VERSION 5.7 ;
BUSBITCHARS "[]" ;
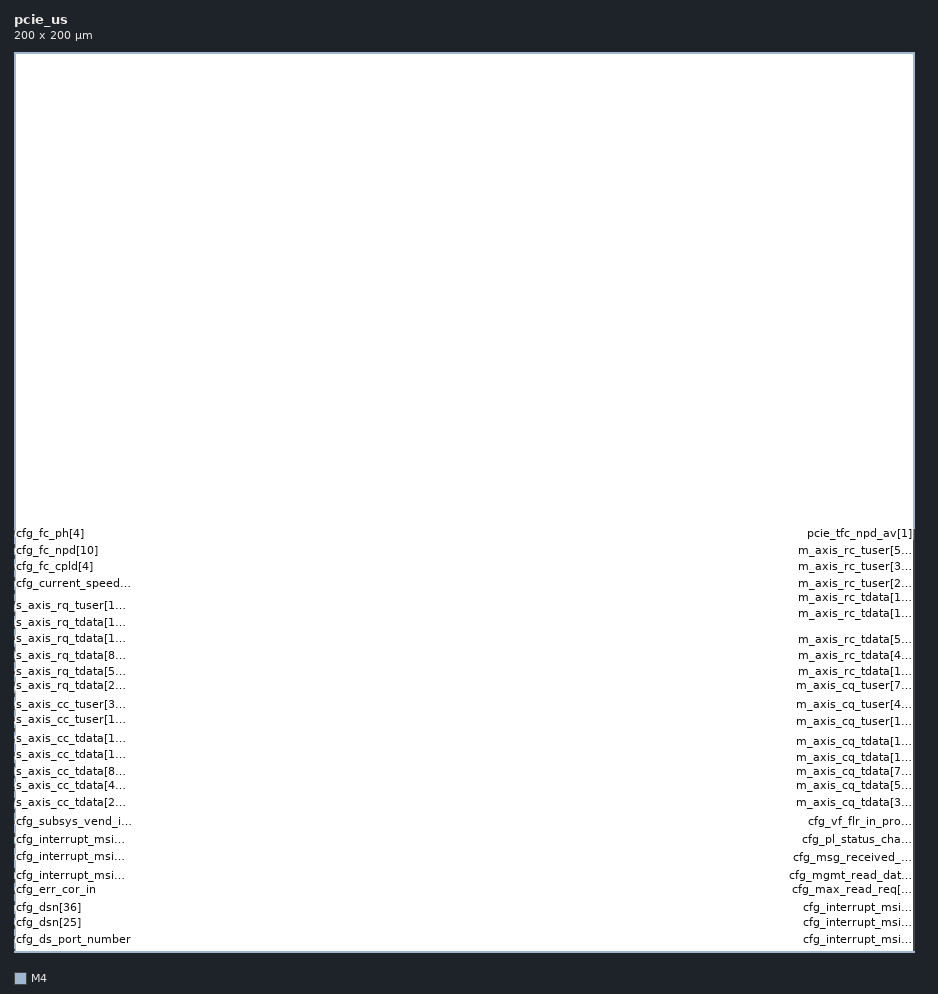
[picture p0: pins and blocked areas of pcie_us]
MACRO pcie_us
  CLASS BLOCK ;
  FOREIGN pcie_us 0 0 ;
  SYMMETRY X Y R90 ;
  SIZE 200.000 BY 200.000 ;
  PIN cfg_config_space_enable
    DIRECTION INPUT ;
    USE SIGNAL ;
    PORT
      LAYER M4 ;
      RECT 0.000 0.288 0.072 0.312 ;
    END
  END cfg_config_space_enable
  PIN cfg_ds_bus_number[0]
    DIRECTION INPUT ;
    USE SIGNAL ;
    PORT
      LAYER M4 ;
      RECT 0.000 0.432 0.072 0.456 ;
    END
  END cfg_ds_bus_number[0]
  PIN cfg_ds_bus_number[1]
    DIRECTION INPUT ;
    USE SIGNAL ;
    PORT
      LAYER M4 ;
      RECT 0.000 0.576 0.072 0.600 ;
    END
  END cfg_ds_bus_number[1]
  PIN cfg_ds_bus_number[2]
    DIRECTION INPUT ;
    USE SIGNAL ;
    PORT
      LAYER M4 ;
      RECT 0.000 0.720 0.072 0.744 ;
    END
  END cfg_ds_bus_number[2]
  PIN cfg_ds_bus_number[3]
    DIRECTION INPUT ;
    USE SIGNAL ;
    PORT
      LAYER M4 ;
      RECT 0.000 0.864 0.072 0.888 ;
    END
  END cfg_ds_bus_number[3]
  PIN cfg_ds_bus_number[4]
    DIRECTION INPUT ;
    USE SIGNAL ;
    PORT
      LAYER M4 ;
      RECT 0.000 1.008 0.072 1.032 ;
    END
  END cfg_ds_bus_number[4]
  PIN cfg_ds_bus_number[5]
    DIRECTION INPUT ;
    USE SIGNAL ;
    PORT
      LAYER M4 ;
      RECT 0.000 1.152 0.072 1.176 ;
    END
  END cfg_ds_bus_number[5]
  PIN cfg_ds_bus_number[6]
    DIRECTION INPUT ;
    USE SIGNAL ;
    PORT
      LAYER M4 ;
      RECT 0.000 1.296 0.072 1.320 ;
    END
  END cfg_ds_bus_number[6]
  PIN cfg_ds_bus_number[7]
    DIRECTION INPUT ;
    USE SIGNAL ;
    PORT
      LAYER M4 ;
      RECT 0.000 1.440 0.072 1.464 ;
    END
  END cfg_ds_bus_number[7]
  PIN cfg_ds_device_number[0]
    DIRECTION INPUT ;
    USE SIGNAL ;
    PORT
      LAYER M4 ;
      RECT 0.000 1.584 0.072 1.608 ;
    END
  END cfg_ds_device_number[0]
  PIN cfg_ds_device_number[1]
    DIRECTION INPUT ;
    USE SIGNAL ;
    PORT
      LAYER M4 ;
      RECT 0.000 1.728 0.072 1.752 ;
    END
  END cfg_ds_device_number[1]
  PIN cfg_ds_device_number[2]
    DIRECTION INPUT ;
    USE SIGNAL ;
    PORT
      LAYER M4 ;
      RECT 0.000 1.872 0.072 1.896 ;
    END
  END cfg_ds_device_number[2]
  PIN cfg_ds_device_number[3]
    DIRECTION INPUT ;
    USE SIGNAL ;
    PORT
      LAYER M4 ;
      RECT 0.000 2.016 0.072 2.040 ;
    END
  END cfg_ds_device_number[3]
  PIN cfg_ds_device_number[4]
    DIRECTION INPUT ;
    USE SIGNAL ;
    PORT
      LAYER M4 ;
      RECT 0.000 2.160 0.072 2.184 ;
    END
  END cfg_ds_device_number[4]
  PIN cfg_ds_function_number[0]
    DIRECTION INPUT ;
    USE SIGNAL ;
    PORT
      LAYER M4 ;
      RECT 0.000 2.304 0.072 2.328 ;
    END
  END cfg_ds_function_number[0]
  PIN cfg_ds_function_number[1]
    DIRECTION INPUT ;
    USE SIGNAL ;
    PORT
      LAYER M4 ;
      RECT 0.000 2.448 0.072 2.472 ;
    END
  END cfg_ds_function_number[1]
  PIN cfg_ds_function_number[2]
    DIRECTION INPUT ;
    USE SIGNAL ;
    PORT
      LAYER M4 ;
      RECT 0.000 2.592 0.072 2.616 ;
    END
  END cfg_ds_function_number[2]
  PIN cfg_ds_port_number
    DIRECTION INPUT ;
    USE SIGNAL ;
    PORT
      LAYER M4 ;
      RECT 0.000 2.736 0.072 2.760 ;
    END
  END cfg_ds_port_number
  PIN cfg_dsn[0]
    DIRECTION INPUT ;
    USE SIGNAL ;
    PORT
      LAYER M4 ;
      RECT 0.000 2.880 0.072 2.904 ;
    END
  END cfg_dsn[0]
  PIN cfg_dsn[1]
    DIRECTION INPUT ;
    USE SIGNAL ;
    PORT
      LAYER M4 ;
      RECT 0.000 3.024 0.072 3.048 ;
    END
  END cfg_dsn[1]
  PIN cfg_dsn[2]
    DIRECTION INPUT ;
    USE SIGNAL ;
    PORT
      LAYER M4 ;
      RECT 0.000 3.168 0.072 3.192 ;
    END
  END cfg_dsn[2]
  PIN cfg_dsn[3]
    DIRECTION INPUT ;
    USE SIGNAL ;
    PORT
      LAYER M4 ;
      RECT 0.000 3.312 0.072 3.336 ;
    END
  END cfg_dsn[3]
  PIN cfg_dsn[4]
    DIRECTION INPUT ;
    USE SIGNAL ;
    PORT
      LAYER M4 ;
      RECT 0.000 3.456 0.072 3.480 ;
    END
  END cfg_dsn[4]
  PIN cfg_dsn[5]
    DIRECTION INPUT ;
    USE SIGNAL ;
    PORT
      LAYER M4 ;
      RECT 0.000 3.600 0.072 3.624 ;
    END
  END cfg_dsn[5]
  PIN cfg_dsn[6]
    DIRECTION INPUT ;
    USE SIGNAL ;
    PORT
      LAYER M4 ;
      RECT 0.000 3.744 0.072 3.768 ;
    END
  END cfg_dsn[6]
  PIN cfg_dsn[7]
    DIRECTION INPUT ;
    USE SIGNAL ;
    PORT
      LAYER M4 ;
      RECT 0.000 3.888 0.072 3.912 ;
    END
  END cfg_dsn[7]
  PIN cfg_dsn[8]
    DIRECTION INPUT ;
    USE SIGNAL ;
    PORT
      LAYER M4 ;
      RECT 0.000 4.032 0.072 4.056 ;
    END
  END cfg_dsn[8]
  PIN cfg_dsn[9]
    DIRECTION INPUT ;
    USE SIGNAL ;
    PORT
      LAYER M4 ;
      RECT 0.000 4.176 0.072 4.200 ;
    END
  END cfg_dsn[9]
  PIN cfg_dsn[10]
    DIRECTION INPUT ;
    USE SIGNAL ;
    PORT
      LAYER M4 ;
      RECT 0.000 4.320 0.072 4.344 ;
    END
  END cfg_dsn[10]
  PIN cfg_dsn[11]
    DIRECTION INPUT ;
    USE SIGNAL ;
    PORT
      LAYER M4 ;
      RECT 0.000 4.464 0.072 4.488 ;
    END
  END cfg_dsn[11]
  PIN cfg_dsn[12]
    DIRECTION INPUT ;
    USE SIGNAL ;
    PORT
      LAYER M4 ;
      RECT 0.000 4.608 0.072 4.632 ;
    END
  END cfg_dsn[12]
  PIN cfg_dsn[13]
    DIRECTION INPUT ;
    USE SIGNAL ;
    PORT
      LAYER M4 ;
      RECT 0.000 4.752 0.072 4.776 ;
    END
  END cfg_dsn[13]
  PIN cfg_dsn[14]
    DIRECTION INPUT ;
    USE SIGNAL ;
    PORT
      LAYER M4 ;
      RECT 0.000 4.896 0.072 4.920 ;
    END
  END cfg_dsn[14]
  PIN cfg_dsn[15]
    DIRECTION INPUT ;
    USE SIGNAL ;
    PORT
      LAYER M4 ;
      RECT 0.000 5.040 0.072 5.064 ;
    END
  END cfg_dsn[15]
  PIN cfg_dsn[16]
    DIRECTION INPUT ;
    USE SIGNAL ;
    PORT
      LAYER M4 ;
      RECT 0.000 5.184 0.072 5.208 ;
    END
  END cfg_dsn[16]
  PIN cfg_dsn[17]
    DIRECTION INPUT ;
    USE SIGNAL ;
    PORT
      LAYER M4 ;
      RECT 0.000 5.328 0.072 5.352 ;
    END
  END cfg_dsn[17]
  PIN cfg_dsn[18]
    DIRECTION INPUT ;
    USE SIGNAL ;
    PORT
      LAYER M4 ;
      RECT 0.000 5.472 0.072 5.496 ;
    END
  END cfg_dsn[18]
  PIN cfg_dsn[19]
    DIRECTION INPUT ;
    USE SIGNAL ;
    PORT
      LAYER M4 ;
      RECT 0.000 5.616 0.072 5.640 ;
    END
  END cfg_dsn[19]
  PIN cfg_dsn[20]
    DIRECTION INPUT ;
    USE SIGNAL ;
    PORT
      LAYER M4 ;
      RECT 0.000 5.760 0.072 5.784 ;
    END
  END cfg_dsn[20]
  PIN cfg_dsn[21]
    DIRECTION INPUT ;
    USE SIGNAL ;
    PORT
      LAYER M4 ;
      RECT 0.000 5.904 0.072 5.928 ;
    END
  END cfg_dsn[21]
  PIN cfg_dsn[22]
    DIRECTION INPUT ;
    USE SIGNAL ;
    PORT
      LAYER M4 ;
      RECT 0.000 6.048 0.072 6.072 ;
    END
  END cfg_dsn[22]
  PIN cfg_dsn[23]
    DIRECTION INPUT ;
    USE SIGNAL ;
    PORT
      LAYER M4 ;
      RECT 0.000 6.192 0.072 6.216 ;
    END
  END cfg_dsn[23]
  PIN cfg_dsn[24]
    DIRECTION INPUT ;
    USE SIGNAL ;
    PORT
      LAYER M4 ;
      RECT 0.000 6.336 0.072 6.360 ;
    END
  END cfg_dsn[24]
  PIN cfg_dsn[25]
    DIRECTION INPUT ;
    USE SIGNAL ;
    PORT
      LAYER M4 ;
      RECT 0.000 6.480 0.072 6.504 ;
    END
  END cfg_dsn[25]
  PIN cfg_dsn[26]
    DIRECTION INPUT ;
    USE SIGNAL ;
    PORT
      LAYER M4 ;
      RECT 0.000 6.624 0.072 6.648 ;
    END
  END cfg_dsn[26]
  PIN cfg_dsn[27]
    DIRECTION INPUT ;
    USE SIGNAL ;
    PORT
      LAYER M4 ;
      RECT 0.000 6.768 0.072 6.792 ;
    END
  END cfg_dsn[27]
  PIN cfg_dsn[28]
    DIRECTION INPUT ;
    USE SIGNAL ;
    PORT
      LAYER M4 ;
      RECT 0.000 6.912 0.072 6.936 ;
    END
  END cfg_dsn[28]
  PIN cfg_dsn[29]
    DIRECTION INPUT ;
    USE SIGNAL ;
    PORT
      LAYER M4 ;
      RECT 0.000 7.056 0.072 7.080 ;
    END
  END cfg_dsn[29]
  PIN cfg_dsn[30]
    DIRECTION INPUT ;
    USE SIGNAL ;
    PORT
      LAYER M4 ;
      RECT 0.000 7.200 0.072 7.224 ;
    END
  END cfg_dsn[30]
  PIN cfg_dsn[31]
    DIRECTION INPUT ;
    USE SIGNAL ;
    PORT
      LAYER M4 ;
      RECT 0.000 7.344 0.072 7.368 ;
    END
  END cfg_dsn[31]
  PIN cfg_dsn[32]
    DIRECTION INPUT ;
    USE SIGNAL ;
    PORT
      LAYER M4 ;
      RECT 0.000 7.488 0.072 7.512 ;
    END
  END cfg_dsn[32]
  PIN cfg_dsn[33]
    DIRECTION INPUT ;
    USE SIGNAL ;
    PORT
      LAYER M4 ;
      RECT 0.000 7.632 0.072 7.656 ;
    END
  END cfg_dsn[33]
  PIN cfg_dsn[34]
    DIRECTION INPUT ;
    USE SIGNAL ;
    PORT
      LAYER M4 ;
      RECT 0.000 7.776 0.072 7.800 ;
    END
  END cfg_dsn[34]
  PIN cfg_dsn[35]
    DIRECTION INPUT ;
    USE SIGNAL ;
    PORT
      LAYER M4 ;
      RECT 0.000 7.920 0.072 7.944 ;
    END
  END cfg_dsn[35]
  PIN cfg_dsn[36]
    DIRECTION INPUT ;
    USE SIGNAL ;
    PORT
      LAYER M4 ;
      RECT 0.000 8.064 0.072 8.088 ;
    END
  END cfg_dsn[36]
  PIN cfg_dsn[37]
    DIRECTION INPUT ;
    USE SIGNAL ;
    PORT
      LAYER M4 ;
      RECT 0.000 8.208 0.072 8.232 ;
    END
  END cfg_dsn[37]
  PIN cfg_dsn[38]
    DIRECTION INPUT ;
    USE SIGNAL ;
    PORT
      LAYER M4 ;
      RECT 0.000 8.352 0.072 8.376 ;
    END
  END cfg_dsn[38]
  PIN cfg_dsn[39]
    DIRECTION INPUT ;
    USE SIGNAL ;
    PORT
      LAYER M4 ;
      RECT 0.000 8.496 0.072 8.520 ;
    END
  END cfg_dsn[39]
  PIN cfg_dsn[40]
    DIRECTION INPUT ;
    USE SIGNAL ;
    PORT
      LAYER M4 ;
      RECT 0.000 8.640 0.072 8.664 ;
    END
  END cfg_dsn[40]
  PIN cfg_dsn[41]
    DIRECTION INPUT ;
    USE SIGNAL ;
    PORT
      LAYER M4 ;
      RECT 0.000 8.784 0.072 8.808 ;
    END
  END cfg_dsn[41]
  PIN cfg_dsn[42]
    DIRECTION INPUT ;
    USE SIGNAL ;
    PORT
      LAYER M4 ;
      RECT 0.000 8.928 0.072 8.952 ;
    END
  END cfg_dsn[42]
  PIN cfg_dsn[43]
    DIRECTION INPUT ;
    USE SIGNAL ;
    PORT
      LAYER M4 ;
      RECT 0.000 9.072 0.072 9.096 ;
    END
  END cfg_dsn[43]
  PIN cfg_dsn[44]
    DIRECTION INPUT ;
    USE SIGNAL ;
    PORT
      LAYER M4 ;
      RECT 0.000 9.216 0.072 9.240 ;
    END
  END cfg_dsn[44]
  PIN cfg_dsn[45]
    DIRECTION INPUT ;
    USE SIGNAL ;
    PORT
      LAYER M4 ;
      RECT 0.000 9.360 0.072 9.384 ;
    END
  END cfg_dsn[45]
  PIN cfg_dsn[46]
    DIRECTION INPUT ;
    USE SIGNAL ;
    PORT
      LAYER M4 ;
      RECT 0.000 9.504 0.072 9.528 ;
    END
  END cfg_dsn[46]
  PIN cfg_dsn[47]
    DIRECTION INPUT ;
    USE SIGNAL ;
    PORT
      LAYER M4 ;
      RECT 0.000 9.648 0.072 9.672 ;
    END
  END cfg_dsn[47]
  PIN cfg_dsn[48]
    DIRECTION INPUT ;
    USE SIGNAL ;
    PORT
      LAYER M4 ;
      RECT 0.000 9.792 0.072 9.816 ;
    END
  END cfg_dsn[48]
  PIN cfg_dsn[49]
    DIRECTION INPUT ;
    USE SIGNAL ;
    PORT
      LAYER M4 ;
      RECT 0.000 9.936 0.072 9.960 ;
    END
  END cfg_dsn[49]
  PIN cfg_dsn[50]
    DIRECTION INPUT ;
    USE SIGNAL ;
    PORT
      LAYER M4 ;
      RECT 0.000 10.080 0.072 10.104 ;
    END
  END cfg_dsn[50]
  PIN cfg_dsn[51]
    DIRECTION INPUT ;
    USE SIGNAL ;
    PORT
      LAYER M4 ;
      RECT 0.000 10.224 0.072 10.248 ;
    END
  END cfg_dsn[51]
  PIN cfg_dsn[52]
    DIRECTION INPUT ;
    USE SIGNAL ;
    PORT
      LAYER M4 ;
      RECT 0.000 10.368 0.072 10.392 ;
    END
  END cfg_dsn[52]
  PIN cfg_dsn[53]
    DIRECTION INPUT ;
    USE SIGNAL ;
    PORT
      LAYER M4 ;
      RECT 0.000 10.512 0.072 10.536 ;
    END
  END cfg_dsn[53]
  PIN cfg_dsn[54]
    DIRECTION INPUT ;
    USE SIGNAL ;
    PORT
      LAYER M4 ;
      RECT 0.000 10.656 0.072 10.680 ;
    END
  END cfg_dsn[54]
  PIN cfg_dsn[55]
    DIRECTION INPUT ;
    USE SIGNAL ;
    PORT
      LAYER M4 ;
      RECT 0.000 10.800 0.072 10.824 ;
    END
  END cfg_dsn[55]
  PIN cfg_dsn[56]
    DIRECTION INPUT ;
    USE SIGNAL ;
    PORT
      LAYER M4 ;
      RECT 0.000 10.944 0.072 10.968 ;
    END
  END cfg_dsn[56]
  PIN cfg_dsn[57]
    DIRECTION INPUT ;
    USE SIGNAL ;
    PORT
      LAYER M4 ;
      RECT 0.000 11.088 0.072 11.112 ;
    END
  END cfg_dsn[57]
  PIN cfg_dsn[58]
    DIRECTION INPUT ;
    USE SIGNAL ;
    PORT
      LAYER M4 ;
      RECT 0.000 11.232 0.072 11.256 ;
    END
  END cfg_dsn[58]
  PIN cfg_dsn[59]
    DIRECTION INPUT ;
    USE SIGNAL ;
    PORT
      LAYER M4 ;
      RECT 0.000 11.376 0.072 11.400 ;
    END
  END cfg_dsn[59]
  PIN cfg_dsn[60]
    DIRECTION INPUT ;
    USE SIGNAL ;
    PORT
      LAYER M4 ;
      RECT 0.000 11.520 0.072 11.544 ;
    END
  END cfg_dsn[60]
  PIN cfg_dsn[61]
    DIRECTION INPUT ;
    USE SIGNAL ;
    PORT
      LAYER M4 ;
      RECT 0.000 11.664 0.072 11.688 ;
    END
  END cfg_dsn[61]
  PIN cfg_dsn[62]
    DIRECTION INPUT ;
    USE SIGNAL ;
    PORT
      LAYER M4 ;
      RECT 0.000 11.808 0.072 11.832 ;
    END
  END cfg_dsn[62]
  PIN cfg_dsn[63]
    DIRECTION INPUT ;
    USE SIGNAL ;
    PORT
      LAYER M4 ;
      RECT 0.000 11.952 0.072 11.976 ;
    END
  END cfg_dsn[63]
  PIN cfg_err_cor_in
    DIRECTION INPUT ;
    USE SIGNAL ;
    PORT
      LAYER M4 ;
      RECT 0.000 12.096 0.072 12.120 ;
    END
  END cfg_err_cor_in
  PIN cfg_err_uncor_in
    DIRECTION INPUT ;
    USE SIGNAL ;
    PORT
      LAYER M4 ;
      RECT 0.000 12.240 0.072 12.264 ;
    END
  END cfg_err_uncor_in
  PIN cfg_fc_sel
    DIRECTION INPUT ;
    USE SIGNAL ;
    PORT
      LAYER M4 ;
      RECT 0.000 12.384 0.072 12.408 ;
    END
  END cfg_fc_sel
  PIN cfg_flr_done
    DIRECTION INPUT ;
    USE SIGNAL ;
    PORT
      LAYER M4 ;
      RECT 0.000 12.528 0.072 12.552 ;
    END
  END cfg_flr_done
  PIN cfg_hot_reset_in
    DIRECTION INPUT ;
    USE SIGNAL ;
    PORT
      LAYER M4 ;
      RECT 0.000 12.672 0.072 12.696 ;
    END
  END cfg_hot_reset_in
  PIN cfg_interrupt_int
    DIRECTION INPUT ;
    USE SIGNAL ;
    PORT
      LAYER M4 ;
      RECT 0.000 12.816 0.072 12.840 ;
    END
  END cfg_interrupt_int
  PIN cfg_interrupt_msi_attr
    DIRECTION INPUT ;
    USE SIGNAL ;
    PORT
      LAYER M4 ;
      RECT 0.000 12.960 0.072 12.984 ;
    END
  END cfg_interrupt_msi_attr
  PIN cfg_interrupt_msi_function_number
    DIRECTION INPUT ;
    USE SIGNAL ;
    PORT
      LAYER M4 ;
      RECT 0.000 13.104 0.072 13.128 ;
    END
  END cfg_interrupt_msi_function_number
  PIN cfg_interrupt_msi_int[0]
    DIRECTION INPUT ;
    USE SIGNAL ;
    PORT
      LAYER M4 ;
      RECT 0.000 13.248 0.072 13.272 ;
    END
  END cfg_interrupt_msi_int[0]
  PIN cfg_interrupt_msi_int[1]
    DIRECTION INPUT ;
    USE SIGNAL ;
    PORT
      LAYER M4 ;
      RECT 0.000 13.392 0.072 13.416 ;
    END
  END cfg_interrupt_msi_int[1]
  PIN cfg_interrupt_msi_int[2]
    DIRECTION INPUT ;
    USE SIGNAL ;
    PORT
      LAYER M4 ;
      RECT 0.000 13.536 0.072 13.560 ;
    END
  END cfg_interrupt_msi_int[2]
  PIN cfg_interrupt_msi_int[3]
    DIRECTION INPUT ;
    USE SIGNAL ;
    PORT
      LAYER M4 ;
      RECT 0.000 13.680 0.072 13.704 ;
    END
  END cfg_interrupt_msi_int[3]
  PIN cfg_interrupt_msi_int[4]
    DIRECTION INPUT ;
    USE SIGNAL ;
    PORT
      LAYER M4 ;
      RECT 0.000 13.824 0.072 13.848 ;
    END
  END cfg_interrupt_msi_int[4]
  PIN cfg_interrupt_msi_int[5]
    DIRECTION INPUT ;
    USE SIGNAL ;
    PORT
      LAYER M4 ;
      RECT 0.000 13.968 0.072 13.992 ;
    END
  END cfg_interrupt_msi_int[5]
  PIN cfg_interrupt_msi_int[6]
    DIRECTION INPUT ;
    USE SIGNAL ;
    PORT
      LAYER M4 ;
      RECT 0.000 14.112 0.072 14.136 ;
    END
  END cfg_interrupt_msi_int[6]
  PIN cfg_interrupt_msi_int[7]
    DIRECTION INPUT ;
    USE SIGNAL ;
    PORT
      LAYER M4 ;
      RECT 0.000 14.256 0.072 14.280 ;
    END
  END cfg_interrupt_msi_int[7]
  PIN cfg_interrupt_msi_int[8]
    DIRECTION INPUT ;
    USE SIGNAL ;
    PORT
      LAYER M4 ;
      RECT 0.000 14.400 0.072 14.424 ;
    END
  END cfg_interrupt_msi_int[8]
  PIN cfg_interrupt_msi_int[9]
    DIRECTION INPUT ;
    USE SIGNAL ;
    PORT
      LAYER M4 ;
      RECT 0.000 14.544 0.072 14.568 ;
    END
  END cfg_interrupt_msi_int[9]
  PIN cfg_interrupt_msi_int[10]
    DIRECTION INPUT ;
    USE SIGNAL ;
    PORT
      LAYER M4 ;
      RECT 0.000 14.688 0.072 14.712 ;
    END
  END cfg_interrupt_msi_int[10]
  PIN cfg_interrupt_msi_int[11]
    DIRECTION INPUT ;
    USE SIGNAL ;
    PORT
      LAYER M4 ;
      RECT 0.000 14.832 0.072 14.856 ;
    END
  END cfg_interrupt_msi_int[11]
  PIN cfg_interrupt_msi_int[12]
    DIRECTION INPUT ;
    USE SIGNAL ;
    PORT
      LAYER M4 ;
      RECT 0.000 14.976 0.072 15.000 ;
    END
  END cfg_interrupt_msi_int[12]
  PIN cfg_interrupt_msi_int[13]
    DIRECTION INPUT ;
    USE SIGNAL ;
    PORT
      LAYER M4 ;
      RECT 0.000 15.120 0.072 15.144 ;
    END
  END cfg_interrupt_msi_int[13]
  PIN cfg_interrupt_msi_int[14]
    DIRECTION INPUT ;
    USE SIGNAL ;
    PORT
      LAYER M4 ;
      RECT 0.000 15.264 0.072 15.288 ;
    END
  END cfg_interrupt_msi_int[14]
  PIN cfg_interrupt_msi_int[15]
    DIRECTION INPUT ;
    USE SIGNAL ;
    PORT
      LAYER M4 ;
      RECT 0.000 15.408 0.072 15.432 ;
    END
  END cfg_interrupt_msi_int[15]
  PIN cfg_interrupt_msi_int[16]
    DIRECTION INPUT ;
    USE SIGNAL ;
    PORT
      LAYER M4 ;
      RECT 0.000 15.552 0.072 15.576 ;
    END
  END cfg_interrupt_msi_int[16]
  PIN cfg_interrupt_msi_int[17]
    DIRECTION INPUT ;
    USE SIGNAL ;
    PORT
      LAYER M4 ;
      RECT 0.000 15.696 0.072 15.720 ;
    END
  END cfg_interrupt_msi_int[17]
  PIN cfg_interrupt_msi_int[18]
    DIRECTION INPUT ;
    USE SIGNAL ;
    PORT
      LAYER M4 ;
      RECT 0.000 15.840 0.072 15.864 ;
    END
  END cfg_interrupt_msi_int[18]
  PIN cfg_interrupt_msi_int[19]
    DIRECTION INPUT ;
    USE SIGNAL ;
    PORT
      LAYER M4 ;
      RECT 0.000 15.984 0.072 16.008 ;
    END
  END cfg_interrupt_msi_int[19]
  PIN cfg_interrupt_msi_int[20]
    DIRECTION INPUT ;
    USE SIGNAL ;
    PORT
      LAYER M4 ;
      RECT 0.000 16.128 0.072 16.152 ;
    END
  END cfg_interrupt_msi_int[20]
  PIN cfg_interrupt_msi_int[21]
    DIRECTION INPUT ;
    USE SIGNAL ;
    PORT
      LAYER M4 ;
      RECT 0.000 16.272 0.072 16.296 ;
    END
  END cfg_interrupt_msi_int[21]
  PIN cfg_interrupt_msi_int[22]
    DIRECTION INPUT ;
    USE SIGNAL ;
    PORT
      LAYER M4 ;
      RECT 0.000 16.416 0.072 16.440 ;
    END
  END cfg_interrupt_msi_int[22]
  PIN cfg_interrupt_msi_int[23]
    DIRECTION INPUT ;
    USE SIGNAL ;
    PORT
      LAYER M4 ;
      RECT 0.000 16.560 0.072 16.584 ;
    END
  END cfg_interrupt_msi_int[23]
  PIN cfg_interrupt_msi_int[24]
    DIRECTION INPUT ;
    USE SIGNAL ;
    PORT
      LAYER M4 ;
      RECT 0.000 16.704 0.072 16.728 ;
    END
  END cfg_interrupt_msi_int[24]
  PIN cfg_interrupt_msi_int[25]
    DIRECTION INPUT ;
    USE SIGNAL ;
    PORT
      LAYER M4 ;
      RECT 0.000 16.848 0.072 16.872 ;
    END
  END cfg_interrupt_msi_int[25]
  PIN cfg_interrupt_msi_int[26]
    DIRECTION INPUT ;
    USE SIGNAL ;
    PORT
      LAYER M4 ;
      RECT 0.000 16.992 0.072 17.016 ;
    END
  END cfg_interrupt_msi_int[26]
  PIN cfg_interrupt_msi_int[27]
    DIRECTION INPUT ;
    USE SIGNAL ;
    PORT
      LAYER M4 ;
      RECT 0.000 17.136 0.072 17.160 ;
    END
  END cfg_interrupt_msi_int[27]
  PIN cfg_interrupt_msi_int[28]
    DIRECTION INPUT ;
    USE SIGNAL ;
    PORT
      LAYER M4 ;
      RECT 0.000 17.280 0.072 17.304 ;
    END
  END cfg_interrupt_msi_int[28]
  PIN cfg_interrupt_msi_int[29]
    DIRECTION INPUT ;
    USE SIGNAL ;
    PORT
      LAYER M4 ;
      RECT 0.000 17.424 0.072 17.448 ;
    END
  END cfg_interrupt_msi_int[29]
  PIN cfg_interrupt_msi_int[30]
    DIRECTION INPUT ;
    USE SIGNAL ;
    PORT
      LAYER M4 ;
      RECT 0.000 17.568 0.072 17.592 ;
    END
  END cfg_interrupt_msi_int[30]
  PIN cfg_interrupt_msi_int[31]
    DIRECTION INPUT ;
    USE SIGNAL ;
    PORT
      LAYER M4 ;
      RECT 0.000 17.712 0.072 17.736 ;
    END
  END cfg_interrupt_msi_int[31]
  PIN cfg_interrupt_msi_pending_status[0]
    DIRECTION INPUT ;
    USE SIGNAL ;
    PORT
      LAYER M4 ;
      RECT 0.000 17.856 0.072 17.880 ;
    END
  END cfg_interrupt_msi_pending_status[0]
  PIN cfg_interrupt_msi_pending_status[1]
    DIRECTION INPUT ;
    USE SIGNAL ;
    PORT
      LAYER M4 ;
      RECT 0.000 18.000 0.072 18.024 ;
    END
  END cfg_interrupt_msi_pending_status[1]
  PIN cfg_interrupt_msi_pending_status[2]
    DIRECTION INPUT ;
    USE SIGNAL ;
    PORT
      LAYER M4 ;
      RECT 0.000 18.144 0.072 18.168 ;
    END
  END cfg_interrupt_msi_pending_status[2]
  PIN cfg_interrupt_msi_pending_status[3]
    DIRECTION INPUT ;
    USE SIGNAL ;
    PORT
      LAYER M4 ;
      RECT 0.000 18.288 0.072 18.312 ;
    END
  END cfg_interrupt_msi_pending_status[3]
  PIN cfg_interrupt_msi_pending_status[4]
    DIRECTION INPUT ;
    USE SIGNAL ;
    PORT
      LAYER M4 ;
      RECT 0.000 18.432 0.072 18.456 ;
    END
  END cfg_interrupt_msi_pending_status[4]
  PIN cfg_interrupt_msi_pending_status[5]
    DIRECTION INPUT ;
    USE SIGNAL ;
    PORT
      LAYER M4 ;
      RECT 0.000 18.576 0.072 18.600 ;
    END
  END cfg_interrupt_msi_pending_status[5]
  PIN cfg_interrupt_msi_pending_status[6]
    DIRECTION INPUT ;
    USE SIGNAL ;
    PORT
      LAYER M4 ;
      RECT 0.000 18.720 0.072 18.744 ;
    END
  END cfg_interrupt_msi_pending_status[6]
  PIN cfg_interrupt_msi_pending_status[7]
    DIRECTION INPUT ;
    USE SIGNAL ;
    PORT
      LAYER M4 ;
      RECT 0.000 18.864 0.072 18.888 ;
    END
  END cfg_interrupt_msi_pending_status[7]
  PIN cfg_interrupt_msi_pending_status[8]
    DIRECTION INPUT ;
    USE SIGNAL ;
    PORT
      LAYER M4 ;
      RECT 0.000 19.008 0.072 19.032 ;
    END
  END cfg_interrupt_msi_pending_status[8]
  PIN cfg_interrupt_msi_pending_status[9]
    DIRECTION INPUT ;
    USE SIGNAL ;
    PORT
      LAYER M4 ;
      RECT 0.000 19.152 0.072 19.176 ;
    END
  END cfg_interrupt_msi_pending_status[9]
  PIN cfg_interrupt_msi_pending_status[10]
    DIRECTION INPUT ;
    USE SIGNAL ;
    PORT
      LAYER M4 ;
      RECT 0.000 19.296 0.072 19.320 ;
    END
  END cfg_interrupt_msi_pending_status[10]
  PIN cfg_interrupt_msi_pending_status[11]
    DIRECTION INPUT ;
    USE SIGNAL ;
    PORT
      LAYER M4 ;
      RECT 0.000 19.440 0.072 19.464 ;
    END
  END cfg_interrupt_msi_pending_status[11]
  PIN cfg_interrupt_msi_pending_status[12]
    DIRECTION INPUT ;
    USE SIGNAL ;
    PORT
      LAYER M4 ;
      RECT 0.000 19.584 0.072 19.608 ;
    END
  END cfg_interrupt_msi_pending_status[12]
  PIN cfg_interrupt_msi_pending_status[13]
    DIRECTION INPUT ;
    USE SIGNAL ;
    PORT
      LAYER M4 ;
      RECT 0.000 19.728 0.072 19.752 ;
    END
  END cfg_interrupt_msi_pending_status[13]
  PIN cfg_interrupt_msi_pending_status[14]
    DIRECTION INPUT ;
    USE SIGNAL ;
    PORT
      LAYER M4 ;
      RECT 0.000 19.872 0.072 19.896 ;
    END
  END cfg_interrupt_msi_pending_status[14]
  PIN cfg_interrupt_msi_pending_status[15]
    DIRECTION INPUT ;
    USE SIGNAL ;
    PORT
      LAYER M4 ;
      RECT 0.000 20.016 0.072 20.040 ;
    END
  END cfg_interrupt_msi_pending_status[15]
  PIN cfg_interrupt_msi_pending_status[16]
    DIRECTION INPUT ;
    USE SIGNAL ;
    PORT
      LAYER M4 ;
      RECT 0.000 20.160 0.072 20.184 ;
    END
  END cfg_interrupt_msi_pending_status[16]
  PIN cfg_interrupt_msi_pending_status[17]
    DIRECTION INPUT ;
    USE SIGNAL ;
    PORT
      LAYER M4 ;
      RECT 0.000 20.304 0.072 20.328 ;
    END
  END cfg_interrupt_msi_pending_status[17]
  PIN cfg_interrupt_msi_pending_status[18]
    DIRECTION INPUT ;
    USE SIGNAL ;
    PORT
      LAYER M4 ;
      RECT 0.000 20.448 0.072 20.472 ;
    END
  END cfg_interrupt_msi_pending_status[18]
  PIN cfg_interrupt_msi_pending_status[19]
    DIRECTION INPUT ;
    USE SIGNAL ;
    PORT
      LAYER M4 ;
      RECT 0.000 20.592 0.072 20.616 ;
    END
  END cfg_interrupt_msi_pending_status[19]
  PIN cfg_interrupt_msi_pending_status[20]
    DIRECTION INPUT ;
    USE SIGNAL ;
    PORT
      LAYER M4 ;
      RECT 0.000 20.736 0.072 20.760 ;
    END
  END cfg_interrupt_msi_pending_status[20]
  PIN cfg_interrupt_msi_pending_status[21]
    DIRECTION INPUT ;
    USE SIGNAL ;
    PORT
      LAYER M4 ;
      RECT 0.000 20.880 0.072 20.904 ;
    END
  END cfg_interrupt_msi_pending_status[21]
  PIN cfg_interrupt_msi_pending_status[22]
    DIRECTION INPUT ;
    USE SIGNAL ;
    PORT
      LAYER M4 ;
      RECT 0.000 21.024 0.072 21.048 ;
    END
  END cfg_interrupt_msi_pending_status[22]
  PIN cfg_interrupt_msi_pending_status[23]
    DIRECTION INPUT ;
    USE SIGNAL ;
    PORT
      LAYER M4 ;
      RECT 0.000 21.168 0.072 21.192 ;
    END
  END cfg_interrupt_msi_pending_status[23]
  PIN cfg_interrupt_msi_pending_status[24]
    DIRECTION INPUT ;
    USE SIGNAL ;
    PORT
      LAYER M4 ;
      RECT 0.000 21.312 0.072 21.336 ;
    END
  END cfg_interrupt_msi_pending_status[24]
  PIN cfg_interrupt_msi_pending_status[25]
    DIRECTION INPUT ;
    USE SIGNAL ;
    PORT
      LAYER M4 ;
      RECT 0.000 21.456 0.072 21.480 ;
    END
  END cfg_interrupt_msi_pending_status[25]
  PIN cfg_interrupt_msi_pending_status[26]
    DIRECTION INPUT ;
    USE SIGNAL ;
    PORT
      LAYER M4 ;
      RECT 0.000 21.600 0.072 21.624 ;
    END
  END cfg_interrupt_msi_pending_status[26]
  PIN cfg_interrupt_msi_pending_status[27]
    DIRECTION INPUT ;
    USE SIGNAL ;
    PORT
      LAYER M4 ;
      RECT 0.000 21.744 0.072 21.768 ;
    END
  END cfg_interrupt_msi_pending_status[27]
  PIN cfg_interrupt_msi_pending_status[28]
    DIRECTION INPUT ;
    USE SIGNAL ;
    PORT
      LAYER M4 ;
      RECT 0.000 21.888 0.072 21.912 ;
    END
  END cfg_interrupt_msi_pending_status[28]
  PIN cfg_interrupt_msi_pending_status[29]
    DIRECTION INPUT ;
    USE SIGNAL ;
    PORT
      LAYER M4 ;
      RECT 0.000 22.032 0.072 22.056 ;
    END
  END cfg_interrupt_msi_pending_status[29]
  PIN cfg_interrupt_msi_pending_status[30]
    DIRECTION INPUT ;
    USE SIGNAL ;
    PORT
      LAYER M4 ;
      RECT 0.000 22.176 0.072 22.200 ;
    END
  END cfg_interrupt_msi_pending_status[30]
  PIN cfg_interrupt_msi_pending_status[31]
    DIRECTION INPUT ;
    USE SIGNAL ;
    PORT
      LAYER M4 ;
      RECT 0.000 22.320 0.072 22.344 ;
    END
  END cfg_interrupt_msi_pending_status[31]
  PIN cfg_interrupt_msi_pending_status_data_enable
    DIRECTION INPUT ;
    USE SIGNAL ;
    PORT
      LAYER M4 ;
      RECT 0.000 22.464 0.072 22.488 ;
    END
  END cfg_interrupt_msi_pending_status_data_enable
  PIN cfg_interrupt_msi_pending_status_function_num
    DIRECTION INPUT ;
    USE SIGNAL ;
    PORT
      LAYER M4 ;
      RECT 0.000 22.608 0.072 22.632 ;
    END
  END cfg_interrupt_msi_pending_status_function_num
  PIN cfg_interrupt_msi_select
    DIRECTION INPUT ;
    USE SIGNAL ;
    PORT
      LAYER M4 ;
      RECT 0.000 22.752 0.072 22.776 ;
    END
  END cfg_interrupt_msi_select
  PIN cfg_interrupt_msi_tph_present
    DIRECTION INPUT ;
    USE SIGNAL ;
    PORT
      LAYER M4 ;
      RECT 0.000 22.896 0.072 22.920 ;
    END
  END cfg_interrupt_msi_tph_present
  PIN cfg_interrupt_msi_tph_st_tag
    DIRECTION INPUT ;
    USE SIGNAL ;
    PORT
      LAYER M4 ;
      RECT 0.000 23.040 0.072 23.064 ;
    END
  END cfg_interrupt_msi_tph_st_tag
  PIN cfg_interrupt_msi_tph_type
    DIRECTION INPUT ;
    USE SIGNAL ;
    PORT
      LAYER M4 ;
      RECT 0.000 23.184 0.072 23.208 ;
    END
  END cfg_interrupt_msi_tph_type
  PIN cfg_interrupt_pending
    DIRECTION INPUT ;
    USE SIGNAL ;
    PORT
      LAYER M4 ;
      RECT 0.000 23.328 0.072 23.352 ;
    END
  END cfg_interrupt_pending
  PIN cfg_link_training_enable
    DIRECTION INPUT ;
    USE SIGNAL ;
    PORT
      LAYER M4 ;
      RECT 0.000 23.472 0.072 23.496 ;
    END
  END cfg_link_training_enable
  PIN cfg_mgmt_addr
    DIRECTION INPUT ;
    USE SIGNAL ;
    PORT
      LAYER M4 ;
      RECT 0.000 23.616 0.072 23.640 ;
    END
  END cfg_mgmt_addr
  PIN cfg_mgmt_byte_enable
    DIRECTION INPUT ;
    USE SIGNAL ;
    PORT
      LAYER M4 ;
      RECT 0.000 23.760 0.072 23.784 ;
    END
  END cfg_mgmt_byte_enable
  PIN cfg_mgmt_read
    DIRECTION INPUT ;
    USE SIGNAL ;
    PORT
      LAYER M4 ;
      RECT 0.000 23.904 0.072 23.928 ;
    END
  END cfg_mgmt_read
  PIN cfg_mgmt_type1_cfg_reg_access
    DIRECTION INPUT ;
    USE SIGNAL ;
    PORT
      LAYER M4 ;
      RECT 0.000 24.048 0.072 24.072 ;
    END
  END cfg_mgmt_type1_cfg_reg_access
  PIN cfg_mgmt_write
    DIRECTION INPUT ;
    USE SIGNAL ;
    PORT
      LAYER M4 ;
      RECT 0.000 24.192 0.072 24.216 ;
    END
  END cfg_mgmt_write
  PIN cfg_mgmt_write_data
    DIRECTION INPUT ;
    USE SIGNAL ;
    PORT
      LAYER M4 ;
      RECT 0.000 24.336 0.072 24.360 ;
    END
  END cfg_mgmt_write_data
  PIN cfg_msg_transmit
    DIRECTION INPUT ;
    USE SIGNAL ;
    PORT
      LAYER M4 ;
      RECT 0.000 24.480 0.072 24.504 ;
    END
  END cfg_msg_transmit
  PIN cfg_msg_transmit_data
    DIRECTION INPUT ;
    USE SIGNAL ;
    PORT
      LAYER M4 ;
      RECT 0.000 24.624 0.072 24.648 ;
    END
  END cfg_msg_transmit_data
  PIN cfg_msg_transmit_type
    DIRECTION INPUT ;
    USE SIGNAL ;
    PORT
      LAYER M4 ;
      RECT 0.000 24.768 0.072 24.792 ;
    END
  END cfg_msg_transmit_type
  PIN cfg_per_func_status_control
    DIRECTION INPUT ;
    USE SIGNAL ;
    PORT
      LAYER M4 ;
      RECT 0.000 24.912 0.072 24.936 ;
    END
  END cfg_per_func_status_control
  PIN cfg_per_function_number
    DIRECTION INPUT ;
    USE SIGNAL ;
    PORT
      LAYER M4 ;
      RECT 0.000 25.056 0.072 25.080 ;
    END
  END cfg_per_function_number
  PIN cfg_per_function_output_request
    DIRECTION INPUT ;
    USE SIGNAL ;
    PORT
      LAYER M4 ;
      RECT 0.000 25.200 0.072 25.224 ;
    END
  END cfg_per_function_output_request
  PIN cfg_power_state_change_ack
    DIRECTION INPUT ;
    USE SIGNAL ;
    PORT
      LAYER M4 ;
      RECT 0.000 25.344 0.072 25.368 ;
    END
  END cfg_power_state_change_ack
  PIN cfg_req_pm_transition_l23_ready
    DIRECTION INPUT ;
    USE SIGNAL ;
    PORT
      LAYER M4 ;
      RECT 0.000 25.488 0.072 25.512 ;
    END
  END cfg_req_pm_transition_l23_ready
  PIN cfg_subsys_vend_id[0]
    DIRECTION INPUT ;
    USE SIGNAL ;
    PORT
      LAYER M4 ;
      RECT 0.000 25.632 0.072 25.656 ;
    END
  END cfg_subsys_vend_id[0]
  PIN cfg_subsys_vend_id[1]
    DIRECTION INPUT ;
    USE SIGNAL ;
    PORT
      LAYER M4 ;
      RECT 0.000 25.776 0.072 25.800 ;
    END
  END cfg_subsys_vend_id[1]
  PIN cfg_subsys_vend_id[2]
    DIRECTION INPUT ;
    USE SIGNAL ;
    PORT
      LAYER M4 ;
      RECT 0.000 25.920 0.072 25.944 ;
    END
  END cfg_subsys_vend_id[2]
  PIN cfg_subsys_vend_id[3]
    DIRECTION INPUT ;
    USE SIGNAL ;
    PORT
      LAYER M4 ;
      RECT 0.000 26.064 0.072 26.088 ;
    END
  END cfg_subsys_vend_id[3]
  PIN cfg_subsys_vend_id[4]
    DIRECTION INPUT ;
    USE SIGNAL ;
    PORT
      LAYER M4 ;
      RECT 0.000 26.208 0.072 26.232 ;
    END
  END cfg_subsys_vend_id[4]
  PIN cfg_subsys_vend_id[5]
    DIRECTION INPUT ;
    USE SIGNAL ;
    PORT
      LAYER M4 ;
      RECT 0.000 26.352 0.072 26.376 ;
    END
  END cfg_subsys_vend_id[5]
  PIN cfg_subsys_vend_id[6]
    DIRECTION INPUT ;
    USE SIGNAL ;
    PORT
      LAYER M4 ;
      RECT 0.000 26.496 0.072 26.520 ;
    END
  END cfg_subsys_vend_id[6]
  PIN cfg_subsys_vend_id[7]
    DIRECTION INPUT ;
    USE SIGNAL ;
    PORT
      LAYER M4 ;
      RECT 0.000 26.640 0.072 26.664 ;
    END
  END cfg_subsys_vend_id[7]
  PIN cfg_subsys_vend_id[8]
    DIRECTION INPUT ;
    USE SIGNAL ;
    PORT
      LAYER M4 ;
      RECT 0.000 26.784 0.072 26.808 ;
    END
  END cfg_subsys_vend_id[8]
  PIN cfg_subsys_vend_id[9]
    DIRECTION INPUT ;
    USE SIGNAL ;
    PORT
      LAYER M4 ;
      RECT 0.000 26.928 0.072 26.952 ;
    END
  END cfg_subsys_vend_id[9]
  PIN cfg_subsys_vend_id[10]
    DIRECTION INPUT ;
    USE SIGNAL ;
    PORT
      LAYER M4 ;
      RECT 0.000 27.072 0.072 27.096 ;
    END
  END cfg_subsys_vend_id[10]
  PIN cfg_subsys_vend_id[11]
    DIRECTION INPUT ;
    USE SIGNAL ;
    PORT
      LAYER M4 ;
      RECT 0.000 27.216 0.072 27.240 ;
    END
  END cfg_subsys_vend_id[11]
  PIN cfg_subsys_vend_id[12]
    DIRECTION INPUT ;
    USE SIGNAL ;
    PORT
      LAYER M4 ;
      RECT 0.000 27.360 0.072 27.384 ;
    END
  END cfg_subsys_vend_id[12]
  PIN cfg_vf_flr_done
    DIRECTION INPUT ;
    USE SIGNAL ;
    PORT
      LAYER M4 ;
      RECT 0.000 27.504 0.072 27.528 ;
    END
  END cfg_vf_flr_done
  PIN m_axis_cq_tready[0]
    DIRECTION INPUT ;
    USE SIGNAL ;
    PORT
      LAYER M4 ;
      RECT 0.000 27.648 0.072 27.672 ;
    END
  END m_axis_cq_tready[0]
  PIN m_axis_cq_tready[1]
    DIRECTION INPUT ;
    USE SIGNAL ;
    PORT
      LAYER M4 ;
      RECT 0.000 27.792 0.072 27.816 ;
    END
  END m_axis_cq_tready[1]
  PIN m_axis_cq_tready[2]
    DIRECTION INPUT ;
    USE SIGNAL ;
    PORT
      LAYER M4 ;
      RECT 0.000 27.936 0.072 27.960 ;
    END
  END m_axis_cq_tready[2]
  PIN m_axis_cq_tready[3]
    DIRECTION INPUT ;
    USE SIGNAL ;
    PORT
      LAYER M4 ;
      RECT 0.000 28.080 0.072 28.104 ;
    END
  END m_axis_cq_tready[3]
  PIN m_axis_rc_tready[0]
    DIRECTION INPUT ;
    USE SIGNAL ;
    PORT
      LAYER M4 ;
      RECT 0.000 28.224 0.072 28.248 ;
    END
  END m_axis_rc_tready[0]
  PIN m_axis_rc_tready[1]
    DIRECTION INPUT ;
    USE SIGNAL ;
    PORT
      LAYER M4 ;
      RECT 0.000 28.368 0.072 28.392 ;
    END
  END m_axis_rc_tready[1]
  PIN m_axis_rc_tready[2]
    DIRECTION INPUT ;
    USE SIGNAL ;
    PORT
      LAYER M4 ;
      RECT 0.000 28.512 0.072 28.536 ;
    END
  END m_axis_rc_tready[2]
  PIN m_axis_rc_tready[3]
    DIRECTION INPUT ;
    USE SIGNAL ;
    PORT
      LAYER M4 ;
      RECT 0.000 28.656 0.072 28.680 ;
    END
  END m_axis_rc_tready[3]
  PIN pci_exp_rxn
    DIRECTION INPUT ;
    USE SIGNAL ;
    PORT
      LAYER M4 ;
      RECT 0.000 28.800 0.072 28.824 ;
    END
  END pci_exp_rxn
  PIN pci_exp_rxp
    DIRECTION INPUT ;
    USE SIGNAL ;
    PORT
      LAYER M4 ;
      RECT 0.000 28.944 0.072 28.968 ;
    END
  END pci_exp_rxp
  PIN pcie_cq_np_req
    DIRECTION INPUT ;
    USE SIGNAL ;
    PORT
      LAYER M4 ;
      RECT 0.000 29.088 0.072 29.112 ;
    END
  END pcie_cq_np_req
  PIN pcie_perstn1_in
    DIRECTION INPUT ;
    USE SIGNAL ;
    PORT
      LAYER M4 ;
      RECT 0.000 29.232 0.072 29.256 ;
    END
  END pcie_perstn1_in
  PIN s_axis_cc_tdata[0]
    DIRECTION INPUT ;
    USE SIGNAL ;
    PORT
      LAYER M4 ;
      RECT 0.000 29.376 0.072 29.400 ;
    END
  END s_axis_cc_tdata[0]
  PIN s_axis_cc_tdata[1]
    DIRECTION INPUT ;
    USE SIGNAL ;
    PORT
      LAYER M4 ;
      RECT 0.000 29.520 0.072 29.544 ;
    END
  END s_axis_cc_tdata[1]
  PIN s_axis_cc_tdata[2]
    DIRECTION INPUT ;
    USE SIGNAL ;
    PORT
      LAYER M4 ;
      RECT 0.000 29.664 0.072 29.688 ;
    END
  END s_axis_cc_tdata[2]
  PIN s_axis_cc_tdata[3]
    DIRECTION INPUT ;
    USE SIGNAL ;
    PORT
      LAYER M4 ;
      RECT 0.000 29.808 0.072 29.832 ;
    END
  END s_axis_cc_tdata[3]
  PIN s_axis_cc_tdata[4]
    DIRECTION INPUT ;
    USE SIGNAL ;
    PORT
      LAYER M4 ;
      RECT 0.000 29.952 0.072 29.976 ;
    END
  END s_axis_cc_tdata[4]
  PIN s_axis_cc_tdata[5]
    DIRECTION INPUT ;
    USE SIGNAL ;
    PORT
      LAYER M4 ;
      RECT 0.000 30.096 0.072 30.120 ;
    END
  END s_axis_cc_tdata[5]
  PIN s_axis_cc_tdata[6]
    DIRECTION INPUT ;
    USE SIGNAL ;
    PORT
      LAYER M4 ;
      RECT 0.000 30.240 0.072 30.264 ;
    END
  END s_axis_cc_tdata[6]
  PIN s_axis_cc_tdata[7]
    DIRECTION INPUT ;
    USE SIGNAL ;
    PORT
      LAYER M4 ;
      RECT 0.000 30.384 0.072 30.408 ;
    END
  END s_axis_cc_tdata[7]
  PIN s_axis_cc_tdata[8]
    DIRECTION INPUT ;
    USE SIGNAL ;
    PORT
      LAYER M4 ;
      RECT 0.000 30.528 0.072 30.552 ;
    END
  END s_axis_cc_tdata[8]
  PIN s_axis_cc_tdata[9]
    DIRECTION INPUT ;
    USE SIGNAL ;
    PORT
      LAYER M4 ;
      RECT 0.000 30.672 0.072 30.696 ;
    END
  END s_axis_cc_tdata[9]
  PIN s_axis_cc_tdata[10]
    DIRECTION INPUT ;
    USE SIGNAL ;
    PORT
      LAYER M4 ;
      RECT 0.000 30.816 0.072 30.840 ;
    END
  END s_axis_cc_tdata[10]
  PIN s_axis_cc_tdata[11]
    DIRECTION INPUT ;
    USE SIGNAL ;
    PORT
      LAYER M4 ;
      RECT 0.000 30.960 0.072 30.984 ;
    END
  END s_axis_cc_tdata[11]
  PIN s_axis_cc_tdata[12]
    DIRECTION INPUT ;
    USE SIGNAL ;
    PORT
      LAYER M4 ;
      RECT 0.000 31.104 0.072 31.128 ;
    END
  END s_axis_cc_tdata[12]
  PIN s_axis_cc_tdata[13]
    DIRECTION INPUT ;
    USE SIGNAL ;
    PORT
      LAYER M4 ;
      RECT 0.000 31.248 0.072 31.272 ;
    END
  END s_axis_cc_tdata[13]
  PIN s_axis_cc_tdata[14]
    DIRECTION INPUT ;
    USE SIGNAL ;
    PORT
      LAYER M4 ;
      RECT 0.000 31.392 0.072 31.416 ;
    END
  END s_axis_cc_tdata[14]
  PIN s_axis_cc_tdata[15]
    DIRECTION INPUT ;
    USE SIGNAL ;
    PORT
      LAYER M4 ;
      RECT 0.000 31.536 0.072 31.560 ;
    END
  END s_axis_cc_tdata[15]
  PIN s_axis_cc_tdata[16]
    DIRECTION INPUT ;
    USE SIGNAL ;
    PORT
      LAYER M4 ;
      RECT 0.000 31.680 0.072 31.704 ;
    END
  END s_axis_cc_tdata[16]
  PIN s_axis_cc_tdata[17]
    DIRECTION INPUT ;
    USE SIGNAL ;
    PORT
      LAYER M4 ;
      RECT 0.000 31.824 0.072 31.848 ;
    END
  END s_axis_cc_tdata[17]
  PIN s_axis_cc_tdata[18]
    DIRECTION INPUT ;
    USE SIGNAL ;
    PORT
      LAYER M4 ;
      RECT 0.000 31.968 0.072 31.992 ;
    END
  END s_axis_cc_tdata[18]
  PIN s_axis_cc_tdata[19]
    DIRECTION INPUT ;
    USE SIGNAL ;
    PORT
      LAYER M4 ;
      RECT 0.000 32.112 0.072 32.136 ;
    END
  END s_axis_cc_tdata[19]
  PIN s_axis_cc_tdata[20]
    DIRECTION INPUT ;
    USE SIGNAL ;
    PORT
      LAYER M4 ;
      RECT 0.000 32.256 0.072 32.280 ;
    END
  END s_axis_cc_tdata[20]
  PIN s_axis_cc_tdata[21]
    DIRECTION INPUT ;
    USE SIGNAL ;
    PORT
      LAYER M4 ;
      RECT 0.000 32.400 0.072 32.424 ;
    END
  END s_axis_cc_tdata[21]
  PIN s_axis_cc_tdata[22]
    DIRECTION INPUT ;
    USE SIGNAL ;
    PORT
      LAYER M4 ;
      RECT 0.000 32.544 0.072 32.568 ;
    END
  END s_axis_cc_tdata[22]
  PIN s_axis_cc_tdata[23]
    DIRECTION INPUT ;
    USE SIGNAL ;
    PORT
      LAYER M4 ;
      RECT 0.000 32.688 0.072 32.712 ;
    END
  END s_axis_cc_tdata[23]
  PIN s_axis_cc_tdata[24]
    DIRECTION INPUT ;
    USE SIGNAL ;
    PORT
      LAYER M4 ;
      RECT 0.000 32.832 0.072 32.856 ;
    END
  END s_axis_cc_tdata[24]
  PIN s_axis_cc_tdata[25]
    DIRECTION INPUT ;
    USE SIGNAL ;
    PORT
      LAYER M4 ;
      RECT 0.000 32.976 0.072 33.000 ;
    END
  END s_axis_cc_tdata[25]
  PIN s_axis_cc_tdata[26]
    DIRECTION INPUT ;
    USE SIGNAL ;
    PORT
      LAYER M4 ;
      RECT 0.000 33.120 0.072 33.144 ;
    END
  END s_axis_cc_tdata[26]
  PIN s_axis_cc_tdata[27]
    DIRECTION INPUT ;
    USE SIGNAL ;
    PORT
      LAYER M4 ;
      RECT 0.000 33.264 0.072 33.288 ;
    END
  END s_axis_cc_tdata[27]
  PIN s_axis_cc_tdata[28]
    DIRECTION INPUT ;
    USE SIGNAL ;
    PORT
      LAYER M4 ;
      RECT 0.000 33.408 0.072 33.432 ;
    END
  END s_axis_cc_tdata[28]
  PIN s_axis_cc_tdata[29]
    DIRECTION INPUT ;
    USE SIGNAL ;
    PORT
      LAYER M4 ;
      RECT 0.000 33.552 0.072 33.576 ;
    END
  END s_axis_cc_tdata[29]
  PIN s_axis_cc_tdata[30]
    DIRECTION INPUT ;
    USE SIGNAL ;
    PORT
      LAYER M4 ;
      RECT 0.000 33.696 0.072 33.720 ;
    END
  END s_axis_cc_tdata[30]
  PIN s_axis_cc_tdata[31]
    DIRECTION INPUT ;
    USE SIGNAL ;
    PORT
      LAYER M4 ;
      RECT 0.000 33.840 0.072 33.864 ;
    END
  END s_axis_cc_tdata[31]
  PIN s_axis_cc_tdata[32]
    DIRECTION INPUT ;
    USE SIGNAL ;
    PORT
      LAYER M4 ;
      RECT 0.000 33.984 0.072 34.008 ;
    END
  END s_axis_cc_tdata[32]
  PIN s_axis_cc_tdata[33]
    DIRECTION INPUT ;
    USE SIGNAL ;
    PORT
      LAYER M4 ;
      RECT 0.000 34.128 0.072 34.152 ;
    END
  END s_axis_cc_tdata[33]
  PIN s_axis_cc_tdata[34]
    DIRECTION INPUT ;
    USE SIGNAL ;
    PORT
      LAYER M4 ;
      RECT 0.000 34.272 0.072 34.296 ;
    END
  END s_axis_cc_tdata[34]
  PIN s_axis_cc_tdata[35]
    DIRECTION INPUT ;
    USE SIGNAL ;
    PORT
      LAYER M4 ;
      RECT 0.000 34.416 0.072 34.440 ;
    END
  END s_axis_cc_tdata[35]
  PIN s_axis_cc_tdata[36]
    DIRECTION INPUT ;
    USE SIGNAL ;
    PORT
      LAYER M4 ;
      RECT 0.000 34.560 0.072 34.584 ;
    END
  END s_axis_cc_tdata[36]
  PIN s_axis_cc_tdata[37]
    DIRECTION INPUT ;
    USE SIGNAL ;
    PORT
      LAYER M4 ;
      RECT 0.000 34.704 0.072 34.728 ;
    END
  END s_axis_cc_tdata[37]
  PIN s_axis_cc_tdata[38]
    DIRECTION INPUT ;
    USE SIGNAL ;
    PORT
      LAYER M4 ;
      RECT 0.000 34.848 0.072 34.872 ;
    END
  END s_axis_cc_tdata[38]
  PIN s_axis_cc_tdata[39]
    DIRECTION INPUT ;
    USE SIGNAL ;
    PORT
      LAYER M4 ;
      RECT 0.000 34.992 0.072 35.016 ;
    END
  END s_axis_cc_tdata[39]
  PIN s_axis_cc_tdata[40]
    DIRECTION INPUT ;
    USE SIGNAL ;
    PORT
      LAYER M4 ;
      RECT 0.000 35.136 0.072 35.160 ;
    END
  END s_axis_cc_tdata[40]
  PIN s_axis_cc_tdata[41]
    DIRECTION INPUT ;
    USE SIGNAL ;
    PORT
      LAYER M4 ;
      RECT 0.000 35.280 0.072 35.304 ;
    END
  END s_axis_cc_tdata[41]
  PIN s_axis_cc_tdata[42]
    DIRECTION INPUT ;
    USE SIGNAL ;
    PORT
      LAYER M4 ;
      RECT 0.000 35.424 0.072 35.448 ;
    END
  END s_axis_cc_tdata[42]
  PIN s_axis_cc_tdata[43]
    DIRECTION INPUT ;
    USE SIGNAL ;
    PORT
      LAYER M4 ;
      RECT 0.000 35.568 0.072 35.592 ;
    END
  END s_axis_cc_tdata[43]
  PIN s_axis_cc_tdata[44]
    DIRECTION INPUT ;
    USE SIGNAL ;
    PORT
      LAYER M4 ;
      RECT 0.000 35.712 0.072 35.736 ;
    END
  END s_axis_cc_tdata[44]
  PIN s_axis_cc_tdata[45]
    DIRECTION INPUT ;
    USE SIGNAL ;
    PORT
      LAYER M4 ;
      RECT 0.000 35.856 0.072 35.880 ;
    END
  END s_axis_cc_tdata[45]
  PIN s_axis_cc_tdata[46]
    DIRECTION INPUT ;
    USE SIGNAL ;
    PORT
      LAYER M4 ;
      RECT 0.000 36.000 0.072 36.024 ;
    END
  END s_axis_cc_tdata[46]
  PIN s_axis_cc_tdata[47]
    DIRECTION INPUT ;
    USE SIGNAL ;
    PORT
      LAYER M4 ;
      RECT 0.000 36.144 0.072 36.168 ;
    END
  END s_axis_cc_tdata[47]
  PIN s_axis_cc_tdata[48]
    DIRECTION INPUT ;
    USE SIGNAL ;
    PORT
      LAYER M4 ;
      RECT 0.000 36.288 0.072 36.312 ;
    END
  END s_axis_cc_tdata[48]
  PIN s_axis_cc_tdata[49]
    DIRECTION INPUT ;
    USE SIGNAL ;
    PORT
      LAYER M4 ;
      RECT 0.000 36.432 0.072 36.456 ;
    END
  END s_axis_cc_tdata[49]
  PIN s_axis_cc_tdata[50]
    DIRECTION INPUT ;
    USE SIGNAL ;
    PORT
      LAYER M4 ;
      RECT 0.000 36.576 0.072 36.600 ;
    END
  END s_axis_cc_tdata[50]
  PIN s_axis_cc_tdata[51]
    DIRECTION INPUT ;
    USE SIGNAL ;
    PORT
      LAYER M4 ;
      RECT 0.000 36.720 0.072 36.744 ;
    END
  END s_axis_cc_tdata[51]
  PIN s_axis_cc_tdata[52]
    DIRECTION INPUT ;
    USE SIGNAL ;
    PORT
      LAYER M4 ;
      RECT 0.000 36.864 0.072 36.888 ;
    END
  END s_axis_cc_tdata[52]
  PIN s_axis_cc_tdata[53]
    DIRECTION INPUT ;
    USE SIGNAL ;
    PORT
      LAYER M4 ;
      RECT 0.000 37.008 0.072 37.032 ;
    END
  END s_axis_cc_tdata[53]
  PIN s_axis_cc_tdata[54]
    DIRECTION INPUT ;
    USE SIGNAL ;
    PORT
      LAYER M4 ;
      RECT 0.000 37.152 0.072 37.176 ;
    END
  END s_axis_cc_tdata[54]
  PIN s_axis_cc_tdata[55]
    DIRECTION INPUT ;
    USE SIGNAL ;
    PORT
      LAYER M4 ;
      RECT 0.000 37.296 0.072 37.320 ;
    END
  END s_axis_cc_tdata[55]
  PIN s_axis_cc_tdata[56]
    DIRECTION INPUT ;
    USE SIGNAL ;
    PORT
      LAYER M4 ;
      RECT 0.000 37.440 0.072 37.464 ;
    END
  END s_axis_cc_tdata[56]
  PIN s_axis_cc_tdata[57]
    DIRECTION INPUT ;
    USE SIGNAL ;
    PORT
      LAYER M4 ;
      RECT 0.000 37.584 0.072 37.608 ;
    END
  END s_axis_cc_tdata[57]
  PIN s_axis_cc_tdata[58]
    DIRECTION INPUT ;
    USE SIGNAL ;
    PORT
      LAYER M4 ;
      RECT 0.000 37.728 0.072 37.752 ;
    END
  END s_axis_cc_tdata[58]
  PIN s_axis_cc_tdata[59]
    DIRECTION INPUT ;
    USE SIGNAL ;
    PORT
      LAYER M4 ;
      RECT 0.000 37.872 0.072 37.896 ;
    END
  END s_axis_cc_tdata[59]
  PIN s_axis_cc_tdata[60]
    DIRECTION INPUT ;
    USE SIGNAL ;
    PORT
      LAYER M4 ;
      RECT 0.000 38.016 0.072 38.040 ;
    END
  END s_axis_cc_tdata[60]
  PIN s_axis_cc_tdata[61]
    DIRECTION INPUT ;
    USE SIGNAL ;
    PORT
      LAYER M4 ;
      RECT 0.000 38.160 0.072 38.184 ;
    END
  END s_axis_cc_tdata[61]
  PIN s_axis_cc_tdata[62]
    DIRECTION INPUT ;
    USE SIGNAL ;
    PORT
      LAYER M4 ;
      RECT 0.000 38.304 0.072 38.328 ;
    END
  END s_axis_cc_tdata[62]
  PIN s_axis_cc_tdata[63]
    DIRECTION INPUT ;
    USE SIGNAL ;
    PORT
      LAYER M4 ;
      RECT 0.000 38.448 0.072 38.472 ;
    END
  END s_axis_cc_tdata[63]
  PIN s_axis_cc_tdata[64]
    DIRECTION INPUT ;
    USE SIGNAL ;
    PORT
      LAYER M4 ;
      RECT 0.000 38.592 0.072 38.616 ;
    END
  END s_axis_cc_tdata[64]
  PIN s_axis_cc_tdata[65]
    DIRECTION INPUT ;
    USE SIGNAL ;
    PORT
      LAYER M4 ;
      RECT 0.000 38.736 0.072 38.760 ;
    END
  END s_axis_cc_tdata[65]
  PIN s_axis_cc_tdata[66]
    DIRECTION INPUT ;
    USE SIGNAL ;
    PORT
      LAYER M4 ;
      RECT 0.000 38.880 0.072 38.904 ;
    END
  END s_axis_cc_tdata[66]
  PIN s_axis_cc_tdata[67]
    DIRECTION INPUT ;
    USE SIGNAL ;
    PORT
      LAYER M4 ;
      RECT 0.000 39.024 0.072 39.048 ;
    END
  END s_axis_cc_tdata[67]
  PIN s_axis_cc_tdata[68]
    DIRECTION INPUT ;
    USE SIGNAL ;
    PORT
      LAYER M4 ;
      RECT 0.000 39.168 0.072 39.192 ;
    END
  END s_axis_cc_tdata[68]
  PIN s_axis_cc_tdata[69]
    DIRECTION INPUT ;
    USE SIGNAL ;
    PORT
      LAYER M4 ;
      RECT 0.000 39.312 0.072 39.336 ;
    END
  END s_axis_cc_tdata[69]
  PIN s_axis_cc_tdata[70]
    DIRECTION INPUT ;
    USE SIGNAL ;
    PORT
      LAYER M4 ;
      RECT 0.000 39.456 0.072 39.480 ;
    END
  END s_axis_cc_tdata[70]
  PIN s_axis_cc_tdata[71]
    DIRECTION INPUT ;
    USE SIGNAL ;
    PORT
      LAYER M4 ;
      RECT 0.000 39.600 0.072 39.624 ;
    END
  END s_axis_cc_tdata[71]
  PIN s_axis_cc_tdata[72]
    DIRECTION INPUT ;
    USE SIGNAL ;
    PORT
      LAYER M4 ;
      RECT 0.000 39.744 0.072 39.768 ;
    END
  END s_axis_cc_tdata[72]
  PIN s_axis_cc_tdata[73]
    DIRECTION INPUT ;
    USE SIGNAL ;
    PORT
      LAYER M4 ;
      RECT 0.000 39.888 0.072 39.912 ;
    END
  END s_axis_cc_tdata[73]
  PIN s_axis_cc_tdata[74]
    DIRECTION INPUT ;
    USE SIGNAL ;
    PORT
      LAYER M4 ;
      RECT 0.000 40.032 0.072 40.056 ;
    END
  END s_axis_cc_tdata[74]
  PIN s_axis_cc_tdata[75]
    DIRECTION INPUT ;
    USE SIGNAL ;
    PORT
      LAYER M4 ;
      RECT 0.000 40.176 0.072 40.200 ;
    END
  END s_axis_cc_tdata[75]
  PIN s_axis_cc_tdata[76]
    DIRECTION INPUT ;
    USE SIGNAL ;
    PORT
      LAYER M4 ;
      RECT 0.000 40.320 0.072 40.344 ;
    END
  END s_axis_cc_tdata[76]
  PIN s_axis_cc_tdata[77]
    DIRECTION INPUT ;
    USE SIGNAL ;
    PORT
      LAYER M4 ;
      RECT 0.000 40.464 0.072 40.488 ;
    END
  END s_axis_cc_tdata[77]
  PIN s_axis_cc_tdata[78]
    DIRECTION INPUT ;
    USE SIGNAL ;
    PORT
      LAYER M4 ;
      RECT 0.000 40.608 0.072 40.632 ;
    END
  END s_axis_cc_tdata[78]
  PIN s_axis_cc_tdata[79]
    DIRECTION INPUT ;
    USE SIGNAL ;
    PORT
      LAYER M4 ;
      RECT 0.000 40.752 0.072 40.776 ;
    END
  END s_axis_cc_tdata[79]
  PIN s_axis_cc_tdata[80]
    DIRECTION INPUT ;
    USE SIGNAL ;
    PORT
      LAYER M4 ;
      RECT 0.000 40.896 0.072 40.920 ;
    END
  END s_axis_cc_tdata[80]
  PIN s_axis_cc_tdata[81]
    DIRECTION INPUT ;
    USE SIGNAL ;
    PORT
      LAYER M4 ;
      RECT 0.000 41.040 0.072 41.064 ;
    END
  END s_axis_cc_tdata[81]
  PIN s_axis_cc_tdata[82]
    DIRECTION INPUT ;
    USE SIGNAL ;
    PORT
      LAYER M4 ;
      RECT 0.000 41.184 0.072 41.208 ;
    END
  END s_axis_cc_tdata[82]
  PIN s_axis_cc_tdata[83]
    DIRECTION INPUT ;
    USE SIGNAL ;
    PORT
      LAYER M4 ;
      RECT 0.000 41.328 0.072 41.352 ;
    END
  END s_axis_cc_tdata[83]
  PIN s_axis_cc_tdata[84]
    DIRECTION INPUT ;
    USE SIGNAL ;
    PORT
      LAYER M4 ;
      RECT 0.000 41.472 0.072 41.496 ;
    END
  END s_axis_cc_tdata[84]
  PIN s_axis_cc_tdata[85]
    DIRECTION INPUT ;
    USE SIGNAL ;
    PORT
      LAYER M4 ;
      RECT 0.000 41.616 0.072 41.640 ;
    END
  END s_axis_cc_tdata[85]
  PIN s_axis_cc_tdata[86]
    DIRECTION INPUT ;
    USE SIGNAL ;
    PORT
      LAYER M4 ;
      RECT 0.000 41.760 0.072 41.784 ;
    END
  END s_axis_cc_tdata[86]
  PIN s_axis_cc_tdata[87]
    DIRECTION INPUT ;
    USE SIGNAL ;
    PORT
      LAYER M4 ;
      RECT 0.000 41.904 0.072 41.928 ;
    END
  END s_axis_cc_tdata[87]
  PIN s_axis_cc_tdata[88]
    DIRECTION INPUT ;
    USE SIGNAL ;
    PORT
      LAYER M4 ;
      RECT 0.000 42.048 0.072 42.072 ;
    END
  END s_axis_cc_tdata[88]
  PIN s_axis_cc_tdata[89]
    DIRECTION INPUT ;
    USE SIGNAL ;
    PORT
      LAYER M4 ;
      RECT 0.000 42.192 0.072 42.216 ;
    END
  END s_axis_cc_tdata[89]
  PIN s_axis_cc_tdata[90]
    DIRECTION INPUT ;
    USE SIGNAL ;
    PORT
      LAYER M4 ;
      RECT 0.000 42.336 0.072 42.360 ;
    END
  END s_axis_cc_tdata[90]
  PIN s_axis_cc_tdata[91]
    DIRECTION INPUT ;
    USE SIGNAL ;
    PORT
      LAYER M4 ;
      RECT 0.000 42.480 0.072 42.504 ;
    END
  END s_axis_cc_tdata[91]
  PIN s_axis_cc_tdata[92]
    DIRECTION INPUT ;
    USE SIGNAL ;
    PORT
      LAYER M4 ;
      RECT 0.000 42.624 0.072 42.648 ;
    END
  END s_axis_cc_tdata[92]
  PIN s_axis_cc_tdata[93]
    DIRECTION INPUT ;
    USE SIGNAL ;
    PORT
      LAYER M4 ;
      RECT 0.000 42.768 0.072 42.792 ;
    END
  END s_axis_cc_tdata[93]
  PIN s_axis_cc_tdata[94]
    DIRECTION INPUT ;
    USE SIGNAL ;
    PORT
      LAYER M4 ;
      RECT 0.000 42.912 0.072 42.936 ;
    END
  END s_axis_cc_tdata[94]
  PIN s_axis_cc_tdata[95]
    DIRECTION INPUT ;
    USE SIGNAL ;
    PORT
      LAYER M4 ;
      RECT 0.000 43.056 0.072 43.080 ;
    END
  END s_axis_cc_tdata[95]
  PIN s_axis_cc_tdata[96]
    DIRECTION INPUT ;
    USE SIGNAL ;
    PORT
      LAYER M4 ;
      RECT 0.000 43.200 0.072 43.224 ;
    END
  END s_axis_cc_tdata[96]
  PIN s_axis_cc_tdata[97]
    DIRECTION INPUT ;
    USE SIGNAL ;
    PORT
      LAYER M4 ;
      RECT 0.000 43.344 0.072 43.368 ;
    END
  END s_axis_cc_tdata[97]
  PIN s_axis_cc_tdata[98]
    DIRECTION INPUT ;
    USE SIGNAL ;
    PORT
      LAYER M4 ;
      RECT 0.000 43.488 0.072 43.512 ;
    END
  END s_axis_cc_tdata[98]
  PIN s_axis_cc_tdata[99]
    DIRECTION INPUT ;
    USE SIGNAL ;
    PORT
      LAYER M4 ;
      RECT 0.000 43.632 0.072 43.656 ;
    END
  END s_axis_cc_tdata[99]
  PIN s_axis_cc_tdata[100]
    DIRECTION INPUT ;
    USE SIGNAL ;
    PORT
      LAYER M4 ;
      RECT 0.000 43.776 0.072 43.800 ;
    END
  END s_axis_cc_tdata[100]
  PIN s_axis_cc_tdata[101]
    DIRECTION INPUT ;
    USE SIGNAL ;
    PORT
      LAYER M4 ;
      RECT 0.000 43.920 0.072 43.944 ;
    END
  END s_axis_cc_tdata[101]
  PIN s_axis_cc_tdata[102]
    DIRECTION INPUT ;
    USE SIGNAL ;
    PORT
      LAYER M4 ;
      RECT 0.000 44.064 0.072 44.088 ;
    END
  END s_axis_cc_tdata[102]
  PIN s_axis_cc_tdata[103]
    DIRECTION INPUT ;
    USE SIGNAL ;
    PORT
      LAYER M4 ;
      RECT 0.000 44.208 0.072 44.232 ;
    END
  END s_axis_cc_tdata[103]
  PIN s_axis_cc_tdata[104]
    DIRECTION INPUT ;
    USE SIGNAL ;
    PORT
      LAYER M4 ;
      RECT 0.000 44.352 0.072 44.376 ;
    END
  END s_axis_cc_tdata[104]
  PIN s_axis_cc_tdata[105]
    DIRECTION INPUT ;
    USE SIGNAL ;
    PORT
      LAYER M4 ;
      RECT 0.000 44.496 0.072 44.520 ;
    END
  END s_axis_cc_tdata[105]
  PIN s_axis_cc_tdata[106]
    DIRECTION INPUT ;
    USE SIGNAL ;
    PORT
      LAYER M4 ;
      RECT 0.000 44.640 0.072 44.664 ;
    END
  END s_axis_cc_tdata[106]
  PIN s_axis_cc_tdata[107]
    DIRECTION INPUT ;
    USE SIGNAL ;
    PORT
      LAYER M4 ;
      RECT 0.000 44.784 0.072 44.808 ;
    END
  END s_axis_cc_tdata[107]
  PIN s_axis_cc_tdata[108]
    DIRECTION INPUT ;
    USE SIGNAL ;
    PORT
      LAYER M4 ;
      RECT 0.000 44.928 0.072 44.952 ;
    END
  END s_axis_cc_tdata[108]
  PIN s_axis_cc_tdata[109]
    DIRECTION INPUT ;
    USE SIGNAL ;
    PORT
      LAYER M4 ;
      RECT 0.000 45.072 0.072 45.096 ;
    END
  END s_axis_cc_tdata[109]
  PIN s_axis_cc_tdata[110]
    DIRECTION INPUT ;
    USE SIGNAL ;
    PORT
      LAYER M4 ;
      RECT 0.000 45.216 0.072 45.240 ;
    END
  END s_axis_cc_tdata[110]
  PIN s_axis_cc_tdata[111]
    DIRECTION INPUT ;
    USE SIGNAL ;
    PORT
      LAYER M4 ;
      RECT 0.000 45.360 0.072 45.384 ;
    END
  END s_axis_cc_tdata[111]
  PIN s_axis_cc_tdata[112]
    DIRECTION INPUT ;
    USE SIGNAL ;
    PORT
      LAYER M4 ;
      RECT 0.000 45.504 0.072 45.528 ;
    END
  END s_axis_cc_tdata[112]
  PIN s_axis_cc_tdata[113]
    DIRECTION INPUT ;
    USE SIGNAL ;
    PORT
      LAYER M4 ;
      RECT 0.000 45.648 0.072 45.672 ;
    END
  END s_axis_cc_tdata[113]
  PIN s_axis_cc_tdata[114]
    DIRECTION INPUT ;
    USE SIGNAL ;
    PORT
      LAYER M4 ;
      RECT 0.000 45.792 0.072 45.816 ;
    END
  END s_axis_cc_tdata[114]
  PIN s_axis_cc_tdata[115]
    DIRECTION INPUT ;
    USE SIGNAL ;
    PORT
      LAYER M4 ;
      RECT 0.000 45.936 0.072 45.960 ;
    END
  END s_axis_cc_tdata[115]
  PIN s_axis_cc_tdata[116]
    DIRECTION INPUT ;
    USE SIGNAL ;
    PORT
      LAYER M4 ;
      RECT 0.000 46.080 0.072 46.104 ;
    END
  END s_axis_cc_tdata[116]
  PIN s_axis_cc_tdata[117]
    DIRECTION INPUT ;
    USE SIGNAL ;
    PORT
      LAYER M4 ;
      RECT 0.000 46.224 0.072 46.248 ;
    END
  END s_axis_cc_tdata[117]
  PIN s_axis_cc_tdata[118]
    DIRECTION INPUT ;
    USE SIGNAL ;
    PORT
      LAYER M4 ;
      RECT 0.000 46.368 0.072 46.392 ;
    END
  END s_axis_cc_tdata[118]
  PIN s_axis_cc_tdata[119]
    DIRECTION INPUT ;
    USE SIGNAL ;
    PORT
      LAYER M4 ;
      RECT 0.000 46.512 0.072 46.536 ;
    END
  END s_axis_cc_tdata[119]
  PIN s_axis_cc_tdata[120]
    DIRECTION INPUT ;
    USE SIGNAL ;
    PORT
      LAYER M4 ;
      RECT 0.000 46.656 0.072 46.680 ;
    END
  END s_axis_cc_tdata[120]
  PIN s_axis_cc_tdata[121]
    DIRECTION INPUT ;
    USE SIGNAL ;
    PORT
      LAYER M4 ;
      RECT 0.000 46.800 0.072 46.824 ;
    END
  END s_axis_cc_tdata[121]
  PIN s_axis_cc_tdata[122]
    DIRECTION INPUT ;
    USE SIGNAL ;
    PORT
      LAYER M4 ;
      RECT 0.000 46.944 0.072 46.968 ;
    END
  END s_axis_cc_tdata[122]
  PIN s_axis_cc_tdata[123]
    DIRECTION INPUT ;
    USE SIGNAL ;
    PORT
      LAYER M4 ;
      RECT 0.000 47.088 0.072 47.112 ;
    END
  END s_axis_cc_tdata[123]
  PIN s_axis_cc_tdata[124]
    DIRECTION INPUT ;
    USE SIGNAL ;
    PORT
      LAYER M4 ;
      RECT 0.000 47.232 0.072 47.256 ;
    END
  END s_axis_cc_tdata[124]
  PIN s_axis_cc_tdata[125]
    DIRECTION INPUT ;
    USE SIGNAL ;
    PORT
      LAYER M4 ;
      RECT 0.000 47.376 0.072 47.400 ;
    END
  END s_axis_cc_tdata[125]
  PIN s_axis_cc_tdata[126]
    DIRECTION INPUT ;
    USE SIGNAL ;
    PORT
      LAYER M4 ;
      RECT 0.000 47.520 0.072 47.544 ;
    END
  END s_axis_cc_tdata[126]
  PIN s_axis_cc_tdata[127]
    DIRECTION INPUT ;
    USE SIGNAL ;
    PORT
      LAYER M4 ;
      RECT 0.000 47.664 0.072 47.688 ;
    END
  END s_axis_cc_tdata[127]
  PIN s_axis_cc_tkeep[0]
    DIRECTION INPUT ;
    USE SIGNAL ;
    PORT
      LAYER M4 ;
      RECT 0.000 47.808 0.072 47.832 ;
    END
  END s_axis_cc_tkeep[0]
  PIN s_axis_cc_tkeep[1]
    DIRECTION INPUT ;
    USE SIGNAL ;
    PORT
      LAYER M4 ;
      RECT 0.000 47.952 0.072 47.976 ;
    END
  END s_axis_cc_tkeep[1]
  PIN s_axis_cc_tkeep[2]
    DIRECTION INPUT ;
    USE SIGNAL ;
    PORT
      LAYER M4 ;
      RECT 0.000 48.096 0.072 48.120 ;
    END
  END s_axis_cc_tkeep[2]
  PIN s_axis_cc_tkeep[3]
    DIRECTION INPUT ;
    USE SIGNAL ;
    PORT
      LAYER M4 ;
      RECT 0.000 48.240 0.072 48.264 ;
    END
  END s_axis_cc_tkeep[3]
  PIN s_axis_cc_tlast
    DIRECTION INPUT ;
    USE SIGNAL ;
    PORT
      LAYER M4 ;
      RECT 0.000 48.384 0.072 48.408 ;
    END
  END s_axis_cc_tlast
  PIN s_axis_cc_tuser[0]
    DIRECTION INPUT ;
    USE SIGNAL ;
    PORT
      LAYER M4 ;
      RECT 0.000 48.528 0.072 48.552 ;
    END
  END s_axis_cc_tuser[0]
  PIN s_axis_cc_tuser[1]
    DIRECTION INPUT ;
    USE SIGNAL ;
    PORT
      LAYER M4 ;
      RECT 0.000 48.672 0.072 48.696 ;
    END
  END s_axis_cc_tuser[1]
  PIN s_axis_cc_tuser[2]
    DIRECTION INPUT ;
    USE SIGNAL ;
    PORT
      LAYER M4 ;
      RECT 0.000 48.816 0.072 48.840 ;
    END
  END s_axis_cc_tuser[2]
  PIN s_axis_cc_tuser[3]
    DIRECTION INPUT ;
    USE SIGNAL ;
    PORT
      LAYER M4 ;
      RECT 0.000 48.960 0.072 48.984 ;
    END
  END s_axis_cc_tuser[3]
  PIN s_axis_cc_tuser[4]
    DIRECTION INPUT ;
    USE SIGNAL ;
    PORT
      LAYER M4 ;
      RECT 0.000 49.104 0.072 49.128 ;
    END
  END s_axis_cc_tuser[4]
  PIN s_axis_cc_tuser[5]
    DIRECTION INPUT ;
    USE SIGNAL ;
    PORT
      LAYER M4 ;
      RECT 0.000 49.248 0.072 49.272 ;
    END
  END s_axis_cc_tuser[5]
  PIN s_axis_cc_tuser[6]
    DIRECTION INPUT ;
    USE SIGNAL ;
    PORT
      LAYER M4 ;
      RECT 0.000 49.392 0.072 49.416 ;
    END
  END s_axis_cc_tuser[6]
  PIN s_axis_cc_tuser[7]
    DIRECTION INPUT ;
    USE SIGNAL ;
    PORT
      LAYER M4 ;
      RECT 0.000 49.536 0.072 49.560 ;
    END
  END s_axis_cc_tuser[7]
  PIN s_axis_cc_tuser[8]
    DIRECTION INPUT ;
    USE SIGNAL ;
    PORT
      LAYER M4 ;
      RECT 0.000 49.680 0.072 49.704 ;
    END
  END s_axis_cc_tuser[8]
  PIN s_axis_cc_tuser[9]
    DIRECTION INPUT ;
    USE SIGNAL ;
    PORT
      LAYER M4 ;
      RECT 0.000 49.824 0.072 49.848 ;
    END
  END s_axis_cc_tuser[9]
  PIN s_axis_cc_tuser[10]
    DIRECTION INPUT ;
    USE SIGNAL ;
    PORT
      LAYER M4 ;
      RECT 0.000 49.968 0.072 49.992 ;
    END
  END s_axis_cc_tuser[10]
  PIN s_axis_cc_tuser[11]
    DIRECTION INPUT ;
    USE SIGNAL ;
    PORT
      LAYER M4 ;
      RECT 0.000 50.112 0.072 50.136 ;
    END
  END s_axis_cc_tuser[11]
  PIN s_axis_cc_tuser[12]
    DIRECTION INPUT ;
    USE SIGNAL ;
    PORT
      LAYER M4 ;
      RECT 0.000 50.256 0.072 50.280 ;
    END
  END s_axis_cc_tuser[12]
  PIN s_axis_cc_tuser[13]
    DIRECTION INPUT ;
    USE SIGNAL ;
    PORT
      LAYER M4 ;
      RECT 0.000 50.400 0.072 50.424 ;
    END
  END s_axis_cc_tuser[13]
  PIN s_axis_cc_tuser[14]
    DIRECTION INPUT ;
    USE SIGNAL ;
    PORT
      LAYER M4 ;
      RECT 0.000 50.544 0.072 50.568 ;
    END
  END s_axis_cc_tuser[14]
  PIN s_axis_cc_tuser[15]
    DIRECTION INPUT ;
    USE SIGNAL ;
    PORT
      LAYER M4 ;
      RECT 0.000 50.688 0.072 50.712 ;
    END
  END s_axis_cc_tuser[15]
  PIN s_axis_cc_tuser[16]
    DIRECTION INPUT ;
    USE SIGNAL ;
    PORT
      LAYER M4 ;
      RECT 0.000 50.832 0.072 50.856 ;
    END
  END s_axis_cc_tuser[16]
  PIN s_axis_cc_tuser[17]
    DIRECTION INPUT ;
    USE SIGNAL ;
    PORT
      LAYER M4 ;
      RECT 0.000 50.976 0.072 51.000 ;
    END
  END s_axis_cc_tuser[17]
  PIN s_axis_cc_tuser[18]
    DIRECTION INPUT ;
    USE SIGNAL ;
    PORT
      LAYER M4 ;
      RECT 0.000 51.120 0.072 51.144 ;
    END
  END s_axis_cc_tuser[18]
  PIN s_axis_cc_tuser[19]
    DIRECTION INPUT ;
    USE SIGNAL ;
    PORT
      LAYER M4 ;
      RECT 0.000 51.264 0.072 51.288 ;
    END
  END s_axis_cc_tuser[19]
  PIN s_axis_cc_tuser[20]
    DIRECTION INPUT ;
    USE SIGNAL ;
    PORT
      LAYER M4 ;
      RECT 0.000 51.408 0.072 51.432 ;
    END
  END s_axis_cc_tuser[20]
  PIN s_axis_cc_tuser[21]
    DIRECTION INPUT ;
    USE SIGNAL ;
    PORT
      LAYER M4 ;
      RECT 0.000 51.552 0.072 51.576 ;
    END
  END s_axis_cc_tuser[21]
  PIN s_axis_cc_tuser[22]
    DIRECTION INPUT ;
    USE SIGNAL ;
    PORT
      LAYER M4 ;
      RECT 0.000 51.696 0.072 51.720 ;
    END
  END s_axis_cc_tuser[22]
  PIN s_axis_cc_tuser[23]
    DIRECTION INPUT ;
    USE SIGNAL ;
    PORT
      LAYER M4 ;
      RECT 0.000 51.840 0.072 51.864 ;
    END
  END s_axis_cc_tuser[23]
  PIN s_axis_cc_tuser[24]
    DIRECTION INPUT ;
    USE SIGNAL ;
    PORT
      LAYER M4 ;
      RECT 0.000 51.984 0.072 52.008 ;
    END
  END s_axis_cc_tuser[24]
  PIN s_axis_cc_tuser[25]
    DIRECTION INPUT ;
    USE SIGNAL ;
    PORT
      LAYER M4 ;
      RECT 0.000 52.128 0.072 52.152 ;
    END
  END s_axis_cc_tuser[25]
  PIN s_axis_cc_tuser[26]
    DIRECTION INPUT ;
    USE SIGNAL ;
    PORT
      LAYER M4 ;
      RECT 0.000 52.272 0.072 52.296 ;
    END
  END s_axis_cc_tuser[26]
  PIN s_axis_cc_tuser[27]
    DIRECTION INPUT ;
    USE SIGNAL ;
    PORT
      LAYER M4 ;
      RECT 0.000 52.416 0.072 52.440 ;
    END
  END s_axis_cc_tuser[27]
  PIN s_axis_cc_tuser[28]
    DIRECTION INPUT ;
    USE SIGNAL ;
    PORT
      LAYER M4 ;
      RECT 0.000 52.560 0.072 52.584 ;
    END
  END s_axis_cc_tuser[28]
  PIN s_axis_cc_tuser[29]
    DIRECTION INPUT ;
    USE SIGNAL ;
    PORT
      LAYER M4 ;
      RECT 0.000 52.704 0.072 52.728 ;
    END
  END s_axis_cc_tuser[29]
  PIN s_axis_cc_tuser[30]
    DIRECTION INPUT ;
    USE SIGNAL ;
    PORT
      LAYER M4 ;
      RECT 0.000 52.848 0.072 52.872 ;
    END
  END s_axis_cc_tuser[30]
  PIN s_axis_cc_tuser[31]
    DIRECTION INPUT ;
    USE SIGNAL ;
    PORT
      LAYER M4 ;
      RECT 0.000 52.992 0.072 53.016 ;
    END
  END s_axis_cc_tuser[31]
  PIN s_axis_cc_tuser[32]
    DIRECTION INPUT ;
    USE SIGNAL ;
    PORT
      LAYER M4 ;
      RECT 0.000 53.136 0.072 53.160 ;
    END
  END s_axis_cc_tuser[32]
  PIN s_axis_cc_tvalid
    DIRECTION INPUT ;
    USE SIGNAL ;
    PORT
      LAYER M4 ;
      RECT 0.000 53.280 0.072 53.304 ;
    END
  END s_axis_cc_tvalid
  PIN s_axis_rq_tdata[0]
    DIRECTION INPUT ;
    USE SIGNAL ;
    PORT
      LAYER M4 ;
      RECT 0.000 53.424 0.072 53.448 ;
    END
  END s_axis_rq_tdata[0]
  PIN s_axis_rq_tdata[1]
    DIRECTION INPUT ;
    USE SIGNAL ;
    PORT
      LAYER M4 ;
      RECT 0.000 53.568 0.072 53.592 ;
    END
  END s_axis_rq_tdata[1]
  PIN s_axis_rq_tdata[2]
    DIRECTION INPUT ;
    USE SIGNAL ;
    PORT
      LAYER M4 ;
      RECT 0.000 53.712 0.072 53.736 ;
    END
  END s_axis_rq_tdata[2]
  PIN s_axis_rq_tdata[3]
    DIRECTION INPUT ;
    USE SIGNAL ;
    PORT
      LAYER M4 ;
      RECT 0.000 53.856 0.072 53.880 ;
    END
  END s_axis_rq_tdata[3]
  PIN s_axis_rq_tdata[4]
    DIRECTION INPUT ;
    USE SIGNAL ;
    PORT
      LAYER M4 ;
      RECT 0.000 54.000 0.072 54.024 ;
    END
  END s_axis_rq_tdata[4]
  PIN s_axis_rq_tdata[5]
    DIRECTION INPUT ;
    USE SIGNAL ;
    PORT
      LAYER M4 ;
      RECT 0.000 54.144 0.072 54.168 ;
    END
  END s_axis_rq_tdata[5]
  PIN s_axis_rq_tdata[6]
    DIRECTION INPUT ;
    USE SIGNAL ;
    PORT
      LAYER M4 ;
      RECT 0.000 54.288 0.072 54.312 ;
    END
  END s_axis_rq_tdata[6]
  PIN s_axis_rq_tdata[7]
    DIRECTION INPUT ;
    USE SIGNAL ;
    PORT
      LAYER M4 ;
      RECT 0.000 54.432 0.072 54.456 ;
    END
  END s_axis_rq_tdata[7]
  PIN s_axis_rq_tdata[8]
    DIRECTION INPUT ;
    USE SIGNAL ;
    PORT
      LAYER M4 ;
      RECT 0.000 54.576 0.072 54.600 ;
    END
  END s_axis_rq_tdata[8]
  PIN s_axis_rq_tdata[9]
    DIRECTION INPUT ;
    USE SIGNAL ;
    PORT
      LAYER M4 ;
      RECT 0.000 54.720 0.072 54.744 ;
    END
  END s_axis_rq_tdata[9]
  PIN s_axis_rq_tdata[10]
    DIRECTION INPUT ;
    USE SIGNAL ;
    PORT
      LAYER M4 ;
      RECT 0.000 54.864 0.072 54.888 ;
    END
  END s_axis_rq_tdata[10]
  PIN s_axis_rq_tdata[11]
    DIRECTION INPUT ;
    USE SIGNAL ;
    PORT
      LAYER M4 ;
      RECT 0.000 55.008 0.072 55.032 ;
    END
  END s_axis_rq_tdata[11]
  PIN s_axis_rq_tdata[12]
    DIRECTION INPUT ;
    USE SIGNAL ;
    PORT
      LAYER M4 ;
      RECT 0.000 55.152 0.072 55.176 ;
    END
  END s_axis_rq_tdata[12]
  PIN s_axis_rq_tdata[13]
    DIRECTION INPUT ;
    USE SIGNAL ;
    PORT
      LAYER M4 ;
      RECT 0.000 55.296 0.072 55.320 ;
    END
  END s_axis_rq_tdata[13]
  PIN s_axis_rq_tdata[14]
    DIRECTION INPUT ;
    USE SIGNAL ;
    PORT
      LAYER M4 ;
      RECT 0.000 55.440 0.072 55.464 ;
    END
  END s_axis_rq_tdata[14]
  PIN s_axis_rq_tdata[15]
    DIRECTION INPUT ;
    USE SIGNAL ;
    PORT
      LAYER M4 ;
      RECT 0.000 55.584 0.072 55.608 ;
    END
  END s_axis_rq_tdata[15]
  PIN s_axis_rq_tdata[16]
    DIRECTION INPUT ;
    USE SIGNAL ;
    PORT
      LAYER M4 ;
      RECT 0.000 55.728 0.072 55.752 ;
    END
  END s_axis_rq_tdata[16]
  PIN s_axis_rq_tdata[17]
    DIRECTION INPUT ;
    USE SIGNAL ;
    PORT
      LAYER M4 ;
      RECT 0.000 55.872 0.072 55.896 ;
    END
  END s_axis_rq_tdata[17]
  PIN s_axis_rq_tdata[18]
    DIRECTION INPUT ;
    USE SIGNAL ;
    PORT
      LAYER M4 ;
      RECT 0.000 56.016 0.072 56.040 ;
    END
  END s_axis_rq_tdata[18]
  PIN s_axis_rq_tdata[19]
    DIRECTION INPUT ;
    USE SIGNAL ;
    PORT
      LAYER M4 ;
      RECT 0.000 56.160 0.072 56.184 ;
    END
  END s_axis_rq_tdata[19]
  PIN s_axis_rq_tdata[20]
    DIRECTION INPUT ;
    USE SIGNAL ;
    PORT
      LAYER M4 ;
      RECT 0.000 56.304 0.072 56.328 ;
    END
  END s_axis_rq_tdata[20]
  PIN s_axis_rq_tdata[21]
    DIRECTION INPUT ;
    USE SIGNAL ;
    PORT
      LAYER M4 ;
      RECT 0.000 56.448 0.072 56.472 ;
    END
  END s_axis_rq_tdata[21]
  PIN s_axis_rq_tdata[22]
    DIRECTION INPUT ;
    USE SIGNAL ;
    PORT
      LAYER M4 ;
      RECT 0.000 56.592 0.072 56.616 ;
    END
  END s_axis_rq_tdata[22]
  PIN s_axis_rq_tdata[23]
    DIRECTION INPUT ;
    USE SIGNAL ;
    PORT
      LAYER M4 ;
      RECT 0.000 56.736 0.072 56.760 ;
    END
  END s_axis_rq_tdata[23]
  PIN s_axis_rq_tdata[24]
    DIRECTION INPUT ;
    USE SIGNAL ;
    PORT
      LAYER M4 ;
      RECT 0.000 56.880 0.072 56.904 ;
    END
  END s_axis_rq_tdata[24]
  PIN s_axis_rq_tdata[25]
    DIRECTION INPUT ;
    USE SIGNAL ;
    PORT
      LAYER M4 ;
      RECT 0.000 57.024 0.072 57.048 ;
    END
  END s_axis_rq_tdata[25]
  PIN s_axis_rq_tdata[26]
    DIRECTION INPUT ;
    USE SIGNAL ;
    PORT
      LAYER M4 ;
      RECT 0.000 57.168 0.072 57.192 ;
    END
  END s_axis_rq_tdata[26]
  PIN s_axis_rq_tdata[27]
    DIRECTION INPUT ;
    USE SIGNAL ;
    PORT
      LAYER M4 ;
      RECT 0.000 57.312 0.072 57.336 ;
    END
  END s_axis_rq_tdata[27]
  PIN s_axis_rq_tdata[28]
    DIRECTION INPUT ;
    USE SIGNAL ;
    PORT
      LAYER M4 ;
      RECT 0.000 57.456 0.072 57.480 ;
    END
  END s_axis_rq_tdata[28]
  PIN s_axis_rq_tdata[29]
    DIRECTION INPUT ;
    USE SIGNAL ;
    PORT
      LAYER M4 ;
      RECT 0.000 57.600 0.072 57.624 ;
    END
  END s_axis_rq_tdata[29]
  PIN s_axis_rq_tdata[30]
    DIRECTION INPUT ;
    USE SIGNAL ;
    PORT
      LAYER M4 ;
      RECT 0.000 57.744 0.072 57.768 ;
    END
  END s_axis_rq_tdata[30]
  PIN s_axis_rq_tdata[31]
    DIRECTION INPUT ;
    USE SIGNAL ;
    PORT
      LAYER M4 ;
      RECT 0.000 57.888 0.072 57.912 ;
    END
  END s_axis_rq_tdata[31]
  PIN s_axis_rq_tdata[32]
    DIRECTION INPUT ;
    USE SIGNAL ;
    PORT
      LAYER M4 ;
      RECT 0.000 58.032 0.072 58.056 ;
    END
  END s_axis_rq_tdata[32]
  PIN s_axis_rq_tdata[33]
    DIRECTION INPUT ;
    USE SIGNAL ;
    PORT
      LAYER M4 ;
      RECT 0.000 58.176 0.072 58.200 ;
    END
  END s_axis_rq_tdata[33]
  PIN s_axis_rq_tdata[34]
    DIRECTION INPUT ;
    USE SIGNAL ;
    PORT
      LAYER M4 ;
      RECT 0.000 58.320 0.072 58.344 ;
    END
  END s_axis_rq_tdata[34]
  PIN s_axis_rq_tdata[35]
    DIRECTION INPUT ;
    USE SIGNAL ;
    PORT
      LAYER M4 ;
      RECT 0.000 58.464 0.072 58.488 ;
    END
  END s_axis_rq_tdata[35]
  PIN s_axis_rq_tdata[36]
    DIRECTION INPUT ;
    USE SIGNAL ;
    PORT
      LAYER M4 ;
      RECT 0.000 58.608 0.072 58.632 ;
    END
  END s_axis_rq_tdata[36]
  PIN s_axis_rq_tdata[37]
    DIRECTION INPUT ;
    USE SIGNAL ;
    PORT
      LAYER M4 ;
      RECT 0.000 58.752 0.072 58.776 ;
    END
  END s_axis_rq_tdata[37]
  PIN s_axis_rq_tdata[38]
    DIRECTION INPUT ;
    USE SIGNAL ;
    PORT
      LAYER M4 ;
      RECT 0.000 58.896 0.072 58.920 ;
    END
  END s_axis_rq_tdata[38]
  PIN s_axis_rq_tdata[39]
    DIRECTION INPUT ;
    USE SIGNAL ;
    PORT
      LAYER M4 ;
      RECT 0.000 59.040 0.072 59.064 ;
    END
  END s_axis_rq_tdata[39]
  PIN s_axis_rq_tdata[40]
    DIRECTION INPUT ;
    USE SIGNAL ;
    PORT
      LAYER M4 ;
      RECT 0.000 59.184 0.072 59.208 ;
    END
  END s_axis_rq_tdata[40]
  PIN s_axis_rq_tdata[41]
    DIRECTION INPUT ;
    USE SIGNAL ;
    PORT
      LAYER M4 ;
      RECT 0.000 59.328 0.072 59.352 ;
    END
  END s_axis_rq_tdata[41]
  PIN s_axis_rq_tdata[42]
    DIRECTION INPUT ;
    USE SIGNAL ;
    PORT
      LAYER M4 ;
      RECT 0.000 59.472 0.072 59.496 ;
    END
  END s_axis_rq_tdata[42]
  PIN s_axis_rq_tdata[43]
    DIRECTION INPUT ;
    USE SIGNAL ;
    PORT
      LAYER M4 ;
      RECT 0.000 59.616 0.072 59.640 ;
    END
  END s_axis_rq_tdata[43]
  PIN s_axis_rq_tdata[44]
    DIRECTION INPUT ;
    USE SIGNAL ;
    PORT
      LAYER M4 ;
      RECT 0.000 59.760 0.072 59.784 ;
    END
  END s_axis_rq_tdata[44]
  PIN s_axis_rq_tdata[45]
    DIRECTION INPUT ;
    USE SIGNAL ;
    PORT
      LAYER M4 ;
      RECT 0.000 59.904 0.072 59.928 ;
    END
  END s_axis_rq_tdata[45]
  PIN s_axis_rq_tdata[46]
    DIRECTION INPUT ;
    USE SIGNAL ;
    PORT
      LAYER M4 ;
      RECT 0.000 60.048 0.072 60.072 ;
    END
  END s_axis_rq_tdata[46]
  PIN s_axis_rq_tdata[47]
    DIRECTION INPUT ;
    USE SIGNAL ;
    PORT
      LAYER M4 ;
      RECT 0.000 60.192 0.072 60.216 ;
    END
  END s_axis_rq_tdata[47]
  PIN s_axis_rq_tdata[48]
    DIRECTION INPUT ;
    USE SIGNAL ;
    PORT
      LAYER M4 ;
      RECT 0.000 60.336 0.072 60.360 ;
    END
  END s_axis_rq_tdata[48]
  PIN s_axis_rq_tdata[49]
    DIRECTION INPUT ;
    USE SIGNAL ;
    PORT
      LAYER M4 ;
      RECT 0.000 60.480 0.072 60.504 ;
    END
  END s_axis_rq_tdata[49]
  PIN s_axis_rq_tdata[50]
    DIRECTION INPUT ;
    USE SIGNAL ;
    PORT
      LAYER M4 ;
      RECT 0.000 60.624 0.072 60.648 ;
    END
  END s_axis_rq_tdata[50]
  PIN s_axis_rq_tdata[51]
    DIRECTION INPUT ;
    USE SIGNAL ;
    PORT
      LAYER M4 ;
      RECT 0.000 60.768 0.072 60.792 ;
    END
  END s_axis_rq_tdata[51]
  PIN s_axis_rq_tdata[52]
    DIRECTION INPUT ;
    USE SIGNAL ;
    PORT
      LAYER M4 ;
      RECT 0.000 60.912 0.072 60.936 ;
    END
  END s_axis_rq_tdata[52]
  PIN s_axis_rq_tdata[53]
    DIRECTION INPUT ;
    USE SIGNAL ;
    PORT
      LAYER M4 ;
      RECT 0.000 61.056 0.072 61.080 ;
    END
  END s_axis_rq_tdata[53]
  PIN s_axis_rq_tdata[54]
    DIRECTION INPUT ;
    USE SIGNAL ;
    PORT
      LAYER M4 ;
      RECT 0.000 61.200 0.072 61.224 ;
    END
  END s_axis_rq_tdata[54]
  PIN s_axis_rq_tdata[55]
    DIRECTION INPUT ;
    USE SIGNAL ;
    PORT
      LAYER M4 ;
      RECT 0.000 61.344 0.072 61.368 ;
    END
  END s_axis_rq_tdata[55]
  PIN s_axis_rq_tdata[56]
    DIRECTION INPUT ;
    USE SIGNAL ;
    PORT
      LAYER M4 ;
      RECT 0.000 61.488 0.072 61.512 ;
    END
  END s_axis_rq_tdata[56]
  PIN s_axis_rq_tdata[57]
    DIRECTION INPUT ;
    USE SIGNAL ;
    PORT
      LAYER M4 ;
      RECT 0.000 61.632 0.072 61.656 ;
    END
  END s_axis_rq_tdata[57]
  PIN s_axis_rq_tdata[58]
    DIRECTION INPUT ;
    USE SIGNAL ;
    PORT
      LAYER M4 ;
      RECT 0.000 61.776 0.072 61.800 ;
    END
  END s_axis_rq_tdata[58]
  PIN s_axis_rq_tdata[59]
    DIRECTION INPUT ;
    USE SIGNAL ;
    PORT
      LAYER M4 ;
      RECT 0.000 61.920 0.072 61.944 ;
    END
  END s_axis_rq_tdata[59]
  PIN s_axis_rq_tdata[60]
    DIRECTION INPUT ;
    USE SIGNAL ;
    PORT
      LAYER M4 ;
      RECT 0.000 62.064 0.072 62.088 ;
    END
  END s_axis_rq_tdata[60]
  PIN s_axis_rq_tdata[61]
    DIRECTION INPUT ;
    USE SIGNAL ;
    PORT
      LAYER M4 ;
      RECT 0.000 62.208 0.072 62.232 ;
    END
  END s_axis_rq_tdata[61]
  PIN s_axis_rq_tdata[62]
    DIRECTION INPUT ;
    USE SIGNAL ;
    PORT
      LAYER M4 ;
      RECT 0.000 62.352 0.072 62.376 ;
    END
  END s_axis_rq_tdata[62]
  PIN s_axis_rq_tdata[63]
    DIRECTION INPUT ;
    USE SIGNAL ;
    PORT
      LAYER M4 ;
      RECT 0.000 62.496 0.072 62.520 ;
    END
  END s_axis_rq_tdata[63]
  PIN s_axis_rq_tdata[64]
    DIRECTION INPUT ;
    USE SIGNAL ;
    PORT
      LAYER M4 ;
      RECT 0.000 62.640 0.072 62.664 ;
    END
  END s_axis_rq_tdata[64]
  PIN s_axis_rq_tdata[65]
    DIRECTION INPUT ;
    USE SIGNAL ;
    PORT
      LAYER M4 ;
      RECT 0.000 62.784 0.072 62.808 ;
    END
  END s_axis_rq_tdata[65]
  PIN s_axis_rq_tdata[66]
    DIRECTION INPUT ;
    USE SIGNAL ;
    PORT
      LAYER M4 ;
      RECT 0.000 62.928 0.072 62.952 ;
    END
  END s_axis_rq_tdata[66]
  PIN s_axis_rq_tdata[67]
    DIRECTION INPUT ;
    USE SIGNAL ;
    PORT
      LAYER M4 ;
      RECT 0.000 63.072 0.072 63.096 ;
    END
  END s_axis_rq_tdata[67]
  PIN s_axis_rq_tdata[68]
    DIRECTION INPUT ;
    USE SIGNAL ;
    PORT
      LAYER M4 ;
      RECT 0.000 63.216 0.072 63.240 ;
    END
  END s_axis_rq_tdata[68]
  PIN s_axis_rq_tdata[69]
    DIRECTION INPUT ;
    USE SIGNAL ;
    PORT
      LAYER M4 ;
      RECT 0.000 63.360 0.072 63.384 ;
    END
  END s_axis_rq_tdata[69]
  PIN s_axis_rq_tdata[70]
    DIRECTION INPUT ;
    USE SIGNAL ;
    PORT
      LAYER M4 ;
      RECT 0.000 63.504 0.072 63.528 ;
    END
  END s_axis_rq_tdata[70]
  PIN s_axis_rq_tdata[71]
    DIRECTION INPUT ;
    USE SIGNAL ;
    PORT
      LAYER M4 ;
      RECT 0.000 63.648 0.072 63.672 ;
    END
  END s_axis_rq_tdata[71]
  PIN s_axis_rq_tdata[72]
    DIRECTION INPUT ;
    USE SIGNAL ;
    PORT
      LAYER M4 ;
      RECT 0.000 63.792 0.072 63.816 ;
    END
  END s_axis_rq_tdata[72]
  PIN s_axis_rq_tdata[73]
    DIRECTION INPUT ;
    USE SIGNAL ;
    PORT
      LAYER M4 ;
      RECT 0.000 63.936 0.072 63.960 ;
    END
  END s_axis_rq_tdata[73]
  PIN s_axis_rq_tdata[74]
    DIRECTION INPUT ;
    USE SIGNAL ;
    PORT
      LAYER M4 ;
      RECT 0.000 64.080 0.072 64.104 ;
    END
  END s_axis_rq_tdata[74]
  PIN s_axis_rq_tdata[75]
    DIRECTION INPUT ;
    USE SIGNAL ;
    PORT
      LAYER M4 ;
      RECT 0.000 64.224 0.072 64.248 ;
    END
  END s_axis_rq_tdata[75]
  PIN s_axis_rq_tdata[76]
    DIRECTION INPUT ;
    USE SIGNAL ;
    PORT
      LAYER M4 ;
      RECT 0.000 64.368 0.072 64.392 ;
    END
  END s_axis_rq_tdata[76]
  PIN s_axis_rq_tdata[77]
    DIRECTION INPUT ;
    USE SIGNAL ;
    PORT
      LAYER M4 ;
      RECT 0.000 64.512 0.072 64.536 ;
    END
  END s_axis_rq_tdata[77]
  PIN s_axis_rq_tdata[78]
    DIRECTION INPUT ;
    USE SIGNAL ;
    PORT
      LAYER M4 ;
      RECT 0.000 64.656 0.072 64.680 ;
    END
  END s_axis_rq_tdata[78]
  PIN s_axis_rq_tdata[79]
    DIRECTION INPUT ;
    USE SIGNAL ;
    PORT
      LAYER M4 ;
      RECT 0.000 64.800 0.072 64.824 ;
    END
  END s_axis_rq_tdata[79]
  PIN s_axis_rq_tdata[80]
    DIRECTION INPUT ;
    USE SIGNAL ;
    PORT
      LAYER M4 ;
      RECT 0.000 64.944 0.072 64.968 ;
    END
  END s_axis_rq_tdata[80]
  PIN s_axis_rq_tdata[81]
    DIRECTION INPUT ;
    USE SIGNAL ;
    PORT
      LAYER M4 ;
      RECT 0.000 65.088 0.072 65.112 ;
    END
  END s_axis_rq_tdata[81]
  PIN s_axis_rq_tdata[82]
    DIRECTION INPUT ;
    USE SIGNAL ;
    PORT
      LAYER M4 ;
      RECT 0.000 65.232 0.072 65.256 ;
    END
  END s_axis_rq_tdata[82]
  PIN s_axis_rq_tdata[83]
    DIRECTION INPUT ;
    USE SIGNAL ;
    PORT
      LAYER M4 ;
      RECT 0.000 65.376 0.072 65.400 ;
    END
  END s_axis_rq_tdata[83]
  PIN s_axis_rq_tdata[84]
    DIRECTION INPUT ;
    USE SIGNAL ;
    PORT
      LAYER M4 ;
      RECT 0.000 65.520 0.072 65.544 ;
    END
  END s_axis_rq_tdata[84]
  PIN s_axis_rq_tdata[85]
    DIRECTION INPUT ;
    USE SIGNAL ;
    PORT
      LAYER M4 ;
      RECT 0.000 65.664 0.072 65.688 ;
    END
  END s_axis_rq_tdata[85]
  PIN s_axis_rq_tdata[86]
    DIRECTION INPUT ;
    USE SIGNAL ;
    PORT
      LAYER M4 ;
      RECT 0.000 65.808 0.072 65.832 ;
    END
  END s_axis_rq_tdata[86]
  PIN s_axis_rq_tdata[87]
    DIRECTION INPUT ;
    USE SIGNAL ;
    PORT
      LAYER M4 ;
      RECT 0.000 65.952 0.072 65.976 ;
    END
  END s_axis_rq_tdata[87]
  PIN s_axis_rq_tdata[88]
    DIRECTION INPUT ;
    USE SIGNAL ;
    PORT
      LAYER M4 ;
      RECT 0.000 66.096 0.072 66.120 ;
    END
  END s_axis_rq_tdata[88]
  PIN s_axis_rq_tdata[89]
    DIRECTION INPUT ;
    USE SIGNAL ;
    PORT
      LAYER M4 ;
      RECT 0.000 66.240 0.072 66.264 ;
    END
  END s_axis_rq_tdata[89]
  PIN s_axis_rq_tdata[90]
    DIRECTION INPUT ;
    USE SIGNAL ;
    PORT
      LAYER M4 ;
      RECT 0.000 66.384 0.072 66.408 ;
    END
  END s_axis_rq_tdata[90]
  PIN s_axis_rq_tdata[91]
    DIRECTION INPUT ;
    USE SIGNAL ;
    PORT
      LAYER M4 ;
      RECT 0.000 66.528 0.072 66.552 ;
    END
  END s_axis_rq_tdata[91]
  PIN s_axis_rq_tdata[92]
    DIRECTION INPUT ;
    USE SIGNAL ;
    PORT
      LAYER M4 ;
      RECT 0.000 66.672 0.072 66.696 ;
    END
  END s_axis_rq_tdata[92]
  PIN s_axis_rq_tdata[93]
    DIRECTION INPUT ;
    USE SIGNAL ;
    PORT
      LAYER M4 ;
      RECT 0.000 66.816 0.072 66.840 ;
    END
  END s_axis_rq_tdata[93]
  PIN s_axis_rq_tdata[94]
    DIRECTION INPUT ;
    USE SIGNAL ;
    PORT
      LAYER M4 ;
      RECT 0.000 66.960 0.072 66.984 ;
    END
  END s_axis_rq_tdata[94]
  PIN s_axis_rq_tdata[95]
    DIRECTION INPUT ;
    USE SIGNAL ;
    PORT
      LAYER M4 ;
      RECT 0.000 67.104 0.072 67.128 ;
    END
  END s_axis_rq_tdata[95]
  PIN s_axis_rq_tdata[96]
    DIRECTION INPUT ;
    USE SIGNAL ;
    PORT
      LAYER M4 ;
      RECT 0.000 67.248 0.072 67.272 ;
    END
  END s_axis_rq_tdata[96]
  PIN s_axis_rq_tdata[97]
    DIRECTION INPUT ;
    USE SIGNAL ;
    PORT
      LAYER M4 ;
      RECT 0.000 67.392 0.072 67.416 ;
    END
  END s_axis_rq_tdata[97]
  PIN s_axis_rq_tdata[98]
    DIRECTION INPUT ;
    USE SIGNAL ;
    PORT
      LAYER M4 ;
      RECT 0.000 67.536 0.072 67.560 ;
    END
  END s_axis_rq_tdata[98]
  PIN s_axis_rq_tdata[99]
    DIRECTION INPUT ;
    USE SIGNAL ;
    PORT
      LAYER M4 ;
      RECT 0.000 67.680 0.072 67.704 ;
    END
  END s_axis_rq_tdata[99]
  PIN s_axis_rq_tdata[100]
    DIRECTION INPUT ;
    USE SIGNAL ;
    PORT
      LAYER M4 ;
      RECT 0.000 67.824 0.072 67.848 ;
    END
  END s_axis_rq_tdata[100]
  PIN s_axis_rq_tdata[101]
    DIRECTION INPUT ;
    USE SIGNAL ;
    PORT
      LAYER M4 ;
      RECT 0.000 67.968 0.072 67.992 ;
    END
  END s_axis_rq_tdata[101]
  PIN s_axis_rq_tdata[102]
    DIRECTION INPUT ;
    USE SIGNAL ;
    PORT
      LAYER M4 ;
      RECT 0.000 68.112 0.072 68.136 ;
    END
  END s_axis_rq_tdata[102]
  PIN s_axis_rq_tdata[103]
    DIRECTION INPUT ;
    USE SIGNAL ;
    PORT
      LAYER M4 ;
      RECT 0.000 68.256 0.072 68.280 ;
    END
  END s_axis_rq_tdata[103]
  PIN s_axis_rq_tdata[104]
    DIRECTION INPUT ;
    USE SIGNAL ;
    PORT
      LAYER M4 ;
      RECT 0.000 68.400 0.072 68.424 ;
    END
  END s_axis_rq_tdata[104]
  PIN s_axis_rq_tdata[105]
    DIRECTION INPUT ;
    USE SIGNAL ;
    PORT
      LAYER M4 ;
      RECT 0.000 68.544 0.072 68.568 ;
    END
  END s_axis_rq_tdata[105]
  PIN s_axis_rq_tdata[106]
    DIRECTION INPUT ;
    USE SIGNAL ;
    PORT
      LAYER M4 ;
      RECT 0.000 68.688 0.072 68.712 ;
    END
  END s_axis_rq_tdata[106]
  PIN s_axis_rq_tdata[107]
    DIRECTION INPUT ;
    USE SIGNAL ;
    PORT
      LAYER M4 ;
      RECT 0.000 68.832 0.072 68.856 ;
    END
  END s_axis_rq_tdata[107]
  PIN s_axis_rq_tdata[108]
    DIRECTION INPUT ;
    USE SIGNAL ;
    PORT
      LAYER M4 ;
      RECT 0.000 68.976 0.072 69.000 ;
    END
  END s_axis_rq_tdata[108]
  PIN s_axis_rq_tdata[109]
    DIRECTION INPUT ;
    USE SIGNAL ;
    PORT
      LAYER M4 ;
      RECT 0.000 69.120 0.072 69.144 ;
    END
  END s_axis_rq_tdata[109]
  PIN s_axis_rq_tdata[110]
    DIRECTION INPUT ;
    USE SIGNAL ;
    PORT
      LAYER M4 ;
      RECT 0.000 69.264 0.072 69.288 ;
    END
  END s_axis_rq_tdata[110]
  PIN s_axis_rq_tdata[111]
    DIRECTION INPUT ;
    USE SIGNAL ;
    PORT
      LAYER M4 ;
      RECT 0.000 69.408 0.072 69.432 ;
    END
  END s_axis_rq_tdata[111]
  PIN s_axis_rq_tdata[112]
    DIRECTION INPUT ;
    USE SIGNAL ;
    PORT
      LAYER M4 ;
      RECT 0.000 69.552 0.072 69.576 ;
    END
  END s_axis_rq_tdata[112]
  PIN s_axis_rq_tdata[113]
    DIRECTION INPUT ;
    USE SIGNAL ;
    PORT
      LAYER M4 ;
      RECT 0.000 69.696 0.072 69.720 ;
    END
  END s_axis_rq_tdata[113]
  PIN s_axis_rq_tdata[114]
    DIRECTION INPUT ;
    USE SIGNAL ;
    PORT
      LAYER M4 ;
      RECT 0.000 69.840 0.072 69.864 ;
    END
  END s_axis_rq_tdata[114]
  PIN s_axis_rq_tdata[115]
    DIRECTION INPUT ;
    USE SIGNAL ;
    PORT
      LAYER M4 ;
      RECT 0.000 69.984 0.072 70.008 ;
    END
  END s_axis_rq_tdata[115]
  PIN s_axis_rq_tdata[116]
    DIRECTION INPUT ;
    USE SIGNAL ;
    PORT
      LAYER M4 ;
      RECT 0.000 70.128 0.072 70.152 ;
    END
  END s_axis_rq_tdata[116]
  PIN s_axis_rq_tdata[117]
    DIRECTION INPUT ;
    USE SIGNAL ;
    PORT
      LAYER M4 ;
      RECT 0.000 70.272 0.072 70.296 ;
    END
  END s_axis_rq_tdata[117]
  PIN s_axis_rq_tdata[118]
    DIRECTION INPUT ;
    USE SIGNAL ;
    PORT
      LAYER M4 ;
      RECT 0.000 70.416 0.072 70.440 ;
    END
  END s_axis_rq_tdata[118]
  PIN s_axis_rq_tdata[119]
    DIRECTION INPUT ;
    USE SIGNAL ;
    PORT
      LAYER M4 ;
      RECT 0.000 70.560 0.072 70.584 ;
    END
  END s_axis_rq_tdata[119]
  PIN s_axis_rq_tdata[120]
    DIRECTION INPUT ;
    USE SIGNAL ;
    PORT
      LAYER M4 ;
      RECT 0.000 70.704 0.072 70.728 ;
    END
  END s_axis_rq_tdata[120]
  PIN s_axis_rq_tdata[121]
    DIRECTION INPUT ;
    USE SIGNAL ;
    PORT
      LAYER M4 ;
      RECT 0.000 70.848 0.072 70.872 ;
    END
  END s_axis_rq_tdata[121]
  PIN s_axis_rq_tdata[122]
    DIRECTION INPUT ;
    USE SIGNAL ;
    PORT
      LAYER M4 ;
      RECT 0.000 70.992 0.072 71.016 ;
    END
  END s_axis_rq_tdata[122]
  PIN s_axis_rq_tdata[123]
    DIRECTION INPUT ;
    USE SIGNAL ;
    PORT
      LAYER M4 ;
      RECT 0.000 71.136 0.072 71.160 ;
    END
  END s_axis_rq_tdata[123]
  PIN s_axis_rq_tdata[124]
    DIRECTION INPUT ;
    USE SIGNAL ;
    PORT
      LAYER M4 ;
      RECT 0.000 71.280 0.072 71.304 ;
    END
  END s_axis_rq_tdata[124]
  PIN s_axis_rq_tdata[125]
    DIRECTION INPUT ;
    USE SIGNAL ;
    PORT
      LAYER M4 ;
      RECT 0.000 71.424 0.072 71.448 ;
    END
  END s_axis_rq_tdata[125]
  PIN s_axis_rq_tdata[126]
    DIRECTION INPUT ;
    USE SIGNAL ;
    PORT
      LAYER M4 ;
      RECT 0.000 71.568 0.072 71.592 ;
    END
  END s_axis_rq_tdata[126]
  PIN s_axis_rq_tdata[127]
    DIRECTION INPUT ;
    USE SIGNAL ;
    PORT
      LAYER M4 ;
      RECT 0.000 71.712 0.072 71.736 ;
    END
  END s_axis_rq_tdata[127]
  PIN s_axis_rq_tkeep[0]
    DIRECTION INPUT ;
    USE SIGNAL ;
    PORT
      LAYER M4 ;
      RECT 0.000 71.856 0.072 71.880 ;
    END
  END s_axis_rq_tkeep[0]
  PIN s_axis_rq_tkeep[1]
    DIRECTION INPUT ;
    USE SIGNAL ;
    PORT
      LAYER M4 ;
      RECT 0.000 72.000 0.072 72.024 ;
    END
  END s_axis_rq_tkeep[1]
  PIN s_axis_rq_tkeep[2]
    DIRECTION INPUT ;
    USE SIGNAL ;
    PORT
      LAYER M4 ;
      RECT 0.000 72.144 0.072 72.168 ;
    END
  END s_axis_rq_tkeep[2]
  PIN s_axis_rq_tkeep[3]
    DIRECTION INPUT ;
    USE SIGNAL ;
    PORT
      LAYER M4 ;
      RECT 0.000 72.288 0.072 72.312 ;
    END
  END s_axis_rq_tkeep[3]
  PIN s_axis_rq_tlast
    DIRECTION INPUT ;
    USE SIGNAL ;
    PORT
      LAYER M4 ;
      RECT 0.000 72.432 0.072 72.456 ;
    END
  END s_axis_rq_tlast
  PIN s_axis_rq_tuser[0]
    DIRECTION INPUT ;
    USE SIGNAL ;
    PORT
      LAYER M4 ;
      RECT 0.000 72.576 0.072 72.600 ;
    END
  END s_axis_rq_tuser[0]
  PIN s_axis_rq_tuser[1]
    DIRECTION INPUT ;
    USE SIGNAL ;
    PORT
      LAYER M4 ;
      RECT 0.000 72.720 0.072 72.744 ;
    END
  END s_axis_rq_tuser[1]
  PIN s_axis_rq_tuser[2]
    DIRECTION INPUT ;
    USE SIGNAL ;
    PORT
      LAYER M4 ;
      RECT 0.000 72.864 0.072 72.888 ;
    END
  END s_axis_rq_tuser[2]
  PIN s_axis_rq_tuser[3]
    DIRECTION INPUT ;
    USE SIGNAL ;
    PORT
      LAYER M4 ;
      RECT 0.000 73.008 0.072 73.032 ;
    END
  END s_axis_rq_tuser[3]
  PIN s_axis_rq_tuser[4]
    DIRECTION INPUT ;
    USE SIGNAL ;
    PORT
      LAYER M4 ;
      RECT 0.000 73.152 0.072 73.176 ;
    END
  END s_axis_rq_tuser[4]
  PIN s_axis_rq_tuser[5]
    DIRECTION INPUT ;
    USE SIGNAL ;
    PORT
      LAYER M4 ;
      RECT 0.000 73.296 0.072 73.320 ;
    END
  END s_axis_rq_tuser[5]
  PIN s_axis_rq_tuser[6]
    DIRECTION INPUT ;
    USE SIGNAL ;
    PORT
      LAYER M4 ;
      RECT 0.000 73.440 0.072 73.464 ;
    END
  END s_axis_rq_tuser[6]
  PIN s_axis_rq_tuser[7]
    DIRECTION INPUT ;
    USE SIGNAL ;
    PORT
      LAYER M4 ;
      RECT 0.000 73.584 0.072 73.608 ;
    END
  END s_axis_rq_tuser[7]
  PIN s_axis_rq_tuser[8]
    DIRECTION INPUT ;
    USE SIGNAL ;
    PORT
      LAYER M4 ;
      RECT 0.000 73.728 0.072 73.752 ;
    END
  END s_axis_rq_tuser[8]
  PIN s_axis_rq_tuser[9]
    DIRECTION INPUT ;
    USE SIGNAL ;
    PORT
      LAYER M4 ;
      RECT 0.000 73.872 0.072 73.896 ;
    END
  END s_axis_rq_tuser[9]
  PIN s_axis_rq_tuser[10]
    DIRECTION INPUT ;
    USE SIGNAL ;
    PORT
      LAYER M4 ;
      RECT 0.000 74.016 0.072 74.040 ;
    END
  END s_axis_rq_tuser[10]
  PIN s_axis_rq_tuser[11]
    DIRECTION INPUT ;
    USE SIGNAL ;
    PORT
      LAYER M4 ;
      RECT 0.000 74.160 0.072 74.184 ;
    END
  END s_axis_rq_tuser[11]
  PIN s_axis_rq_tuser[12]
    DIRECTION INPUT ;
    USE SIGNAL ;
    PORT
      LAYER M4 ;
      RECT 0.000 74.304 0.072 74.328 ;
    END
  END s_axis_rq_tuser[12]
  PIN s_axis_rq_tuser[13]
    DIRECTION INPUT ;
    USE SIGNAL ;
    PORT
      LAYER M4 ;
      RECT 0.000 74.448 0.072 74.472 ;
    END
  END s_axis_rq_tuser[13]
  PIN s_axis_rq_tuser[14]
    DIRECTION INPUT ;
    USE SIGNAL ;
    PORT
      LAYER M4 ;
      RECT 0.000 74.592 0.072 74.616 ;
    END
  END s_axis_rq_tuser[14]
  PIN s_axis_rq_tuser[15]
    DIRECTION INPUT ;
    USE SIGNAL ;
    PORT
      LAYER M4 ;
      RECT 0.000 74.736 0.072 74.760 ;
    END
  END s_axis_rq_tuser[15]
  PIN s_axis_rq_tuser[16]
    DIRECTION INPUT ;
    USE SIGNAL ;
    PORT
      LAYER M4 ;
      RECT 0.000 74.880 0.072 74.904 ;
    END
  END s_axis_rq_tuser[16]
  PIN s_axis_rq_tuser[17]
    DIRECTION INPUT ;
    USE SIGNAL ;
    PORT
      LAYER M4 ;
      RECT 0.000 75.024 0.072 75.048 ;
    END
  END s_axis_rq_tuser[17]
  PIN s_axis_rq_tuser[18]
    DIRECTION INPUT ;
    USE SIGNAL ;
    PORT
      LAYER M4 ;
      RECT 0.000 75.168 0.072 75.192 ;
    END
  END s_axis_rq_tuser[18]
  PIN s_axis_rq_tuser[19]
    DIRECTION INPUT ;
    USE SIGNAL ;
    PORT
      LAYER M4 ;
      RECT 0.000 75.312 0.072 75.336 ;
    END
  END s_axis_rq_tuser[19]
  PIN s_axis_rq_tuser[20]
    DIRECTION INPUT ;
    USE SIGNAL ;
    PORT
      LAYER M4 ;
      RECT 0.000 75.456 0.072 75.480 ;
    END
  END s_axis_rq_tuser[20]
  PIN s_axis_rq_tuser[21]
    DIRECTION INPUT ;
    USE SIGNAL ;
    PORT
      LAYER M4 ;
      RECT 0.000 75.600 0.072 75.624 ;
    END
  END s_axis_rq_tuser[21]
  PIN s_axis_rq_tuser[22]
    DIRECTION INPUT ;
    USE SIGNAL ;
    PORT
      LAYER M4 ;
      RECT 0.000 75.744 0.072 75.768 ;
    END
  END s_axis_rq_tuser[22]
  PIN s_axis_rq_tuser[23]
    DIRECTION INPUT ;
    USE SIGNAL ;
    PORT
      LAYER M4 ;
      RECT 0.000 75.888 0.072 75.912 ;
    END
  END s_axis_rq_tuser[23]
  PIN s_axis_rq_tuser[24]
    DIRECTION INPUT ;
    USE SIGNAL ;
    PORT
      LAYER M4 ;
      RECT 0.000 76.032 0.072 76.056 ;
    END
  END s_axis_rq_tuser[24]
  PIN s_axis_rq_tuser[25]
    DIRECTION INPUT ;
    USE SIGNAL ;
    PORT
      LAYER M4 ;
      RECT 0.000 76.176 0.072 76.200 ;
    END
  END s_axis_rq_tuser[25]
  PIN s_axis_rq_tuser[26]
    DIRECTION INPUT ;
    USE SIGNAL ;
    PORT
      LAYER M4 ;
      RECT 0.000 76.320 0.072 76.344 ;
    END
  END s_axis_rq_tuser[26]
  PIN s_axis_rq_tuser[27]
    DIRECTION INPUT ;
    USE SIGNAL ;
    PORT
      LAYER M4 ;
      RECT 0.000 76.464 0.072 76.488 ;
    END
  END s_axis_rq_tuser[27]
  PIN s_axis_rq_tuser[28]
    DIRECTION INPUT ;
    USE SIGNAL ;
    PORT
      LAYER M4 ;
      RECT 0.000 76.608 0.072 76.632 ;
    END
  END s_axis_rq_tuser[28]
  PIN s_axis_rq_tuser[29]
    DIRECTION INPUT ;
    USE SIGNAL ;
    PORT
      LAYER M4 ;
      RECT 0.000 76.752 0.072 76.776 ;
    END
  END s_axis_rq_tuser[29]
  PIN s_axis_rq_tuser[30]
    DIRECTION INPUT ;
    USE SIGNAL ;
    PORT
      LAYER M4 ;
      RECT 0.000 76.896 0.072 76.920 ;
    END
  END s_axis_rq_tuser[30]
  PIN s_axis_rq_tuser[31]
    DIRECTION INPUT ;
    USE SIGNAL ;
    PORT
      LAYER M4 ;
      RECT 0.000 77.040 0.072 77.064 ;
    END
  END s_axis_rq_tuser[31]
  PIN s_axis_rq_tuser[32]
    DIRECTION INPUT ;
    USE SIGNAL ;
    PORT
      LAYER M4 ;
      RECT 0.000 77.184 0.072 77.208 ;
    END
  END s_axis_rq_tuser[32]
  PIN s_axis_rq_tuser[33]
    DIRECTION INPUT ;
    USE SIGNAL ;
    PORT
      LAYER M4 ;
      RECT 0.000 77.328 0.072 77.352 ;
    END
  END s_axis_rq_tuser[33]
  PIN s_axis_rq_tuser[34]
    DIRECTION INPUT ;
    USE SIGNAL ;
    PORT
      LAYER M4 ;
      RECT 0.000 77.472 0.072 77.496 ;
    END
  END s_axis_rq_tuser[34]
  PIN s_axis_rq_tuser[35]
    DIRECTION INPUT ;
    USE SIGNAL ;
    PORT
      LAYER M4 ;
      RECT 0.000 77.616 0.072 77.640 ;
    END
  END s_axis_rq_tuser[35]
  PIN s_axis_rq_tuser[36]
    DIRECTION INPUT ;
    USE SIGNAL ;
    PORT
      LAYER M4 ;
      RECT 0.000 77.760 0.072 77.784 ;
    END
  END s_axis_rq_tuser[36]
  PIN s_axis_rq_tuser[37]
    DIRECTION INPUT ;
    USE SIGNAL ;
    PORT
      LAYER M4 ;
      RECT 0.000 77.904 0.072 77.928 ;
    END
  END s_axis_rq_tuser[37]
  PIN s_axis_rq_tuser[38]
    DIRECTION INPUT ;
    USE SIGNAL ;
    PORT
      LAYER M4 ;
      RECT 0.000 78.048 0.072 78.072 ;
    END
  END s_axis_rq_tuser[38]
  PIN s_axis_rq_tuser[39]
    DIRECTION INPUT ;
    USE SIGNAL ;
    PORT
      LAYER M4 ;
      RECT 0.000 78.192 0.072 78.216 ;
    END
  END s_axis_rq_tuser[39]
  PIN s_axis_rq_tuser[40]
    DIRECTION INPUT ;
    USE SIGNAL ;
    PORT
      LAYER M4 ;
      RECT 0.000 78.336 0.072 78.360 ;
    END
  END s_axis_rq_tuser[40]
  PIN s_axis_rq_tuser[41]
    DIRECTION INPUT ;
    USE SIGNAL ;
    PORT
      LAYER M4 ;
      RECT 0.000 78.480 0.072 78.504 ;
    END
  END s_axis_rq_tuser[41]
  PIN s_axis_rq_tuser[42]
    DIRECTION INPUT ;
    USE SIGNAL ;
    PORT
      LAYER M4 ;
      RECT 0.000 78.624 0.072 78.648 ;
    END
  END s_axis_rq_tuser[42]
  PIN s_axis_rq_tuser[43]
    DIRECTION INPUT ;
    USE SIGNAL ;
    PORT
      LAYER M4 ;
      RECT 0.000 78.768 0.072 78.792 ;
    END
  END s_axis_rq_tuser[43]
  PIN s_axis_rq_tuser[44]
    DIRECTION INPUT ;
    USE SIGNAL ;
    PORT
      LAYER M4 ;
      RECT 0.000 78.912 0.072 78.936 ;
    END
  END s_axis_rq_tuser[44]
  PIN s_axis_rq_tuser[45]
    DIRECTION INPUT ;
    USE SIGNAL ;
    PORT
      LAYER M4 ;
      RECT 0.000 79.056 0.072 79.080 ;
    END
  END s_axis_rq_tuser[45]
  PIN s_axis_rq_tuser[46]
    DIRECTION INPUT ;
    USE SIGNAL ;
    PORT
      LAYER M4 ;
      RECT 0.000 79.200 0.072 79.224 ;
    END
  END s_axis_rq_tuser[46]
  PIN s_axis_rq_tuser[47]
    DIRECTION INPUT ;
    USE SIGNAL ;
    PORT
      LAYER M4 ;
      RECT 0.000 79.344 0.072 79.368 ;
    END
  END s_axis_rq_tuser[47]
  PIN s_axis_rq_tuser[48]
    DIRECTION INPUT ;
    USE SIGNAL ;
    PORT
      LAYER M4 ;
      RECT 0.000 79.488 0.072 79.512 ;
    END
  END s_axis_rq_tuser[48]
  PIN s_axis_rq_tuser[49]
    DIRECTION INPUT ;
    USE SIGNAL ;
    PORT
      LAYER M4 ;
      RECT 0.000 79.632 0.072 79.656 ;
    END
  END s_axis_rq_tuser[49]
  PIN s_axis_rq_tuser[50]
    DIRECTION INPUT ;
    USE SIGNAL ;
    PORT
      LAYER M4 ;
      RECT 0.000 79.776 0.072 79.800 ;
    END
  END s_axis_rq_tuser[50]
  PIN s_axis_rq_tuser[51]
    DIRECTION INPUT ;
    USE SIGNAL ;
    PORT
      LAYER M4 ;
      RECT 0.000 79.920 0.072 79.944 ;
    END
  END s_axis_rq_tuser[51]
  PIN s_axis_rq_tuser[52]
    DIRECTION INPUT ;
    USE SIGNAL ;
    PORT
      LAYER M4 ;
      RECT 0.000 80.064 0.072 80.088 ;
    END
  END s_axis_rq_tuser[52]
  PIN s_axis_rq_tuser[53]
    DIRECTION INPUT ;
    USE SIGNAL ;
    PORT
      LAYER M4 ;
      RECT 0.000 80.208 0.072 80.232 ;
    END
  END s_axis_rq_tuser[53]
  PIN s_axis_rq_tuser[54]
    DIRECTION INPUT ;
    USE SIGNAL ;
    PORT
      LAYER M4 ;
      RECT 0.000 80.352 0.072 80.376 ;
    END
  END s_axis_rq_tuser[54]
  PIN s_axis_rq_tuser[55]
    DIRECTION INPUT ;
    USE SIGNAL ;
    PORT
      LAYER M4 ;
      RECT 0.000 80.496 0.072 80.520 ;
    END
  END s_axis_rq_tuser[55]
  PIN s_axis_rq_tuser[56]
    DIRECTION INPUT ;
    USE SIGNAL ;
    PORT
      LAYER M4 ;
      RECT 0.000 80.640 0.072 80.664 ;
    END
  END s_axis_rq_tuser[56]
  PIN s_axis_rq_tuser[57]
    DIRECTION INPUT ;
    USE SIGNAL ;
    PORT
      LAYER M4 ;
      RECT 0.000 80.784 0.072 80.808 ;
    END
  END s_axis_rq_tuser[57]
  PIN s_axis_rq_tuser[58]
    DIRECTION INPUT ;
    USE SIGNAL ;
    PORT
      LAYER M4 ;
      RECT 0.000 80.928 0.072 80.952 ;
    END
  END s_axis_rq_tuser[58]
  PIN s_axis_rq_tuser[59]
    DIRECTION INPUT ;
    USE SIGNAL ;
    PORT
      LAYER M4 ;
      RECT 0.000 81.072 0.072 81.096 ;
    END
  END s_axis_rq_tuser[59]
  PIN s_axis_rq_tvalid
    DIRECTION INPUT ;
    USE SIGNAL ;
    PORT
      LAYER M4 ;
      RECT 0.000 81.216 0.072 81.240 ;
    END
  END s_axis_rq_tvalid
  PIN sys_clk
    DIRECTION INPUT ;
    USE SIGNAL ;
    PORT
      LAYER M4 ;
      RECT 0.000 81.360 0.072 81.384 ;
    END
  END sys_clk
  PIN sys_clk_gt
    DIRECTION INPUT ;
    USE SIGNAL ;
    PORT
      LAYER M4 ;
      RECT 0.000 81.504 0.072 81.528 ;
    END
  END sys_clk_gt
  PIN sys_reset
    DIRECTION INPUT ;
    USE SIGNAL ;
    PORT
      LAYER M4 ;
      RECT 0.000 81.648 0.072 81.672 ;
    END
  END sys_reset
  PIN cfg_current_speed[0]
    DIRECTION OUTPUT ;
    USE SIGNAL ;
    PORT
      LAYER M4 ;
      RECT 0.000 81.792 0.072 81.816 ;
    END
  END cfg_current_speed[0]
  PIN cfg_current_speed[1]
    DIRECTION OUTPUT ;
    USE SIGNAL ;
    PORT
      LAYER M4 ;
      RECT 0.000 81.936 0.072 81.960 ;
    END
  END cfg_current_speed[1]
  PIN cfg_current_speed[2]
    DIRECTION OUTPUT ;
    USE SIGNAL ;
    PORT
      LAYER M4 ;
      RECT 0.000 82.080 0.072 82.104 ;
    END
  END cfg_current_speed[2]
  PIN cfg_dpa_substate_change[0]
    DIRECTION OUTPUT ;
    USE SIGNAL ;
    PORT
      LAYER M4 ;
      RECT 0.000 82.224 0.072 82.248 ;
    END
  END cfg_dpa_substate_change[0]
  PIN cfg_dpa_substate_change[1]
    DIRECTION OUTPUT ;
    USE SIGNAL ;
    PORT
      LAYER M4 ;
      RECT 0.000 82.368 0.072 82.392 ;
    END
  END cfg_dpa_substate_change[1]
  PIN cfg_dpa_substate_change[2]
    DIRECTION OUTPUT ;
    USE SIGNAL ;
    PORT
      LAYER M4 ;
      RECT 0.000 82.512 0.072 82.536 ;
    END
  END cfg_dpa_substate_change[2]
  PIN cfg_dpa_substate_change[3]
    DIRECTION OUTPUT ;
    USE SIGNAL ;
    PORT
      LAYER M4 ;
      RECT 0.000 82.656 0.072 82.680 ;
    END
  END cfg_dpa_substate_change[3]
  PIN cfg_err_cor_out
    DIRECTION OUTPUT ;
    USE SIGNAL ;
    PORT
      LAYER M4 ;
      RECT 0.000 82.800 0.072 82.824 ;
    END
  END cfg_err_cor_out
  PIN cfg_err_fatal_out
    DIRECTION OUTPUT ;
    USE SIGNAL ;
    PORT
      LAYER M4 ;
      RECT 0.000 82.944 0.072 82.968 ;
    END
  END cfg_err_fatal_out
  PIN cfg_err_nonfatal_out
    DIRECTION OUTPUT ;
    USE SIGNAL ;
    PORT
      LAYER M4 ;
      RECT 0.000 83.088 0.072 83.112 ;
    END
  END cfg_err_nonfatal_out
  PIN cfg_fc_cpld[0]
    DIRECTION OUTPUT ;
    USE SIGNAL ;
    PORT
      LAYER M4 ;
      RECT 0.000 83.232 0.072 83.256 ;
    END
  END cfg_fc_cpld[0]
  PIN cfg_fc_cpld[1]
    DIRECTION OUTPUT ;
    USE SIGNAL ;
    PORT
      LAYER M4 ;
      RECT 0.000 83.376 0.072 83.400 ;
    END
  END cfg_fc_cpld[1]
  PIN cfg_fc_cpld[2]
    DIRECTION OUTPUT ;
    USE SIGNAL ;
    PORT
      LAYER M4 ;
      RECT 0.000 83.520 0.072 83.544 ;
    END
  END cfg_fc_cpld[2]
  PIN cfg_fc_cpld[3]
    DIRECTION OUTPUT ;
    USE SIGNAL ;
    PORT
      LAYER M4 ;
      RECT 0.000 83.664 0.072 83.688 ;
    END
  END cfg_fc_cpld[3]
  PIN cfg_fc_cpld[4]
    DIRECTION OUTPUT ;
    USE SIGNAL ;
    PORT
      LAYER M4 ;
      RECT 0.000 83.808 0.072 83.832 ;
    END
  END cfg_fc_cpld[4]
  PIN cfg_fc_cpld[5]
    DIRECTION OUTPUT ;
    USE SIGNAL ;
    PORT
      LAYER M4 ;
      RECT 0.000 83.952 0.072 83.976 ;
    END
  END cfg_fc_cpld[5]
  PIN cfg_fc_cpld[6]
    DIRECTION OUTPUT ;
    USE SIGNAL ;
    PORT
      LAYER M4 ;
      RECT 0.000 84.096 0.072 84.120 ;
    END
  END cfg_fc_cpld[6]
  PIN cfg_fc_cpld[7]
    DIRECTION OUTPUT ;
    USE SIGNAL ;
    PORT
      LAYER M4 ;
      RECT 0.000 84.240 0.072 84.264 ;
    END
  END cfg_fc_cpld[7]
  PIN cfg_fc_cpld[8]
    DIRECTION OUTPUT ;
    USE SIGNAL ;
    PORT
      LAYER M4 ;
      RECT 0.000 84.384 0.072 84.408 ;
    END
  END cfg_fc_cpld[8]
  PIN cfg_fc_cpld[9]
    DIRECTION OUTPUT ;
    USE SIGNAL ;
    PORT
      LAYER M4 ;
      RECT 0.000 84.528 0.072 84.552 ;
    END
  END cfg_fc_cpld[9]
  PIN cfg_fc_cpld[10]
    DIRECTION OUTPUT ;
    USE SIGNAL ;
    PORT
      LAYER M4 ;
      RECT 0.000 84.672 0.072 84.696 ;
    END
  END cfg_fc_cpld[10]
  PIN cfg_fc_cpld[11]
    DIRECTION OUTPUT ;
    USE SIGNAL ;
    PORT
      LAYER M4 ;
      RECT 0.000 84.816 0.072 84.840 ;
    END
  END cfg_fc_cpld[11]
  PIN cfg_fc_cplh[0]
    DIRECTION OUTPUT ;
    USE SIGNAL ;
    PORT
      LAYER M4 ;
      RECT 0.000 84.960 0.072 84.984 ;
    END
  END cfg_fc_cplh[0]
  PIN cfg_fc_cplh[1]
    DIRECTION OUTPUT ;
    USE SIGNAL ;
    PORT
      LAYER M4 ;
      RECT 0.000 85.104 0.072 85.128 ;
    END
  END cfg_fc_cplh[1]
  PIN cfg_fc_cplh[2]
    DIRECTION OUTPUT ;
    USE SIGNAL ;
    PORT
      LAYER M4 ;
      RECT 0.000 85.248 0.072 85.272 ;
    END
  END cfg_fc_cplh[2]
  PIN cfg_fc_cplh[3]
    DIRECTION OUTPUT ;
    USE SIGNAL ;
    PORT
      LAYER M4 ;
      RECT 0.000 85.392 0.072 85.416 ;
    END
  END cfg_fc_cplh[3]
  PIN cfg_fc_cplh[4]
    DIRECTION OUTPUT ;
    USE SIGNAL ;
    PORT
      LAYER M4 ;
      RECT 0.000 85.536 0.072 85.560 ;
    END
  END cfg_fc_cplh[4]
  PIN cfg_fc_cplh[5]
    DIRECTION OUTPUT ;
    USE SIGNAL ;
    PORT
      LAYER M4 ;
      RECT 0.000 85.680 0.072 85.704 ;
    END
  END cfg_fc_cplh[5]
  PIN cfg_fc_cplh[6]
    DIRECTION OUTPUT ;
    USE SIGNAL ;
    PORT
      LAYER M4 ;
      RECT 0.000 85.824 0.072 85.848 ;
    END
  END cfg_fc_cplh[6]
  PIN cfg_fc_cplh[7]
    DIRECTION OUTPUT ;
    USE SIGNAL ;
    PORT
      LAYER M4 ;
      RECT 0.000 85.968 0.072 85.992 ;
    END
  END cfg_fc_cplh[7]
  PIN cfg_fc_npd[0]
    DIRECTION OUTPUT ;
    USE SIGNAL ;
    PORT
      LAYER M4 ;
      RECT 0.000 86.112 0.072 86.136 ;
    END
  END cfg_fc_npd[0]
  PIN cfg_fc_npd[1]
    DIRECTION OUTPUT ;
    USE SIGNAL ;
    PORT
      LAYER M4 ;
      RECT 0.000 86.256 0.072 86.280 ;
    END
  END cfg_fc_npd[1]
  PIN cfg_fc_npd[2]
    DIRECTION OUTPUT ;
    USE SIGNAL ;
    PORT
      LAYER M4 ;
      RECT 0.000 86.400 0.072 86.424 ;
    END
  END cfg_fc_npd[2]
  PIN cfg_fc_npd[3]
    DIRECTION OUTPUT ;
    USE SIGNAL ;
    PORT
      LAYER M4 ;
      RECT 0.000 86.544 0.072 86.568 ;
    END
  END cfg_fc_npd[3]
  PIN cfg_fc_npd[4]
    DIRECTION OUTPUT ;
    USE SIGNAL ;
    PORT
      LAYER M4 ;
      RECT 0.000 86.688 0.072 86.712 ;
    END
  END cfg_fc_npd[4]
  PIN cfg_fc_npd[5]
    DIRECTION OUTPUT ;
    USE SIGNAL ;
    PORT
      LAYER M4 ;
      RECT 0.000 86.832 0.072 86.856 ;
    END
  END cfg_fc_npd[5]
  PIN cfg_fc_npd[6]
    DIRECTION OUTPUT ;
    USE SIGNAL ;
    PORT
      LAYER M4 ;
      RECT 0.000 86.976 0.072 87.000 ;
    END
  END cfg_fc_npd[6]
  PIN cfg_fc_npd[7]
    DIRECTION OUTPUT ;
    USE SIGNAL ;
    PORT
      LAYER M4 ;
      RECT 0.000 87.120 0.072 87.144 ;
    END
  END cfg_fc_npd[7]
  PIN cfg_fc_npd[8]
    DIRECTION OUTPUT ;
    USE SIGNAL ;
    PORT
      LAYER M4 ;
      RECT 0.000 87.264 0.072 87.288 ;
    END
  END cfg_fc_npd[8]
  PIN cfg_fc_npd[9]
    DIRECTION OUTPUT ;
    USE SIGNAL ;
    PORT
      LAYER M4 ;
      RECT 0.000 87.408 0.072 87.432 ;
    END
  END cfg_fc_npd[9]
  PIN cfg_fc_npd[10]
    DIRECTION OUTPUT ;
    USE SIGNAL ;
    PORT
      LAYER M4 ;
      RECT 0.000 87.552 0.072 87.576 ;
    END
  END cfg_fc_npd[10]
  PIN cfg_fc_npd[11]
    DIRECTION OUTPUT ;
    USE SIGNAL ;
    PORT
      LAYER M4 ;
      RECT 0.000 87.696 0.072 87.720 ;
    END
  END cfg_fc_npd[11]
  PIN cfg_fc_nph[0]
    DIRECTION OUTPUT ;
    USE SIGNAL ;
    PORT
      LAYER M4 ;
      RECT 0.000 87.840 0.072 87.864 ;
    END
  END cfg_fc_nph[0]
  PIN cfg_fc_nph[1]
    DIRECTION OUTPUT ;
    USE SIGNAL ;
    PORT
      LAYER M4 ;
      RECT 0.000 87.984 0.072 88.008 ;
    END
  END cfg_fc_nph[1]
  PIN cfg_fc_nph[2]
    DIRECTION OUTPUT ;
    USE SIGNAL ;
    PORT
      LAYER M4 ;
      RECT 0.000 88.128 0.072 88.152 ;
    END
  END cfg_fc_nph[2]
  PIN cfg_fc_nph[3]
    DIRECTION OUTPUT ;
    USE SIGNAL ;
    PORT
      LAYER M4 ;
      RECT 0.000 88.272 0.072 88.296 ;
    END
  END cfg_fc_nph[3]
  PIN cfg_fc_nph[4]
    DIRECTION OUTPUT ;
    USE SIGNAL ;
    PORT
      LAYER M4 ;
      RECT 0.000 88.416 0.072 88.440 ;
    END
  END cfg_fc_nph[4]
  PIN cfg_fc_nph[5]
    DIRECTION OUTPUT ;
    USE SIGNAL ;
    PORT
      LAYER M4 ;
      RECT 0.000 88.560 0.072 88.584 ;
    END
  END cfg_fc_nph[5]
  PIN cfg_fc_nph[6]
    DIRECTION OUTPUT ;
    USE SIGNAL ;
    PORT
      LAYER M4 ;
      RECT 0.000 88.704 0.072 88.728 ;
    END
  END cfg_fc_nph[6]
  PIN cfg_fc_nph[7]
    DIRECTION OUTPUT ;
    USE SIGNAL ;
    PORT
      LAYER M4 ;
      RECT 0.000 88.848 0.072 88.872 ;
    END
  END cfg_fc_nph[7]
  PIN cfg_fc_pd[0]
    DIRECTION OUTPUT ;
    USE SIGNAL ;
    PORT
      LAYER M4 ;
      RECT 0.000 88.992 0.072 89.016 ;
    END
  END cfg_fc_pd[0]
  PIN cfg_fc_pd[1]
    DIRECTION OUTPUT ;
    USE SIGNAL ;
    PORT
      LAYER M4 ;
      RECT 0.000 89.136 0.072 89.160 ;
    END
  END cfg_fc_pd[1]
  PIN cfg_fc_pd[2]
    DIRECTION OUTPUT ;
    USE SIGNAL ;
    PORT
      LAYER M4 ;
      RECT 0.000 89.280 0.072 89.304 ;
    END
  END cfg_fc_pd[2]
  PIN cfg_fc_pd[3]
    DIRECTION OUTPUT ;
    USE SIGNAL ;
    PORT
      LAYER M4 ;
      RECT 0.000 89.424 0.072 89.448 ;
    END
  END cfg_fc_pd[3]
  PIN cfg_fc_pd[4]
    DIRECTION OUTPUT ;
    USE SIGNAL ;
    PORT
      LAYER M4 ;
      RECT 0.000 89.568 0.072 89.592 ;
    END
  END cfg_fc_pd[4]
  PIN cfg_fc_pd[5]
    DIRECTION OUTPUT ;
    USE SIGNAL ;
    PORT
      LAYER M4 ;
      RECT 0.000 89.712 0.072 89.736 ;
    END
  END cfg_fc_pd[5]
  PIN cfg_fc_pd[6]
    DIRECTION OUTPUT ;
    USE SIGNAL ;
    PORT
      LAYER M4 ;
      RECT 0.000 89.856 0.072 89.880 ;
    END
  END cfg_fc_pd[6]
  PIN cfg_fc_pd[7]
    DIRECTION OUTPUT ;
    USE SIGNAL ;
    PORT
      LAYER M4 ;
      RECT 0.000 90.000 0.072 90.024 ;
    END
  END cfg_fc_pd[7]
  PIN cfg_fc_pd[8]
    DIRECTION OUTPUT ;
    USE SIGNAL ;
    PORT
      LAYER M4 ;
      RECT 0.000 90.144 0.072 90.168 ;
    END
  END cfg_fc_pd[8]
  PIN cfg_fc_pd[9]
    DIRECTION OUTPUT ;
    USE SIGNAL ;
    PORT
      LAYER M4 ;
      RECT 0.000 90.288 0.072 90.312 ;
    END
  END cfg_fc_pd[9]
  PIN cfg_fc_pd[10]
    DIRECTION OUTPUT ;
    USE SIGNAL ;
    PORT
      LAYER M4 ;
      RECT 0.000 90.432 0.072 90.456 ;
    END
  END cfg_fc_pd[10]
  PIN cfg_fc_pd[11]
    DIRECTION OUTPUT ;
    USE SIGNAL ;
    PORT
      LAYER M4 ;
      RECT 0.000 90.576 0.072 90.600 ;
    END
  END cfg_fc_pd[11]
  PIN cfg_fc_ph[0]
    DIRECTION OUTPUT ;
    USE SIGNAL ;
    PORT
      LAYER M4 ;
      RECT 0.000 90.720 0.072 90.744 ;
    END
  END cfg_fc_ph[0]
  PIN cfg_fc_ph[1]
    DIRECTION OUTPUT ;
    USE SIGNAL ;
    PORT
      LAYER M4 ;
      RECT 0.000 90.864 0.072 90.888 ;
    END
  END cfg_fc_ph[1]
  PIN cfg_fc_ph[2]
    DIRECTION OUTPUT ;
    USE SIGNAL ;
    PORT
      LAYER M4 ;
      RECT 0.000 91.008 0.072 91.032 ;
    END
  END cfg_fc_ph[2]
  PIN cfg_fc_ph[3]
    DIRECTION OUTPUT ;
    USE SIGNAL ;
    PORT
      LAYER M4 ;
      RECT 0.000 91.152 0.072 91.176 ;
    END
  END cfg_fc_ph[3]
  PIN cfg_fc_ph[4]
    DIRECTION OUTPUT ;
    USE SIGNAL ;
    PORT
      LAYER M4 ;
      RECT 0.000 91.296 0.072 91.320 ;
    END
  END cfg_fc_ph[4]
  PIN cfg_fc_ph[5]
    DIRECTION OUTPUT ;
    USE SIGNAL ;
    PORT
      LAYER M4 ;
      RECT 0.000 91.440 0.072 91.464 ;
    END
  END cfg_fc_ph[5]
  PIN cfg_fc_ph[6]
    DIRECTION OUTPUT ;
    USE SIGNAL ;
    PORT
      LAYER M4 ;
      RECT 0.000 91.584 0.072 91.608 ;
    END
  END cfg_fc_ph[6]
  PIN cfg_fc_ph[7]
    DIRECTION OUTPUT ;
    USE SIGNAL ;
    PORT
      LAYER M4 ;
      RECT 0.000 91.728 0.072 91.752 ;
    END
  END cfg_fc_ph[7]
  PIN cfg_flr_in_process[0]
    DIRECTION OUTPUT ;
    USE SIGNAL ;
    PORT
      LAYER M4 ;
      RECT 0.000 91.872 0.072 91.896 ;
    END
  END cfg_flr_in_process[0]
  PIN cfg_flr_in_process[1]
    DIRECTION OUTPUT ;
    USE SIGNAL ;
    PORT
      LAYER M4 ;
      RECT 0.000 92.016 0.072 92.040 ;
    END
  END cfg_flr_in_process[1]
  PIN cfg_flr_in_process[2]
    DIRECTION OUTPUT ;
    USE SIGNAL ;
    PORT
      LAYER M4 ;
      RECT 0.000 92.160 0.072 92.184 ;
    END
  END cfg_flr_in_process[2]
  PIN cfg_flr_in_process[3]
    DIRECTION OUTPUT ;
    USE SIGNAL ;
    PORT
      LAYER M4 ;
      RECT 0.000 92.304 0.072 92.328 ;
    END
  END cfg_flr_in_process[3]
  PIN cfg_function_power_state[0]
    DIRECTION OUTPUT ;
    USE SIGNAL ;
    PORT
      LAYER M4 ;
      RECT 0.000 92.448 0.072 92.472 ;
    END
  END cfg_function_power_state[0]
  PIN cfg_function_power_state[1]
    DIRECTION OUTPUT ;
    USE SIGNAL ;
    PORT
      LAYER M4 ;
      RECT 0.000 92.592 0.072 92.616 ;
    END
  END cfg_function_power_state[1]
  PIN cfg_function_power_state[2]
    DIRECTION OUTPUT ;
    USE SIGNAL ;
    PORT
      LAYER M4 ;
      RECT 0.000 92.736 0.072 92.760 ;
    END
  END cfg_function_power_state[2]
  PIN cfg_function_power_state[3]
    DIRECTION OUTPUT ;
    USE SIGNAL ;
    PORT
      LAYER M4 ;
      RECT 0.000 92.880 0.072 92.904 ;
    END
  END cfg_function_power_state[3]
  PIN cfg_function_power_state[4]
    DIRECTION OUTPUT ;
    USE SIGNAL ;
    PORT
      LAYER M4 ;
      RECT 0.000 93.024 0.072 93.048 ;
    END
  END cfg_function_power_state[4]
  PIN cfg_function_power_state[5]
    DIRECTION OUTPUT ;
    USE SIGNAL ;
    PORT
      LAYER M4 ;
      RECT 0.000 93.168 0.072 93.192 ;
    END
  END cfg_function_power_state[5]
  PIN cfg_function_power_state[6]
    DIRECTION OUTPUT ;
    USE SIGNAL ;
    PORT
      LAYER M4 ;
      RECT 0.000 93.312 0.072 93.336 ;
    END
  END cfg_function_power_state[6]
  PIN cfg_function_power_state[7]
    DIRECTION OUTPUT ;
    USE SIGNAL ;
    PORT
      LAYER M4 ;
      RECT 0.000 93.456 0.072 93.480 ;
    END
  END cfg_function_power_state[7]
  PIN cfg_function_power_state[8]
    DIRECTION OUTPUT ;
    USE SIGNAL ;
    PORT
      LAYER M4 ;
      RECT 0.000 93.600 0.072 93.624 ;
    END
  END cfg_function_power_state[8]
  PIN cfg_function_power_state[9]
    DIRECTION OUTPUT ;
    USE SIGNAL ;
    PORT
      LAYER M4 ;
      RECT 0.000 93.744 0.072 93.768 ;
    END
  END cfg_function_power_state[9]
  PIN cfg_function_power_state[10]
    DIRECTION OUTPUT ;
    USE SIGNAL ;
    PORT
      LAYER M4 ;
      RECT 0.000 93.888 0.072 93.912 ;
    END
  END cfg_function_power_state[10]
  PIN cfg_function_power_state[11]
    DIRECTION OUTPUT ;
    USE SIGNAL ;
    PORT
      LAYER M4 ;
      RECT 0.000 94.032 0.072 94.056 ;
    END
  END cfg_function_power_state[11]
  PIN cfg_function_status[0]
    DIRECTION OUTPUT ;
    USE SIGNAL ;
    PORT
      LAYER M4 ;
      RECT 199.928 0.288 200.000 0.312 ;
    END
  END cfg_function_status[0]
  PIN cfg_function_status[1]
    DIRECTION OUTPUT ;
    USE SIGNAL ;
    PORT
      LAYER M4 ;
      RECT 199.928 0.432 200.000 0.456 ;
    END
  END cfg_function_status[1]
  PIN cfg_function_status[2]
    DIRECTION OUTPUT ;
    USE SIGNAL ;
    PORT
      LAYER M4 ;
      RECT 199.928 0.576 200.000 0.600 ;
    END
  END cfg_function_status[2]
  PIN cfg_function_status[3]
    DIRECTION OUTPUT ;
    USE SIGNAL ;
    PORT
      LAYER M4 ;
      RECT 199.928 0.720 200.000 0.744 ;
    END
  END cfg_function_status[3]
  PIN cfg_function_status[4]
    DIRECTION OUTPUT ;
    USE SIGNAL ;
    PORT
      LAYER M4 ;
      RECT 199.928 0.864 200.000 0.888 ;
    END
  END cfg_function_status[4]
  PIN cfg_function_status[5]
    DIRECTION OUTPUT ;
    USE SIGNAL ;
    PORT
      LAYER M4 ;
      RECT 199.928 1.008 200.000 1.032 ;
    END
  END cfg_function_status[5]
  PIN cfg_function_status[6]
    DIRECTION OUTPUT ;
    USE SIGNAL ;
    PORT
      LAYER M4 ;
      RECT 199.928 1.152 200.000 1.176 ;
    END
  END cfg_function_status[6]
  PIN cfg_function_status[7]
    DIRECTION OUTPUT ;
    USE SIGNAL ;
    PORT
      LAYER M4 ;
      RECT 199.928 1.296 200.000 1.320 ;
    END
  END cfg_function_status[7]
  PIN cfg_function_status[8]
    DIRECTION OUTPUT ;
    USE SIGNAL ;
    PORT
      LAYER M4 ;
      RECT 199.928 1.440 200.000 1.464 ;
    END
  END cfg_function_status[8]
  PIN cfg_function_status[9]
    DIRECTION OUTPUT ;
    USE SIGNAL ;
    PORT
      LAYER M4 ;
      RECT 199.928 1.584 200.000 1.608 ;
    END
  END cfg_function_status[9]
  PIN cfg_function_status[10]
    DIRECTION OUTPUT ;
    USE SIGNAL ;
    PORT
      LAYER M4 ;
      RECT 199.928 1.728 200.000 1.752 ;
    END
  END cfg_function_status[10]
  PIN cfg_function_status[11]
    DIRECTION OUTPUT ;
    USE SIGNAL ;
    PORT
      LAYER M4 ;
      RECT 199.928 1.872 200.000 1.896 ;
    END
  END cfg_function_status[11]
  PIN cfg_function_status[12]
    DIRECTION OUTPUT ;
    USE SIGNAL ;
    PORT
      LAYER M4 ;
      RECT 199.928 2.016 200.000 2.040 ;
    END
  END cfg_function_status[12]
  PIN cfg_function_status[13]
    DIRECTION OUTPUT ;
    USE SIGNAL ;
    PORT
      LAYER M4 ;
      RECT 199.928 2.160 200.000 2.184 ;
    END
  END cfg_function_status[13]
  PIN cfg_function_status[14]
    DIRECTION OUTPUT ;
    USE SIGNAL ;
    PORT
      LAYER M4 ;
      RECT 199.928 2.304 200.000 2.328 ;
    END
  END cfg_function_status[14]
  PIN cfg_function_status[15]
    DIRECTION OUTPUT ;
    USE SIGNAL ;
    PORT
      LAYER M4 ;
      RECT 199.928 2.448 200.000 2.472 ;
    END
  END cfg_function_status[15]
  PIN cfg_hot_reset_out
    DIRECTION OUTPUT ;
    USE SIGNAL ;
    PORT
      LAYER M4 ;
      RECT 199.928 2.592 200.000 2.616 ;
    END
  END cfg_hot_reset_out
  PIN cfg_interrupt_msi_data[0]
    DIRECTION OUTPUT ;
    USE SIGNAL ;
    PORT
      LAYER M4 ;
      RECT 199.928 2.736 200.000 2.760 ;
    END
  END cfg_interrupt_msi_data[0]
  PIN cfg_interrupt_msi_data[1]
    DIRECTION OUTPUT ;
    USE SIGNAL ;
    PORT
      LAYER M4 ;
      RECT 199.928 2.880 200.000 2.904 ;
    END
  END cfg_interrupt_msi_data[1]
  PIN cfg_interrupt_msi_data[2]
    DIRECTION OUTPUT ;
    USE SIGNAL ;
    PORT
      LAYER M4 ;
      RECT 199.928 3.024 200.000 3.048 ;
    END
  END cfg_interrupt_msi_data[2]
  PIN cfg_interrupt_msi_data[3]
    DIRECTION OUTPUT ;
    USE SIGNAL ;
    PORT
      LAYER M4 ;
      RECT 199.928 3.168 200.000 3.192 ;
    END
  END cfg_interrupt_msi_data[3]
  PIN cfg_interrupt_msi_data[4]
    DIRECTION OUTPUT ;
    USE SIGNAL ;
    PORT
      LAYER M4 ;
      RECT 199.928 3.312 200.000 3.336 ;
    END
  END cfg_interrupt_msi_data[4]
  PIN cfg_interrupt_msi_data[5]
    DIRECTION OUTPUT ;
    USE SIGNAL ;
    PORT
      LAYER M4 ;
      RECT 199.928 3.456 200.000 3.480 ;
    END
  END cfg_interrupt_msi_data[5]
  PIN cfg_interrupt_msi_data[6]
    DIRECTION OUTPUT ;
    USE SIGNAL ;
    PORT
      LAYER M4 ;
      RECT 199.928 3.600 200.000 3.624 ;
    END
  END cfg_interrupt_msi_data[6]
  PIN cfg_interrupt_msi_data[7]
    DIRECTION OUTPUT ;
    USE SIGNAL ;
    PORT
      LAYER M4 ;
      RECT 199.928 3.744 200.000 3.768 ;
    END
  END cfg_interrupt_msi_data[7]
  PIN cfg_interrupt_msi_data[8]
    DIRECTION OUTPUT ;
    USE SIGNAL ;
    PORT
      LAYER M4 ;
      RECT 199.928 3.888 200.000 3.912 ;
    END
  END cfg_interrupt_msi_data[8]
  PIN cfg_interrupt_msi_data[9]
    DIRECTION OUTPUT ;
    USE SIGNAL ;
    PORT
      LAYER M4 ;
      RECT 199.928 4.032 200.000 4.056 ;
    END
  END cfg_interrupt_msi_data[9]
  PIN cfg_interrupt_msi_data[10]
    DIRECTION OUTPUT ;
    USE SIGNAL ;
    PORT
      LAYER M4 ;
      RECT 199.928 4.176 200.000 4.200 ;
    END
  END cfg_interrupt_msi_data[10]
  PIN cfg_interrupt_msi_data[11]
    DIRECTION OUTPUT ;
    USE SIGNAL ;
    PORT
      LAYER M4 ;
      RECT 199.928 4.320 200.000 4.344 ;
    END
  END cfg_interrupt_msi_data[11]
  PIN cfg_interrupt_msi_data[12]
    DIRECTION OUTPUT ;
    USE SIGNAL ;
    PORT
      LAYER M4 ;
      RECT 199.928 4.464 200.000 4.488 ;
    END
  END cfg_interrupt_msi_data[12]
  PIN cfg_interrupt_msi_data[13]
    DIRECTION OUTPUT ;
    USE SIGNAL ;
    PORT
      LAYER M4 ;
      RECT 199.928 4.608 200.000 4.632 ;
    END
  END cfg_interrupt_msi_data[13]
  PIN cfg_interrupt_msi_data[14]
    DIRECTION OUTPUT ;
    USE SIGNAL ;
    PORT
      LAYER M4 ;
      RECT 199.928 4.752 200.000 4.776 ;
    END
  END cfg_interrupt_msi_data[14]
  PIN cfg_interrupt_msi_data[15]
    DIRECTION OUTPUT ;
    USE SIGNAL ;
    PORT
      LAYER M4 ;
      RECT 199.928 4.896 200.000 4.920 ;
    END
  END cfg_interrupt_msi_data[15]
  PIN cfg_interrupt_msi_data[16]
    DIRECTION OUTPUT ;
    USE SIGNAL ;
    PORT
      LAYER M4 ;
      RECT 199.928 5.040 200.000 5.064 ;
    END
  END cfg_interrupt_msi_data[16]
  PIN cfg_interrupt_msi_data[17]
    DIRECTION OUTPUT ;
    USE SIGNAL ;
    PORT
      LAYER M4 ;
      RECT 199.928 5.184 200.000 5.208 ;
    END
  END cfg_interrupt_msi_data[17]
  PIN cfg_interrupt_msi_data[18]
    DIRECTION OUTPUT ;
    USE SIGNAL ;
    PORT
      LAYER M4 ;
      RECT 199.928 5.328 200.000 5.352 ;
    END
  END cfg_interrupt_msi_data[18]
  PIN cfg_interrupt_msi_data[19]
    DIRECTION OUTPUT ;
    USE SIGNAL ;
    PORT
      LAYER M4 ;
      RECT 199.928 5.472 200.000 5.496 ;
    END
  END cfg_interrupt_msi_data[19]
  PIN cfg_interrupt_msi_data[20]
    DIRECTION OUTPUT ;
    USE SIGNAL ;
    PORT
      LAYER M4 ;
      RECT 199.928 5.616 200.000 5.640 ;
    END
  END cfg_interrupt_msi_data[20]
  PIN cfg_interrupt_msi_data[21]
    DIRECTION OUTPUT ;
    USE SIGNAL ;
    PORT
      LAYER M4 ;
      RECT 199.928 5.760 200.000 5.784 ;
    END
  END cfg_interrupt_msi_data[21]
  PIN cfg_interrupt_msi_data[22]
    DIRECTION OUTPUT ;
    USE SIGNAL ;
    PORT
      LAYER M4 ;
      RECT 199.928 5.904 200.000 5.928 ;
    END
  END cfg_interrupt_msi_data[22]
  PIN cfg_interrupt_msi_data[23]
    DIRECTION OUTPUT ;
    USE SIGNAL ;
    PORT
      LAYER M4 ;
      RECT 199.928 6.048 200.000 6.072 ;
    END
  END cfg_interrupt_msi_data[23]
  PIN cfg_interrupt_msi_data[24]
    DIRECTION OUTPUT ;
    USE SIGNAL ;
    PORT
      LAYER M4 ;
      RECT 199.928 6.192 200.000 6.216 ;
    END
  END cfg_interrupt_msi_data[24]
  PIN cfg_interrupt_msi_data[25]
    DIRECTION OUTPUT ;
    USE SIGNAL ;
    PORT
      LAYER M4 ;
      RECT 199.928 6.336 200.000 6.360 ;
    END
  END cfg_interrupt_msi_data[25]
  PIN cfg_interrupt_msi_data[26]
    DIRECTION OUTPUT ;
    USE SIGNAL ;
    PORT
      LAYER M4 ;
      RECT 199.928 6.480 200.000 6.504 ;
    END
  END cfg_interrupt_msi_data[26]
  PIN cfg_interrupt_msi_data[27]
    DIRECTION OUTPUT ;
    USE SIGNAL ;
    PORT
      LAYER M4 ;
      RECT 199.928 6.624 200.000 6.648 ;
    END
  END cfg_interrupt_msi_data[27]
  PIN cfg_interrupt_msi_data[28]
    DIRECTION OUTPUT ;
    USE SIGNAL ;
    PORT
      LAYER M4 ;
      RECT 199.928 6.768 200.000 6.792 ;
    END
  END cfg_interrupt_msi_data[28]
  PIN cfg_interrupt_msi_data[29]
    DIRECTION OUTPUT ;
    USE SIGNAL ;
    PORT
      LAYER M4 ;
      RECT 199.928 6.912 200.000 6.936 ;
    END
  END cfg_interrupt_msi_data[29]
  PIN cfg_interrupt_msi_data[30]
    DIRECTION OUTPUT ;
    USE SIGNAL ;
    PORT
      LAYER M4 ;
      RECT 199.928 7.056 200.000 7.080 ;
    END
  END cfg_interrupt_msi_data[30]
  PIN cfg_interrupt_msi_data[31]
    DIRECTION OUTPUT ;
    USE SIGNAL ;
    PORT
      LAYER M4 ;
      RECT 199.928 7.200 200.000 7.224 ;
    END
  END cfg_interrupt_msi_data[31]
  PIN cfg_interrupt_msi_enable[0]
    DIRECTION OUTPUT ;
    USE SIGNAL ;
    PORT
      LAYER M4 ;
      RECT 199.928 7.344 200.000 7.368 ;
    END
  END cfg_interrupt_msi_enable[0]
  PIN cfg_interrupt_msi_enable[1]
    DIRECTION OUTPUT ;
    USE SIGNAL ;
    PORT
      LAYER M4 ;
      RECT 199.928 7.488 200.000 7.512 ;
    END
  END cfg_interrupt_msi_enable[1]
  PIN cfg_interrupt_msi_enable[2]
    DIRECTION OUTPUT ;
    USE SIGNAL ;
    PORT
      LAYER M4 ;
      RECT 199.928 7.632 200.000 7.656 ;
    END
  END cfg_interrupt_msi_enable[2]
  PIN cfg_interrupt_msi_enable[3]
    DIRECTION OUTPUT ;
    USE SIGNAL ;
    PORT
      LAYER M4 ;
      RECT 199.928 7.776 200.000 7.800 ;
    END
  END cfg_interrupt_msi_enable[3]
  PIN cfg_interrupt_msi_fail
    DIRECTION OUTPUT ;
    USE SIGNAL ;
    PORT
      LAYER M4 ;
      RECT 199.928 7.920 200.000 7.944 ;
    END
  END cfg_interrupt_msi_fail
  PIN cfg_interrupt_msi_mask_update
    DIRECTION OUTPUT ;
    USE SIGNAL ;
    PORT
      LAYER M4 ;
      RECT 199.928 8.064 200.000 8.088 ;
    END
  END cfg_interrupt_msi_mask_update
  PIN cfg_interrupt_msi_mmenable[0]
    DIRECTION OUTPUT ;
    USE SIGNAL ;
    PORT
      LAYER M4 ;
      RECT 199.928 8.208 200.000 8.232 ;
    END
  END cfg_interrupt_msi_mmenable[0]
  PIN cfg_interrupt_msi_mmenable[1]
    DIRECTION OUTPUT ;
    USE SIGNAL ;
    PORT
      LAYER M4 ;
      RECT 199.928 8.352 200.000 8.376 ;
    END
  END cfg_interrupt_msi_mmenable[1]
  PIN cfg_interrupt_msi_mmenable[2]
    DIRECTION OUTPUT ;
    USE SIGNAL ;
    PORT
      LAYER M4 ;
      RECT 199.928 8.496 200.000 8.520 ;
    END
  END cfg_interrupt_msi_mmenable[2]
  PIN cfg_interrupt_msi_mmenable[3]
    DIRECTION OUTPUT ;
    USE SIGNAL ;
    PORT
      LAYER M4 ;
      RECT 199.928 8.640 200.000 8.664 ;
    END
  END cfg_interrupt_msi_mmenable[3]
  PIN cfg_interrupt_msi_mmenable[4]
    DIRECTION OUTPUT ;
    USE SIGNAL ;
    PORT
      LAYER M4 ;
      RECT 199.928 8.784 200.000 8.808 ;
    END
  END cfg_interrupt_msi_mmenable[4]
  PIN cfg_interrupt_msi_mmenable[5]
    DIRECTION OUTPUT ;
    USE SIGNAL ;
    PORT
      LAYER M4 ;
      RECT 199.928 8.928 200.000 8.952 ;
    END
  END cfg_interrupt_msi_mmenable[5]
  PIN cfg_interrupt_msi_mmenable[6]
    DIRECTION OUTPUT ;
    USE SIGNAL ;
    PORT
      LAYER M4 ;
      RECT 199.928 9.072 200.000 9.096 ;
    END
  END cfg_interrupt_msi_mmenable[6]
  PIN cfg_interrupt_msi_mmenable[7]
    DIRECTION OUTPUT ;
    USE SIGNAL ;
    PORT
      LAYER M4 ;
      RECT 199.928 9.216 200.000 9.240 ;
    END
  END cfg_interrupt_msi_mmenable[7]
  PIN cfg_interrupt_msi_mmenable[8]
    DIRECTION OUTPUT ;
    USE SIGNAL ;
    PORT
      LAYER M4 ;
      RECT 199.928 9.360 200.000 9.384 ;
    END
  END cfg_interrupt_msi_mmenable[8]
  PIN cfg_interrupt_msi_mmenable[9]
    DIRECTION OUTPUT ;
    USE SIGNAL ;
    PORT
      LAYER M4 ;
      RECT 199.928 9.504 200.000 9.528 ;
    END
  END cfg_interrupt_msi_mmenable[9]
  PIN cfg_interrupt_msi_mmenable[10]
    DIRECTION OUTPUT ;
    USE SIGNAL ;
    PORT
      LAYER M4 ;
      RECT 199.928 9.648 200.000 9.672 ;
    END
  END cfg_interrupt_msi_mmenable[10]
  PIN cfg_interrupt_msi_mmenable[11]
    DIRECTION OUTPUT ;
    USE SIGNAL ;
    PORT
      LAYER M4 ;
      RECT 199.928 9.792 200.000 9.816 ;
    END
  END cfg_interrupt_msi_mmenable[11]
  PIN cfg_interrupt_msi_sent
    DIRECTION OUTPUT ;
    USE SIGNAL ;
    PORT
      LAYER M4 ;
      RECT 199.928 9.936 200.000 9.960 ;
    END
  END cfg_interrupt_msi_sent
  PIN cfg_interrupt_sent
    DIRECTION OUTPUT ;
    USE SIGNAL ;
    PORT
      LAYER M4 ;
      RECT 199.928 10.080 200.000 10.104 ;
    END
  END cfg_interrupt_sent
  PIN cfg_link_power_state[0]
    DIRECTION OUTPUT ;
    USE SIGNAL ;
    PORT
      LAYER M4 ;
      RECT 199.928 10.224 200.000 10.248 ;
    END
  END cfg_link_power_state[0]
  PIN cfg_link_power_state[1]
    DIRECTION OUTPUT ;
    USE SIGNAL ;
    PORT
      LAYER M4 ;
      RECT 199.928 10.368 200.000 10.392 ;
    END
  END cfg_link_power_state[1]
  PIN cfg_local_error
    DIRECTION OUTPUT ;
    USE SIGNAL ;
    PORT
      LAYER M4 ;
      RECT 199.928 10.512 200.000 10.536 ;
    END
  END cfg_local_error
  PIN cfg_ltr_enable
    DIRECTION OUTPUT ;
    USE SIGNAL ;
    PORT
      LAYER M4 ;
      RECT 199.928 10.656 200.000 10.680 ;
    END
  END cfg_ltr_enable
  PIN cfg_ltssm_state[0]
    DIRECTION OUTPUT ;
    USE SIGNAL ;
    PORT
      LAYER M4 ;
      RECT 199.928 10.800 200.000 10.824 ;
    END
  END cfg_ltssm_state[0]
  PIN cfg_ltssm_state[1]
    DIRECTION OUTPUT ;
    USE SIGNAL ;
    PORT
      LAYER M4 ;
      RECT 199.928 10.944 200.000 10.968 ;
    END
  END cfg_ltssm_state[1]
  PIN cfg_ltssm_state[2]
    DIRECTION OUTPUT ;
    USE SIGNAL ;
    PORT
      LAYER M4 ;
      RECT 199.928 11.088 200.000 11.112 ;
    END
  END cfg_ltssm_state[2]
  PIN cfg_ltssm_state[3]
    DIRECTION OUTPUT ;
    USE SIGNAL ;
    PORT
      LAYER M4 ;
      RECT 199.928 11.232 200.000 11.256 ;
    END
  END cfg_ltssm_state[3]
  PIN cfg_ltssm_state[4]
    DIRECTION OUTPUT ;
    USE SIGNAL ;
    PORT
      LAYER M4 ;
      RECT 199.928 11.376 200.000 11.400 ;
    END
  END cfg_ltssm_state[4]
  PIN cfg_ltssm_state[5]
    DIRECTION OUTPUT ;
    USE SIGNAL ;
    PORT
      LAYER M4 ;
      RECT 199.928 11.520 200.000 11.544 ;
    END
  END cfg_ltssm_state[5]
  PIN cfg_max_payload[0]
    DIRECTION OUTPUT ;
    USE SIGNAL ;
    PORT
      LAYER M4 ;
      RECT 199.928 11.664 200.000 11.688 ;
    END
  END cfg_max_payload[0]
  PIN cfg_max_payload[1]
    DIRECTION OUTPUT ;
    USE SIGNAL ;
    PORT
      LAYER M4 ;
      RECT 199.928 11.808 200.000 11.832 ;
    END
  END cfg_max_payload[1]
  PIN cfg_max_payload[2]
    DIRECTION OUTPUT ;
    USE SIGNAL ;
    PORT
      LAYER M4 ;
      RECT 199.928 11.952 200.000 11.976 ;
    END
  END cfg_max_payload[2]
  PIN cfg_max_read_req[0]
    DIRECTION OUTPUT ;
    USE SIGNAL ;
    PORT
      LAYER M4 ;
      RECT 199.928 12.096 200.000 12.120 ;
    END
  END cfg_max_read_req[0]
  PIN cfg_max_read_req[1]
    DIRECTION OUTPUT ;
    USE SIGNAL ;
    PORT
      LAYER M4 ;
      RECT 199.928 12.240 200.000 12.264 ;
    END
  END cfg_max_read_req[1]
  PIN cfg_max_read_req[2]
    DIRECTION OUTPUT ;
    USE SIGNAL ;
    PORT
      LAYER M4 ;
      RECT 199.928 12.384 200.000 12.408 ;
    END
  END cfg_max_read_req[2]
  PIN cfg_mgmt_read_data[0]
    DIRECTION OUTPUT ;
    USE SIGNAL ;
    PORT
      LAYER M4 ;
      RECT 199.928 12.528 200.000 12.552 ;
    END
  END cfg_mgmt_read_data[0]
  PIN cfg_mgmt_read_data[1]
    DIRECTION OUTPUT ;
    USE SIGNAL ;
    PORT
      LAYER M4 ;
      RECT 199.928 12.672 200.000 12.696 ;
    END
  END cfg_mgmt_read_data[1]
  PIN cfg_mgmt_read_data[2]
    DIRECTION OUTPUT ;
    USE SIGNAL ;
    PORT
      LAYER M4 ;
      RECT 199.928 12.816 200.000 12.840 ;
    END
  END cfg_mgmt_read_data[2]
  PIN cfg_mgmt_read_data[3]
    DIRECTION OUTPUT ;
    USE SIGNAL ;
    PORT
      LAYER M4 ;
      RECT 199.928 12.960 200.000 12.984 ;
    END
  END cfg_mgmt_read_data[3]
  PIN cfg_mgmt_read_data[4]
    DIRECTION OUTPUT ;
    USE SIGNAL ;
    PORT
      LAYER M4 ;
      RECT 199.928 13.104 200.000 13.128 ;
    END
  END cfg_mgmt_read_data[4]
  PIN cfg_mgmt_read_data[5]
    DIRECTION OUTPUT ;
    USE SIGNAL ;
    PORT
      LAYER M4 ;
      RECT 199.928 13.248 200.000 13.272 ;
    END
  END cfg_mgmt_read_data[5]
  PIN cfg_mgmt_read_data[6]
    DIRECTION OUTPUT ;
    USE SIGNAL ;
    PORT
      LAYER M4 ;
      RECT 199.928 13.392 200.000 13.416 ;
    END
  END cfg_mgmt_read_data[6]
  PIN cfg_mgmt_read_data[7]
    DIRECTION OUTPUT ;
    USE SIGNAL ;
    PORT
      LAYER M4 ;
      RECT 199.928 13.536 200.000 13.560 ;
    END
  END cfg_mgmt_read_data[7]
  PIN cfg_mgmt_read_data[8]
    DIRECTION OUTPUT ;
    USE SIGNAL ;
    PORT
      LAYER M4 ;
      RECT 199.928 13.680 200.000 13.704 ;
    END
  END cfg_mgmt_read_data[8]
  PIN cfg_mgmt_read_data[9]
    DIRECTION OUTPUT ;
    USE SIGNAL ;
    PORT
      LAYER M4 ;
      RECT 199.928 13.824 200.000 13.848 ;
    END
  END cfg_mgmt_read_data[9]
  PIN cfg_mgmt_read_data[10]
    DIRECTION OUTPUT ;
    USE SIGNAL ;
    PORT
      LAYER M4 ;
      RECT 199.928 13.968 200.000 13.992 ;
    END
  END cfg_mgmt_read_data[10]
  PIN cfg_mgmt_read_data[11]
    DIRECTION OUTPUT ;
    USE SIGNAL ;
    PORT
      LAYER M4 ;
      RECT 199.928 14.112 200.000 14.136 ;
    END
  END cfg_mgmt_read_data[11]
  PIN cfg_mgmt_read_data[12]
    DIRECTION OUTPUT ;
    USE SIGNAL ;
    PORT
      LAYER M4 ;
      RECT 199.928 14.256 200.000 14.280 ;
    END
  END cfg_mgmt_read_data[12]
  PIN cfg_mgmt_read_data[13]
    DIRECTION OUTPUT ;
    USE SIGNAL ;
    PORT
      LAYER M4 ;
      RECT 199.928 14.400 200.000 14.424 ;
    END
  END cfg_mgmt_read_data[13]
  PIN cfg_mgmt_read_data[14]
    DIRECTION OUTPUT ;
    USE SIGNAL ;
    PORT
      LAYER M4 ;
      RECT 199.928 14.544 200.000 14.568 ;
    END
  END cfg_mgmt_read_data[14]
  PIN cfg_mgmt_read_data[15]
    DIRECTION OUTPUT ;
    USE SIGNAL ;
    PORT
      LAYER M4 ;
      RECT 199.928 14.688 200.000 14.712 ;
    END
  END cfg_mgmt_read_data[15]
  PIN cfg_mgmt_read_data[16]
    DIRECTION OUTPUT ;
    USE SIGNAL ;
    PORT
      LAYER M4 ;
      RECT 199.928 14.832 200.000 14.856 ;
    END
  END cfg_mgmt_read_data[16]
  PIN cfg_mgmt_read_data[17]
    DIRECTION OUTPUT ;
    USE SIGNAL ;
    PORT
      LAYER M4 ;
      RECT 199.928 14.976 200.000 15.000 ;
    END
  END cfg_mgmt_read_data[17]
  PIN cfg_mgmt_read_data[18]
    DIRECTION OUTPUT ;
    USE SIGNAL ;
    PORT
      LAYER M4 ;
      RECT 199.928 15.120 200.000 15.144 ;
    END
  END cfg_mgmt_read_data[18]
  PIN cfg_mgmt_read_data[19]
    DIRECTION OUTPUT ;
    USE SIGNAL ;
    PORT
      LAYER M4 ;
      RECT 199.928 15.264 200.000 15.288 ;
    END
  END cfg_mgmt_read_data[19]
  PIN cfg_mgmt_read_data[20]
    DIRECTION OUTPUT ;
    USE SIGNAL ;
    PORT
      LAYER M4 ;
      RECT 199.928 15.408 200.000 15.432 ;
    END
  END cfg_mgmt_read_data[20]
  PIN cfg_mgmt_read_data[21]
    DIRECTION OUTPUT ;
    USE SIGNAL ;
    PORT
      LAYER M4 ;
      RECT 199.928 15.552 200.000 15.576 ;
    END
  END cfg_mgmt_read_data[21]
  PIN cfg_mgmt_read_data[22]
    DIRECTION OUTPUT ;
    USE SIGNAL ;
    PORT
      LAYER M4 ;
      RECT 199.928 15.696 200.000 15.720 ;
    END
  END cfg_mgmt_read_data[22]
  PIN cfg_mgmt_read_data[23]
    DIRECTION OUTPUT ;
    USE SIGNAL ;
    PORT
      LAYER M4 ;
      RECT 199.928 15.840 200.000 15.864 ;
    END
  END cfg_mgmt_read_data[23]
  PIN cfg_mgmt_read_data[24]
    DIRECTION OUTPUT ;
    USE SIGNAL ;
    PORT
      LAYER M4 ;
      RECT 199.928 15.984 200.000 16.008 ;
    END
  END cfg_mgmt_read_data[24]
  PIN cfg_mgmt_read_data[25]
    DIRECTION OUTPUT ;
    USE SIGNAL ;
    PORT
      LAYER M4 ;
      RECT 199.928 16.128 200.000 16.152 ;
    END
  END cfg_mgmt_read_data[25]
  PIN cfg_mgmt_read_data[26]
    DIRECTION OUTPUT ;
    USE SIGNAL ;
    PORT
      LAYER M4 ;
      RECT 199.928 16.272 200.000 16.296 ;
    END
  END cfg_mgmt_read_data[26]
  PIN cfg_mgmt_read_data[27]
    DIRECTION OUTPUT ;
    USE SIGNAL ;
    PORT
      LAYER M4 ;
      RECT 199.928 16.416 200.000 16.440 ;
    END
  END cfg_mgmt_read_data[27]
  PIN cfg_mgmt_read_data[28]
    DIRECTION OUTPUT ;
    USE SIGNAL ;
    PORT
      LAYER M4 ;
      RECT 199.928 16.560 200.000 16.584 ;
    END
  END cfg_mgmt_read_data[28]
  PIN cfg_mgmt_read_data[29]
    DIRECTION OUTPUT ;
    USE SIGNAL ;
    PORT
      LAYER M4 ;
      RECT 199.928 16.704 200.000 16.728 ;
    END
  END cfg_mgmt_read_data[29]
  PIN cfg_mgmt_read_data[30]
    DIRECTION OUTPUT ;
    USE SIGNAL ;
    PORT
      LAYER M4 ;
      RECT 199.928 16.848 200.000 16.872 ;
    END
  END cfg_mgmt_read_data[30]
  PIN cfg_mgmt_read_data[31]
    DIRECTION OUTPUT ;
    USE SIGNAL ;
    PORT
      LAYER M4 ;
      RECT 199.928 16.992 200.000 17.016 ;
    END
  END cfg_mgmt_read_data[31]
  PIN cfg_mgmt_read_write_done
    DIRECTION OUTPUT ;
    USE SIGNAL ;
    PORT
      LAYER M4 ;
      RECT 199.928 17.136 200.000 17.160 ;
    END
  END cfg_mgmt_read_write_done
  PIN cfg_msg_received
    DIRECTION OUTPUT ;
    USE SIGNAL ;
    PORT
      LAYER M4 ;
      RECT 199.928 17.280 200.000 17.304 ;
    END
  END cfg_msg_received
  PIN cfg_msg_received_data[0]
    DIRECTION OUTPUT ;
    USE SIGNAL ;
    PORT
      LAYER M4 ;
      RECT 199.928 17.424 200.000 17.448 ;
    END
  END cfg_msg_received_data[0]
  PIN cfg_msg_received_data[1]
    DIRECTION OUTPUT ;
    USE SIGNAL ;
    PORT
      LAYER M4 ;
      RECT 199.928 17.568 200.000 17.592 ;
    END
  END cfg_msg_received_data[1]
  PIN cfg_msg_received_data[2]
    DIRECTION OUTPUT ;
    USE SIGNAL ;
    PORT
      LAYER M4 ;
      RECT 199.928 17.712 200.000 17.736 ;
    END
  END cfg_msg_received_data[2]
  PIN cfg_msg_received_data[3]
    DIRECTION OUTPUT ;
    USE SIGNAL ;
    PORT
      LAYER M4 ;
      RECT 199.928 17.856 200.000 17.880 ;
    END
  END cfg_msg_received_data[3]
  PIN cfg_msg_received_data[4]
    DIRECTION OUTPUT ;
    USE SIGNAL ;
    PORT
      LAYER M4 ;
      RECT 199.928 18.000 200.000 18.024 ;
    END
  END cfg_msg_received_data[4]
  PIN cfg_msg_received_data[5]
    DIRECTION OUTPUT ;
    USE SIGNAL ;
    PORT
      LAYER M4 ;
      RECT 199.928 18.144 200.000 18.168 ;
    END
  END cfg_msg_received_data[5]
  PIN cfg_msg_received_data[6]
    DIRECTION OUTPUT ;
    USE SIGNAL ;
    PORT
      LAYER M4 ;
      RECT 199.928 18.288 200.000 18.312 ;
    END
  END cfg_msg_received_data[6]
  PIN cfg_msg_received_data[7]
    DIRECTION OUTPUT ;
    USE SIGNAL ;
    PORT
      LAYER M4 ;
      RECT 199.928 18.432 200.000 18.456 ;
    END
  END cfg_msg_received_data[7]
  PIN cfg_msg_received_type[0]
    DIRECTION OUTPUT ;
    USE SIGNAL ;
    PORT
      LAYER M4 ;
      RECT 199.928 18.576 200.000 18.600 ;
    END
  END cfg_msg_received_type[0]
  PIN cfg_msg_received_type[1]
    DIRECTION OUTPUT ;
    USE SIGNAL ;
    PORT
      LAYER M4 ;
      RECT 199.928 18.720 200.000 18.744 ;
    END
  END cfg_msg_received_type[1]
  PIN cfg_msg_received_type[2]
    DIRECTION OUTPUT ;
    USE SIGNAL ;
    PORT
      LAYER M4 ;
      RECT 199.928 18.864 200.000 18.888 ;
    END
  END cfg_msg_received_type[2]
  PIN cfg_msg_received_type[3]
    DIRECTION OUTPUT ;
    USE SIGNAL ;
    PORT
      LAYER M4 ;
      RECT 199.928 19.008 200.000 19.032 ;
    END
  END cfg_msg_received_type[3]
  PIN cfg_msg_received_type[4]
    DIRECTION OUTPUT ;
    USE SIGNAL ;
    PORT
      LAYER M4 ;
      RECT 199.928 19.152 200.000 19.176 ;
    END
  END cfg_msg_received_type[4]
  PIN cfg_msg_transmit_done
    DIRECTION OUTPUT ;
    USE SIGNAL ;
    PORT
      LAYER M4 ;
      RECT 199.928 19.296 200.000 19.320 ;
    END
  END cfg_msg_transmit_done
  PIN cfg_negotiated_width[0]
    DIRECTION OUTPUT ;
    USE SIGNAL ;
    PORT
      LAYER M4 ;
      RECT 199.928 19.440 200.000 19.464 ;
    END
  END cfg_negotiated_width[0]
  PIN cfg_negotiated_width[1]
    DIRECTION OUTPUT ;
    USE SIGNAL ;
    PORT
      LAYER M4 ;
      RECT 199.928 19.584 200.000 19.608 ;
    END
  END cfg_negotiated_width[1]
  PIN cfg_negotiated_width[2]
    DIRECTION OUTPUT ;
    USE SIGNAL ;
    PORT
      LAYER M4 ;
      RECT 199.928 19.728 200.000 19.752 ;
    END
  END cfg_negotiated_width[2]
  PIN cfg_negotiated_width[3]
    DIRECTION OUTPUT ;
    USE SIGNAL ;
    PORT
      LAYER M4 ;
      RECT 199.928 19.872 200.000 19.896 ;
    END
  END cfg_negotiated_width[3]
  PIN cfg_obff_enable[0]
    DIRECTION OUTPUT ;
    USE SIGNAL ;
    PORT
      LAYER M4 ;
      RECT 199.928 20.016 200.000 20.040 ;
    END
  END cfg_obff_enable[0]
  PIN cfg_obff_enable[1]
    DIRECTION OUTPUT ;
    USE SIGNAL ;
    PORT
      LAYER M4 ;
      RECT 199.928 20.160 200.000 20.184 ;
    END
  END cfg_obff_enable[1]
  PIN cfg_per_func_status_data[0]
    DIRECTION OUTPUT ;
    USE SIGNAL ;
    PORT
      LAYER M4 ;
      RECT 199.928 20.304 200.000 20.328 ;
    END
  END cfg_per_func_status_data[0]
  PIN cfg_per_func_status_data[1]
    DIRECTION OUTPUT ;
    USE SIGNAL ;
    PORT
      LAYER M4 ;
      RECT 199.928 20.448 200.000 20.472 ;
    END
  END cfg_per_func_status_data[1]
  PIN cfg_per_func_status_data[2]
    DIRECTION OUTPUT ;
    USE SIGNAL ;
    PORT
      LAYER M4 ;
      RECT 199.928 20.592 200.000 20.616 ;
    END
  END cfg_per_func_status_data[2]
  PIN cfg_per_func_status_data[3]
    DIRECTION OUTPUT ;
    USE SIGNAL ;
    PORT
      LAYER M4 ;
      RECT 199.928 20.736 200.000 20.760 ;
    END
  END cfg_per_func_status_data[3]
  PIN cfg_per_func_status_data[4]
    DIRECTION OUTPUT ;
    USE SIGNAL ;
    PORT
      LAYER M4 ;
      RECT 199.928 20.880 200.000 20.904 ;
    END
  END cfg_per_func_status_data[4]
  PIN cfg_per_func_status_data[5]
    DIRECTION OUTPUT ;
    USE SIGNAL ;
    PORT
      LAYER M4 ;
      RECT 199.928 21.024 200.000 21.048 ;
    END
  END cfg_per_func_status_data[5]
  PIN cfg_per_func_status_data[6]
    DIRECTION OUTPUT ;
    USE SIGNAL ;
    PORT
      LAYER M4 ;
      RECT 199.928 21.168 200.000 21.192 ;
    END
  END cfg_per_func_status_data[6]
  PIN cfg_per_func_status_data[7]
    DIRECTION OUTPUT ;
    USE SIGNAL ;
    PORT
      LAYER M4 ;
      RECT 199.928 21.312 200.000 21.336 ;
    END
  END cfg_per_func_status_data[7]
  PIN cfg_per_func_status_data[8]
    DIRECTION OUTPUT ;
    USE SIGNAL ;
    PORT
      LAYER M4 ;
      RECT 199.928 21.456 200.000 21.480 ;
    END
  END cfg_per_func_status_data[8]
  PIN cfg_per_func_status_data[9]
    DIRECTION OUTPUT ;
    USE SIGNAL ;
    PORT
      LAYER M4 ;
      RECT 199.928 21.600 200.000 21.624 ;
    END
  END cfg_per_func_status_data[9]
  PIN cfg_per_func_status_data[10]
    DIRECTION OUTPUT ;
    USE SIGNAL ;
    PORT
      LAYER M4 ;
      RECT 199.928 21.744 200.000 21.768 ;
    END
  END cfg_per_func_status_data[10]
  PIN cfg_per_func_status_data[11]
    DIRECTION OUTPUT ;
    USE SIGNAL ;
    PORT
      LAYER M4 ;
      RECT 199.928 21.888 200.000 21.912 ;
    END
  END cfg_per_func_status_data[11]
  PIN cfg_per_func_status_data[12]
    DIRECTION OUTPUT ;
    USE SIGNAL ;
    PORT
      LAYER M4 ;
      RECT 199.928 22.032 200.000 22.056 ;
    END
  END cfg_per_func_status_data[12]
  PIN cfg_per_func_status_data[13]
    DIRECTION OUTPUT ;
    USE SIGNAL ;
    PORT
      LAYER M4 ;
      RECT 199.928 22.176 200.000 22.200 ;
    END
  END cfg_per_func_status_data[13]
  PIN cfg_per_func_status_data[14]
    DIRECTION OUTPUT ;
    USE SIGNAL ;
    PORT
      LAYER M4 ;
      RECT 199.928 22.320 200.000 22.344 ;
    END
  END cfg_per_func_status_data[14]
  PIN cfg_per_func_status_data[15]
    DIRECTION OUTPUT ;
    USE SIGNAL ;
    PORT
      LAYER M4 ;
      RECT 199.928 22.464 200.000 22.488 ;
    END
  END cfg_per_func_status_data[15]
  PIN cfg_per_function_update_done
    DIRECTION OUTPUT ;
    USE SIGNAL ;
    PORT
      LAYER M4 ;
      RECT 199.928 22.608 200.000 22.632 ;
    END
  END cfg_per_function_update_done
  PIN cfg_phy_link_down
    DIRECTION OUTPUT ;
    USE SIGNAL ;
    PORT
      LAYER M4 ;
      RECT 199.928 22.752 200.000 22.776 ;
    END
  END cfg_phy_link_down
  PIN cfg_phy_link_status[0]
    DIRECTION OUTPUT ;
    USE SIGNAL ;
    PORT
      LAYER M4 ;
      RECT 199.928 22.896 200.000 22.920 ;
    END
  END cfg_phy_link_status[0]
  PIN cfg_phy_link_status[1]
    DIRECTION OUTPUT ;
    USE SIGNAL ;
    PORT
      LAYER M4 ;
      RECT 199.928 23.040 200.000 23.064 ;
    END
  END cfg_phy_link_status[1]
  PIN cfg_pl_status_change
    DIRECTION OUTPUT ;
    USE SIGNAL ;
    PORT
      LAYER M4 ;
      RECT 199.928 23.184 200.000 23.208 ;
    END
  END cfg_pl_status_change
  PIN cfg_power_state_change_interrupt
    DIRECTION OUTPUT ;
    USE SIGNAL ;
    PORT
      LAYER M4 ;
      RECT 199.928 23.328 200.000 23.352 ;
    END
  END cfg_power_state_change_interrupt
  PIN cfg_rcb_status[0]
    DIRECTION OUTPUT ;
    USE SIGNAL ;
    PORT
      LAYER M4 ;
      RECT 199.928 23.472 200.000 23.496 ;
    END
  END cfg_rcb_status[0]
  PIN cfg_rcb_status[1]
    DIRECTION OUTPUT ;
    USE SIGNAL ;
    PORT
      LAYER M4 ;
      RECT 199.928 23.616 200.000 23.640 ;
    END
  END cfg_rcb_status[1]
  PIN cfg_rcb_status[2]
    DIRECTION OUTPUT ;
    USE SIGNAL ;
    PORT
      LAYER M4 ;
      RECT 199.928 23.760 200.000 23.784 ;
    END
  END cfg_rcb_status[2]
  PIN cfg_rcb_status[3]
    DIRECTION OUTPUT ;
    USE SIGNAL ;
    PORT
      LAYER M4 ;
      RECT 199.928 23.904 200.000 23.928 ;
    END
  END cfg_rcb_status[3]
  PIN cfg_tph_requester_enable[0]
    DIRECTION OUTPUT ;
    USE SIGNAL ;
    PORT
      LAYER M4 ;
      RECT 199.928 24.048 200.000 24.072 ;
    END
  END cfg_tph_requester_enable[0]
  PIN cfg_tph_requester_enable[1]
    DIRECTION OUTPUT ;
    USE SIGNAL ;
    PORT
      LAYER M4 ;
      RECT 199.928 24.192 200.000 24.216 ;
    END
  END cfg_tph_requester_enable[1]
  PIN cfg_tph_requester_enable[2]
    DIRECTION OUTPUT ;
    USE SIGNAL ;
    PORT
      LAYER M4 ;
      RECT 199.928 24.336 200.000 24.360 ;
    END
  END cfg_tph_requester_enable[2]
  PIN cfg_tph_requester_enable[3]
    DIRECTION OUTPUT ;
    USE SIGNAL ;
    PORT
      LAYER M4 ;
      RECT 199.928 24.480 200.000 24.504 ;
    END
  END cfg_tph_requester_enable[3]
  PIN cfg_tph_st_mode[0]
    DIRECTION OUTPUT ;
    USE SIGNAL ;
    PORT
      LAYER M4 ;
      RECT 199.928 24.624 200.000 24.648 ;
    END
  END cfg_tph_st_mode[0]
  PIN cfg_tph_st_mode[1]
    DIRECTION OUTPUT ;
    USE SIGNAL ;
    PORT
      LAYER M4 ;
      RECT 199.928 24.768 200.000 24.792 ;
    END
  END cfg_tph_st_mode[1]
  PIN cfg_tph_st_mode[2]
    DIRECTION OUTPUT ;
    USE SIGNAL ;
    PORT
      LAYER M4 ;
      RECT 199.928 24.912 200.000 24.936 ;
    END
  END cfg_tph_st_mode[2]
  PIN cfg_tph_st_mode[3]
    DIRECTION OUTPUT ;
    USE SIGNAL ;
    PORT
      LAYER M4 ;
      RECT 199.928 25.056 200.000 25.080 ;
    END
  END cfg_tph_st_mode[3]
  PIN cfg_tph_st_mode[4]
    DIRECTION OUTPUT ;
    USE SIGNAL ;
    PORT
      LAYER M4 ;
      RECT 199.928 25.200 200.000 25.224 ;
    END
  END cfg_tph_st_mode[4]
  PIN cfg_tph_st_mode[5]
    DIRECTION OUTPUT ;
    USE SIGNAL ;
    PORT
      LAYER M4 ;
      RECT 199.928 25.344 200.000 25.368 ;
    END
  END cfg_tph_st_mode[5]
  PIN cfg_tph_st_mode[6]
    DIRECTION OUTPUT ;
    USE SIGNAL ;
    PORT
      LAYER M4 ;
      RECT 199.928 25.488 200.000 25.512 ;
    END
  END cfg_tph_st_mode[6]
  PIN cfg_tph_st_mode[7]
    DIRECTION OUTPUT ;
    USE SIGNAL ;
    PORT
      LAYER M4 ;
      RECT 199.928 25.632 200.000 25.656 ;
    END
  END cfg_tph_st_mode[7]
  PIN cfg_tph_st_mode[8]
    DIRECTION OUTPUT ;
    USE SIGNAL ;
    PORT
      LAYER M4 ;
      RECT 199.928 25.776 200.000 25.800 ;
    END
  END cfg_tph_st_mode[8]
  PIN cfg_tph_st_mode[9]
    DIRECTION OUTPUT ;
    USE SIGNAL ;
    PORT
      LAYER M4 ;
      RECT 199.928 25.920 200.000 25.944 ;
    END
  END cfg_tph_st_mode[9]
  PIN cfg_tph_st_mode[10]
    DIRECTION OUTPUT ;
    USE SIGNAL ;
    PORT
      LAYER M4 ;
      RECT 199.928 26.064 200.000 26.088 ;
    END
  END cfg_tph_st_mode[10]
  PIN cfg_tph_st_mode[11]
    DIRECTION OUTPUT ;
    USE SIGNAL ;
    PORT
      LAYER M4 ;
      RECT 199.928 26.208 200.000 26.232 ;
    END
  END cfg_tph_st_mode[11]
  PIN cfg_vf_flr_in_process[0]
    DIRECTION OUTPUT ;
    USE SIGNAL ;
    PORT
      LAYER M4 ;
      RECT 199.928 26.352 200.000 26.376 ;
    END
  END cfg_vf_flr_in_process[0]
  PIN cfg_vf_flr_in_process[1]
    DIRECTION OUTPUT ;
    USE SIGNAL ;
    PORT
      LAYER M4 ;
      RECT 199.928 26.496 200.000 26.520 ;
    END
  END cfg_vf_flr_in_process[1]
  PIN cfg_vf_flr_in_process[2]
    DIRECTION OUTPUT ;
    USE SIGNAL ;
    PORT
      LAYER M4 ;
      RECT 199.928 26.640 200.000 26.664 ;
    END
  END cfg_vf_flr_in_process[2]
  PIN cfg_vf_flr_in_process[3]
    DIRECTION OUTPUT ;
    USE SIGNAL ;
    PORT
      LAYER M4 ;
      RECT 199.928 26.784 200.000 26.808 ;
    END
  END cfg_vf_flr_in_process[3]
  PIN cfg_vf_flr_in_process[4]
    DIRECTION OUTPUT ;
    USE SIGNAL ;
    PORT
      LAYER M4 ;
      RECT 199.928 26.928 200.000 26.952 ;
    END
  END cfg_vf_flr_in_process[4]
  PIN cfg_vf_flr_in_process[5]
    DIRECTION OUTPUT ;
    USE SIGNAL ;
    PORT
      LAYER M4 ;
      RECT 199.928 27.072 200.000 27.096 ;
    END
  END cfg_vf_flr_in_process[5]
  PIN cfg_vf_flr_in_process[6]
    DIRECTION OUTPUT ;
    USE SIGNAL ;
    PORT
      LAYER M4 ;
      RECT 199.928 27.216 200.000 27.240 ;
    END
  END cfg_vf_flr_in_process[6]
  PIN cfg_vf_flr_in_process[7]
    DIRECTION OUTPUT ;
    USE SIGNAL ;
    PORT
      LAYER M4 ;
      RECT 199.928 27.360 200.000 27.384 ;
    END
  END cfg_vf_flr_in_process[7]
  PIN int_qpll1lock_out
    DIRECTION OUTPUT ;
    USE SIGNAL ;
    PORT
      LAYER M4 ;
      RECT 199.928 27.504 200.000 27.528 ;
    END
  END int_qpll1lock_out
  PIN int_qpll1outclk_out
    DIRECTION OUTPUT ;
    USE SIGNAL ;
    PORT
      LAYER M4 ;
      RECT 199.928 27.648 200.000 27.672 ;
    END
  END int_qpll1outclk_out
  PIN int_qpll1outrefclk_out
    DIRECTION OUTPUT ;
    USE SIGNAL ;
    PORT
      LAYER M4 ;
      RECT 199.928 27.792 200.000 27.816 ;
    END
  END int_qpll1outrefclk_out
  PIN m_axis_cq_tdata[0]
    DIRECTION OUTPUT ;
    USE SIGNAL ;
    PORT
      LAYER M4 ;
      RECT 199.928 27.936 200.000 27.960 ;
    END
  END m_axis_cq_tdata[0]
  PIN m_axis_cq_tdata[1]
    DIRECTION OUTPUT ;
    USE SIGNAL ;
    PORT
      LAYER M4 ;
      RECT 199.928 28.080 200.000 28.104 ;
    END
  END m_axis_cq_tdata[1]
  PIN m_axis_cq_tdata[2]
    DIRECTION OUTPUT ;
    USE SIGNAL ;
    PORT
      LAYER M4 ;
      RECT 199.928 28.224 200.000 28.248 ;
    END
  END m_axis_cq_tdata[2]
  PIN m_axis_cq_tdata[3]
    DIRECTION OUTPUT ;
    USE SIGNAL ;
    PORT
      LAYER M4 ;
      RECT 199.928 28.368 200.000 28.392 ;
    END
  END m_axis_cq_tdata[3]
  PIN m_axis_cq_tdata[4]
    DIRECTION OUTPUT ;
    USE SIGNAL ;
    PORT
      LAYER M4 ;
      RECT 199.928 28.512 200.000 28.536 ;
    END
  END m_axis_cq_tdata[4]
  PIN m_axis_cq_tdata[5]
    DIRECTION OUTPUT ;
    USE SIGNAL ;
    PORT
      LAYER M4 ;
      RECT 199.928 28.656 200.000 28.680 ;
    END
  END m_axis_cq_tdata[5]
  PIN m_axis_cq_tdata[6]
    DIRECTION OUTPUT ;
    USE SIGNAL ;
    PORT
      LAYER M4 ;
      RECT 199.928 28.800 200.000 28.824 ;
    END
  END m_axis_cq_tdata[6]
  PIN m_axis_cq_tdata[7]
    DIRECTION OUTPUT ;
    USE SIGNAL ;
    PORT
      LAYER M4 ;
      RECT 199.928 28.944 200.000 28.968 ;
    END
  END m_axis_cq_tdata[7]
  PIN m_axis_cq_tdata[8]
    DIRECTION OUTPUT ;
    USE SIGNAL ;
    PORT
      LAYER M4 ;
      RECT 199.928 29.088 200.000 29.112 ;
    END
  END m_axis_cq_tdata[8]
  PIN m_axis_cq_tdata[9]
    DIRECTION OUTPUT ;
    USE SIGNAL ;
    PORT
      LAYER M4 ;
      RECT 199.928 29.232 200.000 29.256 ;
    END
  END m_axis_cq_tdata[9]
  PIN m_axis_cq_tdata[10]
    DIRECTION OUTPUT ;
    USE SIGNAL ;
    PORT
      LAYER M4 ;
      RECT 199.928 29.376 200.000 29.400 ;
    END
  END m_axis_cq_tdata[10]
  PIN m_axis_cq_tdata[11]
    DIRECTION OUTPUT ;
    USE SIGNAL ;
    PORT
      LAYER M4 ;
      RECT 199.928 29.520 200.000 29.544 ;
    END
  END m_axis_cq_tdata[11]
  PIN m_axis_cq_tdata[12]
    DIRECTION OUTPUT ;
    USE SIGNAL ;
    PORT
      LAYER M4 ;
      RECT 199.928 29.664 200.000 29.688 ;
    END
  END m_axis_cq_tdata[12]
  PIN m_axis_cq_tdata[13]
    DIRECTION OUTPUT ;
    USE SIGNAL ;
    PORT
      LAYER M4 ;
      RECT 199.928 29.808 200.000 29.832 ;
    END
  END m_axis_cq_tdata[13]
  PIN m_axis_cq_tdata[14]
    DIRECTION OUTPUT ;
    USE SIGNAL ;
    PORT
      LAYER M4 ;
      RECT 199.928 29.952 200.000 29.976 ;
    END
  END m_axis_cq_tdata[14]
  PIN m_axis_cq_tdata[15]
    DIRECTION OUTPUT ;
    USE SIGNAL ;
    PORT
      LAYER M4 ;
      RECT 199.928 30.096 200.000 30.120 ;
    END
  END m_axis_cq_tdata[15]
  PIN m_axis_cq_tdata[16]
    DIRECTION OUTPUT ;
    USE SIGNAL ;
    PORT
      LAYER M4 ;
      RECT 199.928 30.240 200.000 30.264 ;
    END
  END m_axis_cq_tdata[16]
  PIN m_axis_cq_tdata[17]
    DIRECTION OUTPUT ;
    USE SIGNAL ;
    PORT
      LAYER M4 ;
      RECT 199.928 30.384 200.000 30.408 ;
    END
  END m_axis_cq_tdata[17]
  PIN m_axis_cq_tdata[18]
    DIRECTION OUTPUT ;
    USE SIGNAL ;
    PORT
      LAYER M4 ;
      RECT 199.928 30.528 200.000 30.552 ;
    END
  END m_axis_cq_tdata[18]
  PIN m_axis_cq_tdata[19]
    DIRECTION OUTPUT ;
    USE SIGNAL ;
    PORT
      LAYER M4 ;
      RECT 199.928 30.672 200.000 30.696 ;
    END
  END m_axis_cq_tdata[19]
  PIN m_axis_cq_tdata[20]
    DIRECTION OUTPUT ;
    USE SIGNAL ;
    PORT
      LAYER M4 ;
      RECT 199.928 30.816 200.000 30.840 ;
    END
  END m_axis_cq_tdata[20]
  PIN m_axis_cq_tdata[21]
    DIRECTION OUTPUT ;
    USE SIGNAL ;
    PORT
      LAYER M4 ;
      RECT 199.928 30.960 200.000 30.984 ;
    END
  END m_axis_cq_tdata[21]
  PIN m_axis_cq_tdata[22]
    DIRECTION OUTPUT ;
    USE SIGNAL ;
    PORT
      LAYER M4 ;
      RECT 199.928 31.104 200.000 31.128 ;
    END
  END m_axis_cq_tdata[22]
  PIN m_axis_cq_tdata[23]
    DIRECTION OUTPUT ;
    USE SIGNAL ;
    PORT
      LAYER M4 ;
      RECT 199.928 31.248 200.000 31.272 ;
    END
  END m_axis_cq_tdata[23]
  PIN m_axis_cq_tdata[24]
    DIRECTION OUTPUT ;
    USE SIGNAL ;
    PORT
      LAYER M4 ;
      RECT 199.928 31.392 200.000 31.416 ;
    END
  END m_axis_cq_tdata[24]
  PIN m_axis_cq_tdata[25]
    DIRECTION OUTPUT ;
    USE SIGNAL ;
    PORT
      LAYER M4 ;
      RECT 199.928 31.536 200.000 31.560 ;
    END
  END m_axis_cq_tdata[25]
  PIN m_axis_cq_tdata[26]
    DIRECTION OUTPUT ;
    USE SIGNAL ;
    PORT
      LAYER M4 ;
      RECT 199.928 31.680 200.000 31.704 ;
    END
  END m_axis_cq_tdata[26]
  PIN m_axis_cq_tdata[27]
    DIRECTION OUTPUT ;
    USE SIGNAL ;
    PORT
      LAYER M4 ;
      RECT 199.928 31.824 200.000 31.848 ;
    END
  END m_axis_cq_tdata[27]
  PIN m_axis_cq_tdata[28]
    DIRECTION OUTPUT ;
    USE SIGNAL ;
    PORT
      LAYER M4 ;
      RECT 199.928 31.968 200.000 31.992 ;
    END
  END m_axis_cq_tdata[28]
  PIN m_axis_cq_tdata[29]
    DIRECTION OUTPUT ;
    USE SIGNAL ;
    PORT
      LAYER M4 ;
      RECT 199.928 32.112 200.000 32.136 ;
    END
  END m_axis_cq_tdata[29]
  PIN m_axis_cq_tdata[30]
    DIRECTION OUTPUT ;
    USE SIGNAL ;
    PORT
      LAYER M4 ;
      RECT 199.928 32.256 200.000 32.280 ;
    END
  END m_axis_cq_tdata[30]
  PIN m_axis_cq_tdata[31]
    DIRECTION OUTPUT ;
    USE SIGNAL ;
    PORT
      LAYER M4 ;
      RECT 199.928 32.400 200.000 32.424 ;
    END
  END m_axis_cq_tdata[31]
  PIN m_axis_cq_tdata[32]
    DIRECTION OUTPUT ;
    USE SIGNAL ;
    PORT
      LAYER M4 ;
      RECT 199.928 32.544 200.000 32.568 ;
    END
  END m_axis_cq_tdata[32]
  PIN m_axis_cq_tdata[33]
    DIRECTION OUTPUT ;
    USE SIGNAL ;
    PORT
      LAYER M4 ;
      RECT 199.928 32.688 200.000 32.712 ;
    END
  END m_axis_cq_tdata[33]
  PIN m_axis_cq_tdata[34]
    DIRECTION OUTPUT ;
    USE SIGNAL ;
    PORT
      LAYER M4 ;
      RECT 199.928 32.832 200.000 32.856 ;
    END
  END m_axis_cq_tdata[34]
  PIN m_axis_cq_tdata[35]
    DIRECTION OUTPUT ;
    USE SIGNAL ;
    PORT
      LAYER M4 ;
      RECT 199.928 32.976 200.000 33.000 ;
    END
  END m_axis_cq_tdata[35]
  PIN m_axis_cq_tdata[36]
    DIRECTION OUTPUT ;
    USE SIGNAL ;
    PORT
      LAYER M4 ;
      RECT 199.928 33.120 200.000 33.144 ;
    END
  END m_axis_cq_tdata[36]
  PIN m_axis_cq_tdata[37]
    DIRECTION OUTPUT ;
    USE SIGNAL ;
    PORT
      LAYER M4 ;
      RECT 199.928 33.264 200.000 33.288 ;
    END
  END m_axis_cq_tdata[37]
  PIN m_axis_cq_tdata[38]
    DIRECTION OUTPUT ;
    USE SIGNAL ;
    PORT
      LAYER M4 ;
      RECT 199.928 33.408 200.000 33.432 ;
    END
  END m_axis_cq_tdata[38]
  PIN m_axis_cq_tdata[39]
    DIRECTION OUTPUT ;
    USE SIGNAL ;
    PORT
      LAYER M4 ;
      RECT 199.928 33.552 200.000 33.576 ;
    END
  END m_axis_cq_tdata[39]
  PIN m_axis_cq_tdata[40]
    DIRECTION OUTPUT ;
    USE SIGNAL ;
    PORT
      LAYER M4 ;
      RECT 199.928 33.696 200.000 33.720 ;
    END
  END m_axis_cq_tdata[40]
  PIN m_axis_cq_tdata[41]
    DIRECTION OUTPUT ;
    USE SIGNAL ;
    PORT
      LAYER M4 ;
      RECT 199.928 33.840 200.000 33.864 ;
    END
  END m_axis_cq_tdata[41]
  PIN m_axis_cq_tdata[42]
    DIRECTION OUTPUT ;
    USE SIGNAL ;
    PORT
      LAYER M4 ;
      RECT 199.928 33.984 200.000 34.008 ;
    END
  END m_axis_cq_tdata[42]
  PIN m_axis_cq_tdata[43]
    DIRECTION OUTPUT ;
    USE SIGNAL ;
    PORT
      LAYER M4 ;
      RECT 199.928 34.128 200.000 34.152 ;
    END
  END m_axis_cq_tdata[43]
  PIN m_axis_cq_tdata[44]
    DIRECTION OUTPUT ;
    USE SIGNAL ;
    PORT
      LAYER M4 ;
      RECT 199.928 34.272 200.000 34.296 ;
    END
  END m_axis_cq_tdata[44]
  PIN m_axis_cq_tdata[45]
    DIRECTION OUTPUT ;
    USE SIGNAL ;
    PORT
      LAYER M4 ;
      RECT 199.928 34.416 200.000 34.440 ;
    END
  END m_axis_cq_tdata[45]
  PIN m_axis_cq_tdata[46]
    DIRECTION OUTPUT ;
    USE SIGNAL ;
    PORT
      LAYER M4 ;
      RECT 199.928 34.560 200.000 34.584 ;
    END
  END m_axis_cq_tdata[46]
  PIN m_axis_cq_tdata[47]
    DIRECTION OUTPUT ;
    USE SIGNAL ;
    PORT
      LAYER M4 ;
      RECT 199.928 34.704 200.000 34.728 ;
    END
  END m_axis_cq_tdata[47]
  PIN m_axis_cq_tdata[48]
    DIRECTION OUTPUT ;
    USE SIGNAL ;
    PORT
      LAYER M4 ;
      RECT 199.928 34.848 200.000 34.872 ;
    END
  END m_axis_cq_tdata[48]
  PIN m_axis_cq_tdata[49]
    DIRECTION OUTPUT ;
    USE SIGNAL ;
    PORT
      LAYER M4 ;
      RECT 199.928 34.992 200.000 35.016 ;
    END
  END m_axis_cq_tdata[49]
  PIN m_axis_cq_tdata[50]
    DIRECTION OUTPUT ;
    USE SIGNAL ;
    PORT
      LAYER M4 ;
      RECT 199.928 35.136 200.000 35.160 ;
    END
  END m_axis_cq_tdata[50]
  PIN m_axis_cq_tdata[51]
    DIRECTION OUTPUT ;
    USE SIGNAL ;
    PORT
      LAYER M4 ;
      RECT 199.928 35.280 200.000 35.304 ;
    END
  END m_axis_cq_tdata[51]
  PIN m_axis_cq_tdata[52]
    DIRECTION OUTPUT ;
    USE SIGNAL ;
    PORT
      LAYER M4 ;
      RECT 199.928 35.424 200.000 35.448 ;
    END
  END m_axis_cq_tdata[52]
  PIN m_axis_cq_tdata[53]
    DIRECTION OUTPUT ;
    USE SIGNAL ;
    PORT
      LAYER M4 ;
      RECT 199.928 35.568 200.000 35.592 ;
    END
  END m_axis_cq_tdata[53]
  PIN m_axis_cq_tdata[54]
    DIRECTION OUTPUT ;
    USE SIGNAL ;
    PORT
      LAYER M4 ;
      RECT 199.928 35.712 200.000 35.736 ;
    END
  END m_axis_cq_tdata[54]
  PIN m_axis_cq_tdata[55]
    DIRECTION OUTPUT ;
    USE SIGNAL ;
    PORT
      LAYER M4 ;
      RECT 199.928 35.856 200.000 35.880 ;
    END
  END m_axis_cq_tdata[55]
  PIN m_axis_cq_tdata[56]
    DIRECTION OUTPUT ;
    USE SIGNAL ;
    PORT
      LAYER M4 ;
      RECT 199.928 36.000 200.000 36.024 ;
    END
  END m_axis_cq_tdata[56]
  PIN m_axis_cq_tdata[57]
    DIRECTION OUTPUT ;
    USE SIGNAL ;
    PORT
      LAYER M4 ;
      RECT 199.928 36.144 200.000 36.168 ;
    END
  END m_axis_cq_tdata[57]
  PIN m_axis_cq_tdata[58]
    DIRECTION OUTPUT ;
    USE SIGNAL ;
    PORT
      LAYER M4 ;
      RECT 199.928 36.288 200.000 36.312 ;
    END
  END m_axis_cq_tdata[58]
  PIN m_axis_cq_tdata[59]
    DIRECTION OUTPUT ;
    USE SIGNAL ;
    PORT
      LAYER M4 ;
      RECT 199.928 36.432 200.000 36.456 ;
    END
  END m_axis_cq_tdata[59]
  PIN m_axis_cq_tdata[60]
    DIRECTION OUTPUT ;
    USE SIGNAL ;
    PORT
      LAYER M4 ;
      RECT 199.928 36.576 200.000 36.600 ;
    END
  END m_axis_cq_tdata[60]
  PIN m_axis_cq_tdata[61]
    DIRECTION OUTPUT ;
    USE SIGNAL ;
    PORT
      LAYER M4 ;
      RECT 199.928 36.720 200.000 36.744 ;
    END
  END m_axis_cq_tdata[61]
  PIN m_axis_cq_tdata[62]
    DIRECTION OUTPUT ;
    USE SIGNAL ;
    PORT
      LAYER M4 ;
      RECT 199.928 36.864 200.000 36.888 ;
    END
  END m_axis_cq_tdata[62]
  PIN m_axis_cq_tdata[63]
    DIRECTION OUTPUT ;
    USE SIGNAL ;
    PORT
      LAYER M4 ;
      RECT 199.928 37.008 200.000 37.032 ;
    END
  END m_axis_cq_tdata[63]
  PIN m_axis_cq_tdata[64]
    DIRECTION OUTPUT ;
    USE SIGNAL ;
    PORT
      LAYER M4 ;
      RECT 199.928 37.152 200.000 37.176 ;
    END
  END m_axis_cq_tdata[64]
  PIN m_axis_cq_tdata[65]
    DIRECTION OUTPUT ;
    USE SIGNAL ;
    PORT
      LAYER M4 ;
      RECT 199.928 37.296 200.000 37.320 ;
    END
  END m_axis_cq_tdata[65]
  PIN m_axis_cq_tdata[66]
    DIRECTION OUTPUT ;
    USE SIGNAL ;
    PORT
      LAYER M4 ;
      RECT 199.928 37.440 200.000 37.464 ;
    END
  END m_axis_cq_tdata[66]
  PIN m_axis_cq_tdata[67]
    DIRECTION OUTPUT ;
    USE SIGNAL ;
    PORT
      LAYER M4 ;
      RECT 199.928 37.584 200.000 37.608 ;
    END
  END m_axis_cq_tdata[67]
  PIN m_axis_cq_tdata[68]
    DIRECTION OUTPUT ;
    USE SIGNAL ;
    PORT
      LAYER M4 ;
      RECT 199.928 37.728 200.000 37.752 ;
    END
  END m_axis_cq_tdata[68]
  PIN m_axis_cq_tdata[69]
    DIRECTION OUTPUT ;
    USE SIGNAL ;
    PORT
      LAYER M4 ;
      RECT 199.928 37.872 200.000 37.896 ;
    END
  END m_axis_cq_tdata[69]
  PIN m_axis_cq_tdata[70]
    DIRECTION OUTPUT ;
    USE SIGNAL ;
    PORT
      LAYER M4 ;
      RECT 199.928 38.016 200.000 38.040 ;
    END
  END m_axis_cq_tdata[70]
  PIN m_axis_cq_tdata[71]
    DIRECTION OUTPUT ;
    USE SIGNAL ;
    PORT
      LAYER M4 ;
      RECT 199.928 38.160 200.000 38.184 ;
    END
  END m_axis_cq_tdata[71]
  PIN m_axis_cq_tdata[72]
    DIRECTION OUTPUT ;
    USE SIGNAL ;
    PORT
      LAYER M4 ;
      RECT 199.928 38.304 200.000 38.328 ;
    END
  END m_axis_cq_tdata[72]
  PIN m_axis_cq_tdata[73]
    DIRECTION OUTPUT ;
    USE SIGNAL ;
    PORT
      LAYER M4 ;
      RECT 199.928 38.448 200.000 38.472 ;
    END
  END m_axis_cq_tdata[73]
  PIN m_axis_cq_tdata[74]
    DIRECTION OUTPUT ;
    USE SIGNAL ;
    PORT
      LAYER M4 ;
      RECT 199.928 38.592 200.000 38.616 ;
    END
  END m_axis_cq_tdata[74]
  PIN m_axis_cq_tdata[75]
    DIRECTION OUTPUT ;
    USE SIGNAL ;
    PORT
      LAYER M4 ;
      RECT 199.928 38.736 200.000 38.760 ;
    END
  END m_axis_cq_tdata[75]
  PIN m_axis_cq_tdata[76]
    DIRECTION OUTPUT ;
    USE SIGNAL ;
    PORT
      LAYER M4 ;
      RECT 199.928 38.880 200.000 38.904 ;
    END
  END m_axis_cq_tdata[76]
  PIN m_axis_cq_tdata[77]
    DIRECTION OUTPUT ;
    USE SIGNAL ;
    PORT
      LAYER M4 ;
      RECT 199.928 39.024 200.000 39.048 ;
    END
  END m_axis_cq_tdata[77]
  PIN m_axis_cq_tdata[78]
    DIRECTION OUTPUT ;
    USE SIGNAL ;
    PORT
      LAYER M4 ;
      RECT 199.928 39.168 200.000 39.192 ;
    END
  END m_axis_cq_tdata[78]
  PIN m_axis_cq_tdata[79]
    DIRECTION OUTPUT ;
    USE SIGNAL ;
    PORT
      LAYER M4 ;
      RECT 199.928 39.312 200.000 39.336 ;
    END
  END m_axis_cq_tdata[79]
  PIN m_axis_cq_tdata[80]
    DIRECTION OUTPUT ;
    USE SIGNAL ;
    PORT
      LAYER M4 ;
      RECT 199.928 39.456 200.000 39.480 ;
    END
  END m_axis_cq_tdata[80]
  PIN m_axis_cq_tdata[81]
    DIRECTION OUTPUT ;
    USE SIGNAL ;
    PORT
      LAYER M4 ;
      RECT 199.928 39.600 200.000 39.624 ;
    END
  END m_axis_cq_tdata[81]
  PIN m_axis_cq_tdata[82]
    DIRECTION OUTPUT ;
    USE SIGNAL ;
    PORT
      LAYER M4 ;
      RECT 199.928 39.744 200.000 39.768 ;
    END
  END m_axis_cq_tdata[82]
  PIN m_axis_cq_tdata[83]
    DIRECTION OUTPUT ;
    USE SIGNAL ;
    PORT
      LAYER M4 ;
      RECT 199.928 39.888 200.000 39.912 ;
    END
  END m_axis_cq_tdata[83]
  PIN m_axis_cq_tdata[84]
    DIRECTION OUTPUT ;
    USE SIGNAL ;
    PORT
      LAYER M4 ;
      RECT 199.928 40.032 200.000 40.056 ;
    END
  END m_axis_cq_tdata[84]
  PIN m_axis_cq_tdata[85]
    DIRECTION OUTPUT ;
    USE SIGNAL ;
    PORT
      LAYER M4 ;
      RECT 199.928 40.176 200.000 40.200 ;
    END
  END m_axis_cq_tdata[85]
  PIN m_axis_cq_tdata[86]
    DIRECTION OUTPUT ;
    USE SIGNAL ;
    PORT
      LAYER M4 ;
      RECT 199.928 40.320 200.000 40.344 ;
    END
  END m_axis_cq_tdata[86]
  PIN m_axis_cq_tdata[87]
    DIRECTION OUTPUT ;
    USE SIGNAL ;
    PORT
      LAYER M4 ;
      RECT 199.928 40.464 200.000 40.488 ;
    END
  END m_axis_cq_tdata[87]
  PIN m_axis_cq_tdata[88]
    DIRECTION OUTPUT ;
    USE SIGNAL ;
    PORT
      LAYER M4 ;
      RECT 199.928 40.608 200.000 40.632 ;
    END
  END m_axis_cq_tdata[88]
  PIN m_axis_cq_tdata[89]
    DIRECTION OUTPUT ;
    USE SIGNAL ;
    PORT
      LAYER M4 ;
      RECT 199.928 40.752 200.000 40.776 ;
    END
  END m_axis_cq_tdata[89]
  PIN m_axis_cq_tdata[90]
    DIRECTION OUTPUT ;
    USE SIGNAL ;
    PORT
      LAYER M4 ;
      RECT 199.928 40.896 200.000 40.920 ;
    END
  END m_axis_cq_tdata[90]
  PIN m_axis_cq_tdata[91]
    DIRECTION OUTPUT ;
    USE SIGNAL ;
    PORT
      LAYER M4 ;
      RECT 199.928 41.040 200.000 41.064 ;
    END
  END m_axis_cq_tdata[91]
  PIN m_axis_cq_tdata[92]
    DIRECTION OUTPUT ;
    USE SIGNAL ;
    PORT
      LAYER M4 ;
      RECT 199.928 41.184 200.000 41.208 ;
    END
  END m_axis_cq_tdata[92]
  PIN m_axis_cq_tdata[93]
    DIRECTION OUTPUT ;
    USE SIGNAL ;
    PORT
      LAYER M4 ;
      RECT 199.928 41.328 200.000 41.352 ;
    END
  END m_axis_cq_tdata[93]
  PIN m_axis_cq_tdata[94]
    DIRECTION OUTPUT ;
    USE SIGNAL ;
    PORT
      LAYER M4 ;
      RECT 199.928 41.472 200.000 41.496 ;
    END
  END m_axis_cq_tdata[94]
  PIN m_axis_cq_tdata[95]
    DIRECTION OUTPUT ;
    USE SIGNAL ;
    PORT
      LAYER M4 ;
      RECT 199.928 41.616 200.000 41.640 ;
    END
  END m_axis_cq_tdata[95]
  PIN m_axis_cq_tdata[96]
    DIRECTION OUTPUT ;
    USE SIGNAL ;
    PORT
      LAYER M4 ;
      RECT 199.928 41.760 200.000 41.784 ;
    END
  END m_axis_cq_tdata[96]
  PIN m_axis_cq_tdata[97]
    DIRECTION OUTPUT ;
    USE SIGNAL ;
    PORT
      LAYER M4 ;
      RECT 199.928 41.904 200.000 41.928 ;
    END
  END m_axis_cq_tdata[97]
  PIN m_axis_cq_tdata[98]
    DIRECTION OUTPUT ;
    USE SIGNAL ;
    PORT
      LAYER M4 ;
      RECT 199.928 42.048 200.000 42.072 ;
    END
  END m_axis_cq_tdata[98]
  PIN m_axis_cq_tdata[99]
    DIRECTION OUTPUT ;
    USE SIGNAL ;
    PORT
      LAYER M4 ;
      RECT 199.928 42.192 200.000 42.216 ;
    END
  END m_axis_cq_tdata[99]
  PIN m_axis_cq_tdata[100]
    DIRECTION OUTPUT ;
    USE SIGNAL ;
    PORT
      LAYER M4 ;
      RECT 199.928 42.336 200.000 42.360 ;
    END
  END m_axis_cq_tdata[100]
  PIN m_axis_cq_tdata[101]
    DIRECTION OUTPUT ;
    USE SIGNAL ;
    PORT
      LAYER M4 ;
      RECT 199.928 42.480 200.000 42.504 ;
    END
  END m_axis_cq_tdata[101]
  PIN m_axis_cq_tdata[102]
    DIRECTION OUTPUT ;
    USE SIGNAL ;
    PORT
      LAYER M4 ;
      RECT 199.928 42.624 200.000 42.648 ;
    END
  END m_axis_cq_tdata[102]
  PIN m_axis_cq_tdata[103]
    DIRECTION OUTPUT ;
    USE SIGNAL ;
    PORT
      LAYER M4 ;
      RECT 199.928 42.768 200.000 42.792 ;
    END
  END m_axis_cq_tdata[103]
  PIN m_axis_cq_tdata[104]
    DIRECTION OUTPUT ;
    USE SIGNAL ;
    PORT
      LAYER M4 ;
      RECT 199.928 42.912 200.000 42.936 ;
    END
  END m_axis_cq_tdata[104]
  PIN m_axis_cq_tdata[105]
    DIRECTION OUTPUT ;
    USE SIGNAL ;
    PORT
      LAYER M4 ;
      RECT 199.928 43.056 200.000 43.080 ;
    END
  END m_axis_cq_tdata[105]
  PIN m_axis_cq_tdata[106]
    DIRECTION OUTPUT ;
    USE SIGNAL ;
    PORT
      LAYER M4 ;
      RECT 199.928 43.200 200.000 43.224 ;
    END
  END m_axis_cq_tdata[106]
  PIN m_axis_cq_tdata[107]
    DIRECTION OUTPUT ;
    USE SIGNAL ;
    PORT
      LAYER M4 ;
      RECT 199.928 43.344 200.000 43.368 ;
    END
  END m_axis_cq_tdata[107]
  PIN m_axis_cq_tdata[108]
    DIRECTION OUTPUT ;
    USE SIGNAL ;
    PORT
      LAYER M4 ;
      RECT 199.928 43.488 200.000 43.512 ;
    END
  END m_axis_cq_tdata[108]
  PIN m_axis_cq_tdata[109]
    DIRECTION OUTPUT ;
    USE SIGNAL ;
    PORT
      LAYER M4 ;
      RECT 199.928 43.632 200.000 43.656 ;
    END
  END m_axis_cq_tdata[109]
  PIN m_axis_cq_tdata[110]
    DIRECTION OUTPUT ;
    USE SIGNAL ;
    PORT
      LAYER M4 ;
      RECT 199.928 43.776 200.000 43.800 ;
    END
  END m_axis_cq_tdata[110]
  PIN m_axis_cq_tdata[111]
    DIRECTION OUTPUT ;
    USE SIGNAL ;
    PORT
      LAYER M4 ;
      RECT 199.928 43.920 200.000 43.944 ;
    END
  END m_axis_cq_tdata[111]
  PIN m_axis_cq_tdata[112]
    DIRECTION OUTPUT ;
    USE SIGNAL ;
    PORT
      LAYER M4 ;
      RECT 199.928 44.064 200.000 44.088 ;
    END
  END m_axis_cq_tdata[112]
  PIN m_axis_cq_tdata[113]
    DIRECTION OUTPUT ;
    USE SIGNAL ;
    PORT
      LAYER M4 ;
      RECT 199.928 44.208 200.000 44.232 ;
    END
  END m_axis_cq_tdata[113]
  PIN m_axis_cq_tdata[114]
    DIRECTION OUTPUT ;
    USE SIGNAL ;
    PORT
      LAYER M4 ;
      RECT 199.928 44.352 200.000 44.376 ;
    END
  END m_axis_cq_tdata[114]
  PIN m_axis_cq_tdata[115]
    DIRECTION OUTPUT ;
    USE SIGNAL ;
    PORT
      LAYER M4 ;
      RECT 199.928 44.496 200.000 44.520 ;
    END
  END m_axis_cq_tdata[115]
  PIN m_axis_cq_tdata[116]
    DIRECTION OUTPUT ;
    USE SIGNAL ;
    PORT
      LAYER M4 ;
      RECT 199.928 44.640 200.000 44.664 ;
    END
  END m_axis_cq_tdata[116]
  PIN m_axis_cq_tdata[117]
    DIRECTION OUTPUT ;
    USE SIGNAL ;
    PORT
      LAYER M4 ;
      RECT 199.928 44.784 200.000 44.808 ;
    END
  END m_axis_cq_tdata[117]
  PIN m_axis_cq_tdata[118]
    DIRECTION OUTPUT ;
    USE SIGNAL ;
    PORT
      LAYER M4 ;
      RECT 199.928 44.928 200.000 44.952 ;
    END
  END m_axis_cq_tdata[118]
  PIN m_axis_cq_tdata[119]
    DIRECTION OUTPUT ;
    USE SIGNAL ;
    PORT
      LAYER M4 ;
      RECT 199.928 45.072 200.000 45.096 ;
    END
  END m_axis_cq_tdata[119]
  PIN m_axis_cq_tdata[120]
    DIRECTION OUTPUT ;
    USE SIGNAL ;
    PORT
      LAYER M4 ;
      RECT 199.928 45.216 200.000 45.240 ;
    END
  END m_axis_cq_tdata[120]
  PIN m_axis_cq_tdata[121]
    DIRECTION OUTPUT ;
    USE SIGNAL ;
    PORT
      LAYER M4 ;
      RECT 199.928 45.360 200.000 45.384 ;
    END
  END m_axis_cq_tdata[121]
  PIN m_axis_cq_tdata[122]
    DIRECTION OUTPUT ;
    USE SIGNAL ;
    PORT
      LAYER M4 ;
      RECT 199.928 45.504 200.000 45.528 ;
    END
  END m_axis_cq_tdata[122]
  PIN m_axis_cq_tdata[123]
    DIRECTION OUTPUT ;
    USE SIGNAL ;
    PORT
      LAYER M4 ;
      RECT 199.928 45.648 200.000 45.672 ;
    END
  END m_axis_cq_tdata[123]
  PIN m_axis_cq_tdata[124]
    DIRECTION OUTPUT ;
    USE SIGNAL ;
    PORT
      LAYER M4 ;
      RECT 199.928 45.792 200.000 45.816 ;
    END
  END m_axis_cq_tdata[124]
  PIN m_axis_cq_tdata[125]
    DIRECTION OUTPUT ;
    USE SIGNAL ;
    PORT
      LAYER M4 ;
      RECT 199.928 45.936 200.000 45.960 ;
    END
  END m_axis_cq_tdata[125]
  PIN m_axis_cq_tdata[126]
    DIRECTION OUTPUT ;
    USE SIGNAL ;
    PORT
      LAYER M4 ;
      RECT 199.928 46.080 200.000 46.104 ;
    END
  END m_axis_cq_tdata[126]
  PIN m_axis_cq_tdata[127]
    DIRECTION OUTPUT ;
    USE SIGNAL ;
    PORT
      LAYER M4 ;
      RECT 199.928 46.224 200.000 46.248 ;
    END
  END m_axis_cq_tdata[127]
  PIN m_axis_cq_tkeep[0]
    DIRECTION OUTPUT ;
    USE SIGNAL ;
    PORT
      LAYER M4 ;
      RECT 199.928 46.368 200.000 46.392 ;
    END
  END m_axis_cq_tkeep[0]
  PIN m_axis_cq_tkeep[1]
    DIRECTION OUTPUT ;
    USE SIGNAL ;
    PORT
      LAYER M4 ;
      RECT 199.928 46.512 200.000 46.536 ;
    END
  END m_axis_cq_tkeep[1]
  PIN m_axis_cq_tkeep[2]
    DIRECTION OUTPUT ;
    USE SIGNAL ;
    PORT
      LAYER M4 ;
      RECT 199.928 46.656 200.000 46.680 ;
    END
  END m_axis_cq_tkeep[2]
  PIN m_axis_cq_tkeep[3]
    DIRECTION OUTPUT ;
    USE SIGNAL ;
    PORT
      LAYER M4 ;
      RECT 199.928 46.800 200.000 46.824 ;
    END
  END m_axis_cq_tkeep[3]
  PIN m_axis_cq_tlast
    DIRECTION OUTPUT ;
    USE SIGNAL ;
    PORT
      LAYER M4 ;
      RECT 199.928 46.944 200.000 46.968 ;
    END
  END m_axis_cq_tlast
  PIN m_axis_cq_tuser[0]
    DIRECTION OUTPUT ;
    USE SIGNAL ;
    PORT
      LAYER M4 ;
      RECT 199.928 47.088 200.000 47.112 ;
    END
  END m_axis_cq_tuser[0]
  PIN m_axis_cq_tuser[1]
    DIRECTION OUTPUT ;
    USE SIGNAL ;
    PORT
      LAYER M4 ;
      RECT 199.928 47.232 200.000 47.256 ;
    END
  END m_axis_cq_tuser[1]
  PIN m_axis_cq_tuser[2]
    DIRECTION OUTPUT ;
    USE SIGNAL ;
    PORT
      LAYER M4 ;
      RECT 199.928 47.376 200.000 47.400 ;
    END
  END m_axis_cq_tuser[2]
  PIN m_axis_cq_tuser[3]
    DIRECTION OUTPUT ;
    USE SIGNAL ;
    PORT
      LAYER M4 ;
      RECT 199.928 47.520 200.000 47.544 ;
    END
  END m_axis_cq_tuser[3]
  PIN m_axis_cq_tuser[4]
    DIRECTION OUTPUT ;
    USE SIGNAL ;
    PORT
      LAYER M4 ;
      RECT 199.928 47.664 200.000 47.688 ;
    END
  END m_axis_cq_tuser[4]
  PIN m_axis_cq_tuser[5]
    DIRECTION OUTPUT ;
    USE SIGNAL ;
    PORT
      LAYER M4 ;
      RECT 199.928 47.808 200.000 47.832 ;
    END
  END m_axis_cq_tuser[5]
  PIN m_axis_cq_tuser[6]
    DIRECTION OUTPUT ;
    USE SIGNAL ;
    PORT
      LAYER M4 ;
      RECT 199.928 47.952 200.000 47.976 ;
    END
  END m_axis_cq_tuser[6]
  PIN m_axis_cq_tuser[7]
    DIRECTION OUTPUT ;
    USE SIGNAL ;
    PORT
      LAYER M4 ;
      RECT 199.928 48.096 200.000 48.120 ;
    END
  END m_axis_cq_tuser[7]
  PIN m_axis_cq_tuser[8]
    DIRECTION OUTPUT ;
    USE SIGNAL ;
    PORT
      LAYER M4 ;
      RECT 199.928 48.240 200.000 48.264 ;
    END
  END m_axis_cq_tuser[8]
  PIN m_axis_cq_tuser[9]
    DIRECTION OUTPUT ;
    USE SIGNAL ;
    PORT
      LAYER M4 ;
      RECT 199.928 48.384 200.000 48.408 ;
    END
  END m_axis_cq_tuser[9]
  PIN m_axis_cq_tuser[10]
    DIRECTION OUTPUT ;
    USE SIGNAL ;
    PORT
      LAYER M4 ;
      RECT 199.928 48.528 200.000 48.552 ;
    END
  END m_axis_cq_tuser[10]
  PIN m_axis_cq_tuser[11]
    DIRECTION OUTPUT ;
    USE SIGNAL ;
    PORT
      LAYER M4 ;
      RECT 199.928 48.672 200.000 48.696 ;
    END
  END m_axis_cq_tuser[11]
  PIN m_axis_cq_tuser[12]
    DIRECTION OUTPUT ;
    USE SIGNAL ;
    PORT
      LAYER M4 ;
      RECT 199.928 48.816 200.000 48.840 ;
    END
  END m_axis_cq_tuser[12]
  PIN m_axis_cq_tuser[13]
    DIRECTION OUTPUT ;
    USE SIGNAL ;
    PORT
      LAYER M4 ;
      RECT 199.928 48.960 200.000 48.984 ;
    END
  END m_axis_cq_tuser[13]
  PIN m_axis_cq_tuser[14]
    DIRECTION OUTPUT ;
    USE SIGNAL ;
    PORT
      LAYER M4 ;
      RECT 199.928 49.104 200.000 49.128 ;
    END
  END m_axis_cq_tuser[14]
  PIN m_axis_cq_tuser[15]
    DIRECTION OUTPUT ;
    USE SIGNAL ;
    PORT
      LAYER M4 ;
      RECT 199.928 49.248 200.000 49.272 ;
    END
  END m_axis_cq_tuser[15]
  PIN m_axis_cq_tuser[16]
    DIRECTION OUTPUT ;
    USE SIGNAL ;
    PORT
      LAYER M4 ;
      RECT 199.928 49.392 200.000 49.416 ;
    END
  END m_axis_cq_tuser[16]
  PIN m_axis_cq_tuser[17]
    DIRECTION OUTPUT ;
    USE SIGNAL ;
    PORT
      LAYER M4 ;
      RECT 199.928 49.536 200.000 49.560 ;
    END
  END m_axis_cq_tuser[17]
  PIN m_axis_cq_tuser[18]
    DIRECTION OUTPUT ;
    USE SIGNAL ;
    PORT
      LAYER M4 ;
      RECT 199.928 49.680 200.000 49.704 ;
    END
  END m_axis_cq_tuser[18]
  PIN m_axis_cq_tuser[19]
    DIRECTION OUTPUT ;
    USE SIGNAL ;
    PORT
      LAYER M4 ;
      RECT 199.928 49.824 200.000 49.848 ;
    END
  END m_axis_cq_tuser[19]
  PIN m_axis_cq_tuser[20]
    DIRECTION OUTPUT ;
    USE SIGNAL ;
    PORT
      LAYER M4 ;
      RECT 199.928 49.968 200.000 49.992 ;
    END
  END m_axis_cq_tuser[20]
  PIN m_axis_cq_tuser[21]
    DIRECTION OUTPUT ;
    USE SIGNAL ;
    PORT
      LAYER M4 ;
      RECT 199.928 50.112 200.000 50.136 ;
    END
  END m_axis_cq_tuser[21]
  PIN m_axis_cq_tuser[22]
    DIRECTION OUTPUT ;
    USE SIGNAL ;
    PORT
      LAYER M4 ;
      RECT 199.928 50.256 200.000 50.280 ;
    END
  END m_axis_cq_tuser[22]
  PIN m_axis_cq_tuser[23]
    DIRECTION OUTPUT ;
    USE SIGNAL ;
    PORT
      LAYER M4 ;
      RECT 199.928 50.400 200.000 50.424 ;
    END
  END m_axis_cq_tuser[23]
  PIN m_axis_cq_tuser[24]
    DIRECTION OUTPUT ;
    USE SIGNAL ;
    PORT
      LAYER M4 ;
      RECT 199.928 50.544 200.000 50.568 ;
    END
  END m_axis_cq_tuser[24]
  PIN m_axis_cq_tuser[25]
    DIRECTION OUTPUT ;
    USE SIGNAL ;
    PORT
      LAYER M4 ;
      RECT 199.928 50.688 200.000 50.712 ;
    END
  END m_axis_cq_tuser[25]
  PIN m_axis_cq_tuser[26]
    DIRECTION OUTPUT ;
    USE SIGNAL ;
    PORT
      LAYER M4 ;
      RECT 199.928 50.832 200.000 50.856 ;
    END
  END m_axis_cq_tuser[26]
  PIN m_axis_cq_tuser[27]
    DIRECTION OUTPUT ;
    USE SIGNAL ;
    PORT
      LAYER M4 ;
      RECT 199.928 50.976 200.000 51.000 ;
    END
  END m_axis_cq_tuser[27]
  PIN m_axis_cq_tuser[28]
    DIRECTION OUTPUT ;
    USE SIGNAL ;
    PORT
      LAYER M4 ;
      RECT 199.928 51.120 200.000 51.144 ;
    END
  END m_axis_cq_tuser[28]
  PIN m_axis_cq_tuser[29]
    DIRECTION OUTPUT ;
    USE SIGNAL ;
    PORT
      LAYER M4 ;
      RECT 199.928 51.264 200.000 51.288 ;
    END
  END m_axis_cq_tuser[29]
  PIN m_axis_cq_tuser[30]
    DIRECTION OUTPUT ;
    USE SIGNAL ;
    PORT
      LAYER M4 ;
      RECT 199.928 51.408 200.000 51.432 ;
    END
  END m_axis_cq_tuser[30]
  PIN m_axis_cq_tuser[31]
    DIRECTION OUTPUT ;
    USE SIGNAL ;
    PORT
      LAYER M4 ;
      RECT 199.928 51.552 200.000 51.576 ;
    END
  END m_axis_cq_tuser[31]
  PIN m_axis_cq_tuser[32]
    DIRECTION OUTPUT ;
    USE SIGNAL ;
    PORT
      LAYER M4 ;
      RECT 199.928 51.696 200.000 51.720 ;
    END
  END m_axis_cq_tuser[32]
  PIN m_axis_cq_tuser[33]
    DIRECTION OUTPUT ;
    USE SIGNAL ;
    PORT
      LAYER M4 ;
      RECT 199.928 51.840 200.000 51.864 ;
    END
  END m_axis_cq_tuser[33]
  PIN m_axis_cq_tuser[34]
    DIRECTION OUTPUT ;
    USE SIGNAL ;
    PORT
      LAYER M4 ;
      RECT 199.928 51.984 200.000 52.008 ;
    END
  END m_axis_cq_tuser[34]
  PIN m_axis_cq_tuser[35]
    DIRECTION OUTPUT ;
    USE SIGNAL ;
    PORT
      LAYER M4 ;
      RECT 199.928 52.128 200.000 52.152 ;
    END
  END m_axis_cq_tuser[35]
  PIN m_axis_cq_tuser[36]
    DIRECTION OUTPUT ;
    USE SIGNAL ;
    PORT
      LAYER M4 ;
      RECT 199.928 52.272 200.000 52.296 ;
    END
  END m_axis_cq_tuser[36]
  PIN m_axis_cq_tuser[37]
    DIRECTION OUTPUT ;
    USE SIGNAL ;
    PORT
      LAYER M4 ;
      RECT 199.928 52.416 200.000 52.440 ;
    END
  END m_axis_cq_tuser[37]
  PIN m_axis_cq_tuser[38]
    DIRECTION OUTPUT ;
    USE SIGNAL ;
    PORT
      LAYER M4 ;
      RECT 199.928 52.560 200.000 52.584 ;
    END
  END m_axis_cq_tuser[38]
  PIN m_axis_cq_tuser[39]
    DIRECTION OUTPUT ;
    USE SIGNAL ;
    PORT
      LAYER M4 ;
      RECT 199.928 52.704 200.000 52.728 ;
    END
  END m_axis_cq_tuser[39]
  PIN m_axis_cq_tuser[40]
    DIRECTION OUTPUT ;
    USE SIGNAL ;
    PORT
      LAYER M4 ;
      RECT 199.928 52.848 200.000 52.872 ;
    END
  END m_axis_cq_tuser[40]
  PIN m_axis_cq_tuser[41]
    DIRECTION OUTPUT ;
    USE SIGNAL ;
    PORT
      LAYER M4 ;
      RECT 199.928 52.992 200.000 53.016 ;
    END
  END m_axis_cq_tuser[41]
  PIN m_axis_cq_tuser[42]
    DIRECTION OUTPUT ;
    USE SIGNAL ;
    PORT
      LAYER M4 ;
      RECT 199.928 53.136 200.000 53.160 ;
    END
  END m_axis_cq_tuser[42]
  PIN m_axis_cq_tuser[43]
    DIRECTION OUTPUT ;
    USE SIGNAL ;
    PORT
      LAYER M4 ;
      RECT 199.928 53.280 200.000 53.304 ;
    END
  END m_axis_cq_tuser[43]
  PIN m_axis_cq_tuser[44]
    DIRECTION OUTPUT ;
    USE SIGNAL ;
    PORT
      LAYER M4 ;
      RECT 199.928 53.424 200.000 53.448 ;
    END
  END m_axis_cq_tuser[44]
  PIN m_axis_cq_tuser[45]
    DIRECTION OUTPUT ;
    USE SIGNAL ;
    PORT
      LAYER M4 ;
      RECT 199.928 53.568 200.000 53.592 ;
    END
  END m_axis_cq_tuser[45]
  PIN m_axis_cq_tuser[46]
    DIRECTION OUTPUT ;
    USE SIGNAL ;
    PORT
      LAYER M4 ;
      RECT 199.928 53.712 200.000 53.736 ;
    END
  END m_axis_cq_tuser[46]
  PIN m_axis_cq_tuser[47]
    DIRECTION OUTPUT ;
    USE SIGNAL ;
    PORT
      LAYER M4 ;
      RECT 199.928 53.856 200.000 53.880 ;
    END
  END m_axis_cq_tuser[47]
  PIN m_axis_cq_tuser[48]
    DIRECTION OUTPUT ;
    USE SIGNAL ;
    PORT
      LAYER M4 ;
      RECT 199.928 54.000 200.000 54.024 ;
    END
  END m_axis_cq_tuser[48]
  PIN m_axis_cq_tuser[49]
    DIRECTION OUTPUT ;
    USE SIGNAL ;
    PORT
      LAYER M4 ;
      RECT 199.928 54.144 200.000 54.168 ;
    END
  END m_axis_cq_tuser[49]
  PIN m_axis_cq_tuser[50]
    DIRECTION OUTPUT ;
    USE SIGNAL ;
    PORT
      LAYER M4 ;
      RECT 199.928 54.288 200.000 54.312 ;
    END
  END m_axis_cq_tuser[50]
  PIN m_axis_cq_tuser[51]
    DIRECTION OUTPUT ;
    USE SIGNAL ;
    PORT
      LAYER M4 ;
      RECT 199.928 54.432 200.000 54.456 ;
    END
  END m_axis_cq_tuser[51]
  PIN m_axis_cq_tuser[52]
    DIRECTION OUTPUT ;
    USE SIGNAL ;
    PORT
      LAYER M4 ;
      RECT 199.928 54.576 200.000 54.600 ;
    END
  END m_axis_cq_tuser[52]
  PIN m_axis_cq_tuser[53]
    DIRECTION OUTPUT ;
    USE SIGNAL ;
    PORT
      LAYER M4 ;
      RECT 199.928 54.720 200.000 54.744 ;
    END
  END m_axis_cq_tuser[53]
  PIN m_axis_cq_tuser[54]
    DIRECTION OUTPUT ;
    USE SIGNAL ;
    PORT
      LAYER M4 ;
      RECT 199.928 54.864 200.000 54.888 ;
    END
  END m_axis_cq_tuser[54]
  PIN m_axis_cq_tuser[55]
    DIRECTION OUTPUT ;
    USE SIGNAL ;
    PORT
      LAYER M4 ;
      RECT 199.928 55.008 200.000 55.032 ;
    END
  END m_axis_cq_tuser[55]
  PIN m_axis_cq_tuser[56]
    DIRECTION OUTPUT ;
    USE SIGNAL ;
    PORT
      LAYER M4 ;
      RECT 199.928 55.152 200.000 55.176 ;
    END
  END m_axis_cq_tuser[56]
  PIN m_axis_cq_tuser[57]
    DIRECTION OUTPUT ;
    USE SIGNAL ;
    PORT
      LAYER M4 ;
      RECT 199.928 55.296 200.000 55.320 ;
    END
  END m_axis_cq_tuser[57]
  PIN m_axis_cq_tuser[58]
    DIRECTION OUTPUT ;
    USE SIGNAL ;
    PORT
      LAYER M4 ;
      RECT 199.928 55.440 200.000 55.464 ;
    END
  END m_axis_cq_tuser[58]
  PIN m_axis_cq_tuser[59]
    DIRECTION OUTPUT ;
    USE SIGNAL ;
    PORT
      LAYER M4 ;
      RECT 199.928 55.584 200.000 55.608 ;
    END
  END m_axis_cq_tuser[59]
  PIN m_axis_cq_tuser[60]
    DIRECTION OUTPUT ;
    USE SIGNAL ;
    PORT
      LAYER M4 ;
      RECT 199.928 55.728 200.000 55.752 ;
    END
  END m_axis_cq_tuser[60]
  PIN m_axis_cq_tuser[61]
    DIRECTION OUTPUT ;
    USE SIGNAL ;
    PORT
      LAYER M4 ;
      RECT 199.928 55.872 200.000 55.896 ;
    END
  END m_axis_cq_tuser[61]
  PIN m_axis_cq_tuser[62]
    DIRECTION OUTPUT ;
    USE SIGNAL ;
    PORT
      LAYER M4 ;
      RECT 199.928 56.016 200.000 56.040 ;
    END
  END m_axis_cq_tuser[62]
  PIN m_axis_cq_tuser[63]
    DIRECTION OUTPUT ;
    USE SIGNAL ;
    PORT
      LAYER M4 ;
      RECT 199.928 56.160 200.000 56.184 ;
    END
  END m_axis_cq_tuser[63]
  PIN m_axis_cq_tuser[64]
    DIRECTION OUTPUT ;
    USE SIGNAL ;
    PORT
      LAYER M4 ;
      RECT 199.928 56.304 200.000 56.328 ;
    END
  END m_axis_cq_tuser[64]
  PIN m_axis_cq_tuser[65]
    DIRECTION OUTPUT ;
    USE SIGNAL ;
    PORT
      LAYER M4 ;
      RECT 199.928 56.448 200.000 56.472 ;
    END
  END m_axis_cq_tuser[65]
  PIN m_axis_cq_tuser[66]
    DIRECTION OUTPUT ;
    USE SIGNAL ;
    PORT
      LAYER M4 ;
      RECT 199.928 56.592 200.000 56.616 ;
    END
  END m_axis_cq_tuser[66]
  PIN m_axis_cq_tuser[67]
    DIRECTION OUTPUT ;
    USE SIGNAL ;
    PORT
      LAYER M4 ;
      RECT 199.928 56.736 200.000 56.760 ;
    END
  END m_axis_cq_tuser[67]
  PIN m_axis_cq_tuser[68]
    DIRECTION OUTPUT ;
    USE SIGNAL ;
    PORT
      LAYER M4 ;
      RECT 199.928 56.880 200.000 56.904 ;
    END
  END m_axis_cq_tuser[68]
  PIN m_axis_cq_tuser[69]
    DIRECTION OUTPUT ;
    USE SIGNAL ;
    PORT
      LAYER M4 ;
      RECT 199.928 57.024 200.000 57.048 ;
    END
  END m_axis_cq_tuser[69]
  PIN m_axis_cq_tuser[70]
    DIRECTION OUTPUT ;
    USE SIGNAL ;
    PORT
      LAYER M4 ;
      RECT 199.928 57.168 200.000 57.192 ;
    END
  END m_axis_cq_tuser[70]
  PIN m_axis_cq_tuser[71]
    DIRECTION OUTPUT ;
    USE SIGNAL ;
    PORT
      LAYER M4 ;
      RECT 199.928 57.312 200.000 57.336 ;
    END
  END m_axis_cq_tuser[71]
  PIN m_axis_cq_tuser[72]
    DIRECTION OUTPUT ;
    USE SIGNAL ;
    PORT
      LAYER M4 ;
      RECT 199.928 57.456 200.000 57.480 ;
    END
  END m_axis_cq_tuser[72]
  PIN m_axis_cq_tuser[73]
    DIRECTION OUTPUT ;
    USE SIGNAL ;
    PORT
      LAYER M4 ;
      RECT 199.928 57.600 200.000 57.624 ;
    END
  END m_axis_cq_tuser[73]
  PIN m_axis_cq_tuser[74]
    DIRECTION OUTPUT ;
    USE SIGNAL ;
    PORT
      LAYER M4 ;
      RECT 199.928 57.744 200.000 57.768 ;
    END
  END m_axis_cq_tuser[74]
  PIN m_axis_cq_tuser[75]
    DIRECTION OUTPUT ;
    USE SIGNAL ;
    PORT
      LAYER M4 ;
      RECT 199.928 57.888 200.000 57.912 ;
    END
  END m_axis_cq_tuser[75]
  PIN m_axis_cq_tuser[76]
    DIRECTION OUTPUT ;
    USE SIGNAL ;
    PORT
      LAYER M4 ;
      RECT 199.928 58.032 200.000 58.056 ;
    END
  END m_axis_cq_tuser[76]
  PIN m_axis_cq_tuser[77]
    DIRECTION OUTPUT ;
    USE SIGNAL ;
    PORT
      LAYER M4 ;
      RECT 199.928 58.176 200.000 58.200 ;
    END
  END m_axis_cq_tuser[77]
  PIN m_axis_cq_tuser[78]
    DIRECTION OUTPUT ;
    USE SIGNAL ;
    PORT
      LAYER M4 ;
      RECT 199.928 58.320 200.000 58.344 ;
    END
  END m_axis_cq_tuser[78]
  PIN m_axis_cq_tuser[79]
    DIRECTION OUTPUT ;
    USE SIGNAL ;
    PORT
      LAYER M4 ;
      RECT 199.928 58.464 200.000 58.488 ;
    END
  END m_axis_cq_tuser[79]
  PIN m_axis_cq_tuser[80]
    DIRECTION OUTPUT ;
    USE SIGNAL ;
    PORT
      LAYER M4 ;
      RECT 199.928 58.608 200.000 58.632 ;
    END
  END m_axis_cq_tuser[80]
  PIN m_axis_cq_tuser[81]
    DIRECTION OUTPUT ;
    USE SIGNAL ;
    PORT
      LAYER M4 ;
      RECT 199.928 58.752 200.000 58.776 ;
    END
  END m_axis_cq_tuser[81]
  PIN m_axis_cq_tuser[82]
    DIRECTION OUTPUT ;
    USE SIGNAL ;
    PORT
      LAYER M4 ;
      RECT 199.928 58.896 200.000 58.920 ;
    END
  END m_axis_cq_tuser[82]
  PIN m_axis_cq_tuser[83]
    DIRECTION OUTPUT ;
    USE SIGNAL ;
    PORT
      LAYER M4 ;
      RECT 199.928 59.040 200.000 59.064 ;
    END
  END m_axis_cq_tuser[83]
  PIN m_axis_cq_tuser[84]
    DIRECTION OUTPUT ;
    USE SIGNAL ;
    PORT
      LAYER M4 ;
      RECT 199.928 59.184 200.000 59.208 ;
    END
  END m_axis_cq_tuser[84]
  PIN m_axis_cq_tuser[85]
    DIRECTION OUTPUT ;
    USE SIGNAL ;
    PORT
      LAYER M4 ;
      RECT 199.928 59.328 200.000 59.352 ;
    END
  END m_axis_cq_tuser[85]
  PIN m_axis_cq_tuser[86]
    DIRECTION OUTPUT ;
    USE SIGNAL ;
    PORT
      LAYER M4 ;
      RECT 199.928 59.472 200.000 59.496 ;
    END
  END m_axis_cq_tuser[86]
  PIN m_axis_cq_tuser[87]
    DIRECTION OUTPUT ;
    USE SIGNAL ;
    PORT
      LAYER M4 ;
      RECT 199.928 59.616 200.000 59.640 ;
    END
  END m_axis_cq_tuser[87]
  PIN m_axis_cq_tvalid
    DIRECTION OUTPUT ;
    USE SIGNAL ;
    PORT
      LAYER M4 ;
      RECT 199.928 59.760 200.000 59.784 ;
    END
  END m_axis_cq_tvalid
  PIN m_axis_rc_tdata[0]
    DIRECTION OUTPUT ;
    USE SIGNAL ;
    PORT
      LAYER M4 ;
      RECT 199.928 59.904 200.000 59.928 ;
    END
  END m_axis_rc_tdata[0]
  PIN m_axis_rc_tdata[1]
    DIRECTION OUTPUT ;
    USE SIGNAL ;
    PORT
      LAYER M4 ;
      RECT 199.928 60.048 200.000 60.072 ;
    END
  END m_axis_rc_tdata[1]
  PIN m_axis_rc_tdata[2]
    DIRECTION OUTPUT ;
    USE SIGNAL ;
    PORT
      LAYER M4 ;
      RECT 199.928 60.192 200.000 60.216 ;
    END
  END m_axis_rc_tdata[2]
  PIN m_axis_rc_tdata[3]
    DIRECTION OUTPUT ;
    USE SIGNAL ;
    PORT
      LAYER M4 ;
      RECT 199.928 60.336 200.000 60.360 ;
    END
  END m_axis_rc_tdata[3]
  PIN m_axis_rc_tdata[4]
    DIRECTION OUTPUT ;
    USE SIGNAL ;
    PORT
      LAYER M4 ;
      RECT 199.928 60.480 200.000 60.504 ;
    END
  END m_axis_rc_tdata[4]
  PIN m_axis_rc_tdata[5]
    DIRECTION OUTPUT ;
    USE SIGNAL ;
    PORT
      LAYER M4 ;
      RECT 199.928 60.624 200.000 60.648 ;
    END
  END m_axis_rc_tdata[5]
  PIN m_axis_rc_tdata[6]
    DIRECTION OUTPUT ;
    USE SIGNAL ;
    PORT
      LAYER M4 ;
      RECT 199.928 60.768 200.000 60.792 ;
    END
  END m_axis_rc_tdata[6]
  PIN m_axis_rc_tdata[7]
    DIRECTION OUTPUT ;
    USE SIGNAL ;
    PORT
      LAYER M4 ;
      RECT 199.928 60.912 200.000 60.936 ;
    END
  END m_axis_rc_tdata[7]
  PIN m_axis_rc_tdata[8]
    DIRECTION OUTPUT ;
    USE SIGNAL ;
    PORT
      LAYER M4 ;
      RECT 199.928 61.056 200.000 61.080 ;
    END
  END m_axis_rc_tdata[8]
  PIN m_axis_rc_tdata[9]
    DIRECTION OUTPUT ;
    USE SIGNAL ;
    PORT
      LAYER M4 ;
      RECT 199.928 61.200 200.000 61.224 ;
    END
  END m_axis_rc_tdata[9]
  PIN m_axis_rc_tdata[10]
    DIRECTION OUTPUT ;
    USE SIGNAL ;
    PORT
      LAYER M4 ;
      RECT 199.928 61.344 200.000 61.368 ;
    END
  END m_axis_rc_tdata[10]
  PIN m_axis_rc_tdata[11]
    DIRECTION OUTPUT ;
    USE SIGNAL ;
    PORT
      LAYER M4 ;
      RECT 199.928 61.488 200.000 61.512 ;
    END
  END m_axis_rc_tdata[11]
  PIN m_axis_rc_tdata[12]
    DIRECTION OUTPUT ;
    USE SIGNAL ;
    PORT
      LAYER M4 ;
      RECT 199.928 61.632 200.000 61.656 ;
    END
  END m_axis_rc_tdata[12]
  PIN m_axis_rc_tdata[13]
    DIRECTION OUTPUT ;
    USE SIGNAL ;
    PORT
      LAYER M4 ;
      RECT 199.928 61.776 200.000 61.800 ;
    END
  END m_axis_rc_tdata[13]
  PIN m_axis_rc_tdata[14]
    DIRECTION OUTPUT ;
    USE SIGNAL ;
    PORT
      LAYER M4 ;
      RECT 199.928 61.920 200.000 61.944 ;
    END
  END m_axis_rc_tdata[14]
  PIN m_axis_rc_tdata[15]
    DIRECTION OUTPUT ;
    USE SIGNAL ;
    PORT
      LAYER M4 ;
      RECT 199.928 62.064 200.000 62.088 ;
    END
  END m_axis_rc_tdata[15]
  PIN m_axis_rc_tdata[16]
    DIRECTION OUTPUT ;
    USE SIGNAL ;
    PORT
      LAYER M4 ;
      RECT 199.928 62.208 200.000 62.232 ;
    END
  END m_axis_rc_tdata[16]
  PIN m_axis_rc_tdata[17]
    DIRECTION OUTPUT ;
    USE SIGNAL ;
    PORT
      LAYER M4 ;
      RECT 199.928 62.352 200.000 62.376 ;
    END
  END m_axis_rc_tdata[17]
  PIN m_axis_rc_tdata[18]
    DIRECTION OUTPUT ;
    USE SIGNAL ;
    PORT
      LAYER M4 ;
      RECT 199.928 62.496 200.000 62.520 ;
    END
  END m_axis_rc_tdata[18]
  PIN m_axis_rc_tdata[19]
    DIRECTION OUTPUT ;
    USE SIGNAL ;
    PORT
      LAYER M4 ;
      RECT 199.928 62.640 200.000 62.664 ;
    END
  END m_axis_rc_tdata[19]
  PIN m_axis_rc_tdata[20]
    DIRECTION OUTPUT ;
    USE SIGNAL ;
    PORT
      LAYER M4 ;
      RECT 199.928 62.784 200.000 62.808 ;
    END
  END m_axis_rc_tdata[20]
  PIN m_axis_rc_tdata[21]
    DIRECTION OUTPUT ;
    USE SIGNAL ;
    PORT
      LAYER M4 ;
      RECT 199.928 62.928 200.000 62.952 ;
    END
  END m_axis_rc_tdata[21]
  PIN m_axis_rc_tdata[22]
    DIRECTION OUTPUT ;
    USE SIGNAL ;
    PORT
      LAYER M4 ;
      RECT 199.928 63.072 200.000 63.096 ;
    END
  END m_axis_rc_tdata[22]
  PIN m_axis_rc_tdata[23]
    DIRECTION OUTPUT ;
    USE SIGNAL ;
    PORT
      LAYER M4 ;
      RECT 199.928 63.216 200.000 63.240 ;
    END
  END m_axis_rc_tdata[23]
  PIN m_axis_rc_tdata[24]
    DIRECTION OUTPUT ;
    USE SIGNAL ;
    PORT
      LAYER M4 ;
      RECT 199.928 63.360 200.000 63.384 ;
    END
  END m_axis_rc_tdata[24]
  PIN m_axis_rc_tdata[25]
    DIRECTION OUTPUT ;
    USE SIGNAL ;
    PORT
      LAYER M4 ;
      RECT 199.928 63.504 200.000 63.528 ;
    END
  END m_axis_rc_tdata[25]
  PIN m_axis_rc_tdata[26]
    DIRECTION OUTPUT ;
    USE SIGNAL ;
    PORT
      LAYER M4 ;
      RECT 199.928 63.648 200.000 63.672 ;
    END
  END m_axis_rc_tdata[26]
  PIN m_axis_rc_tdata[27]
    DIRECTION OUTPUT ;
    USE SIGNAL ;
    PORT
      LAYER M4 ;
      RECT 199.928 63.792 200.000 63.816 ;
    END
  END m_axis_rc_tdata[27]
  PIN m_axis_rc_tdata[28]
    DIRECTION OUTPUT ;
    USE SIGNAL ;
    PORT
      LAYER M4 ;
      RECT 199.928 63.936 200.000 63.960 ;
    END
  END m_axis_rc_tdata[28]
  PIN m_axis_rc_tdata[29]
    DIRECTION OUTPUT ;
    USE SIGNAL ;
    PORT
      LAYER M4 ;
      RECT 199.928 64.080 200.000 64.104 ;
    END
  END m_axis_rc_tdata[29]
  PIN m_axis_rc_tdata[30]
    DIRECTION OUTPUT ;
    USE SIGNAL ;
    PORT
      LAYER M4 ;
      RECT 199.928 64.224 200.000 64.248 ;
    END
  END m_axis_rc_tdata[30]
  PIN m_axis_rc_tdata[31]
    DIRECTION OUTPUT ;
    USE SIGNAL ;
    PORT
      LAYER M4 ;
      RECT 199.928 64.368 200.000 64.392 ;
    END
  END m_axis_rc_tdata[31]
  PIN m_axis_rc_tdata[32]
    DIRECTION OUTPUT ;
    USE SIGNAL ;
    PORT
      LAYER M4 ;
      RECT 199.928 64.512 200.000 64.536 ;
    END
  END m_axis_rc_tdata[32]
  PIN m_axis_rc_tdata[33]
    DIRECTION OUTPUT ;
    USE SIGNAL ;
    PORT
      LAYER M4 ;
      RECT 199.928 64.656 200.000 64.680 ;
    END
  END m_axis_rc_tdata[33]
  PIN m_axis_rc_tdata[34]
    DIRECTION OUTPUT ;
    USE SIGNAL ;
    PORT
      LAYER M4 ;
      RECT 199.928 64.800 200.000 64.824 ;
    END
  END m_axis_rc_tdata[34]
  PIN m_axis_rc_tdata[35]
    DIRECTION OUTPUT ;
    USE SIGNAL ;
    PORT
      LAYER M4 ;
      RECT 199.928 64.944 200.000 64.968 ;
    END
  END m_axis_rc_tdata[35]
  PIN m_axis_rc_tdata[36]
    DIRECTION OUTPUT ;
    USE SIGNAL ;
    PORT
      LAYER M4 ;
      RECT 199.928 65.088 200.000 65.112 ;
    END
  END m_axis_rc_tdata[36]
  PIN m_axis_rc_tdata[37]
    DIRECTION OUTPUT ;
    USE SIGNAL ;
    PORT
      LAYER M4 ;
      RECT 199.928 65.232 200.000 65.256 ;
    END
  END m_axis_rc_tdata[37]
  PIN m_axis_rc_tdata[38]
    DIRECTION OUTPUT ;
    USE SIGNAL ;
    PORT
      LAYER M4 ;
      RECT 199.928 65.376 200.000 65.400 ;
    END
  END m_axis_rc_tdata[38]
  PIN m_axis_rc_tdata[39]
    DIRECTION OUTPUT ;
    USE SIGNAL ;
    PORT
      LAYER M4 ;
      RECT 199.928 65.520 200.000 65.544 ;
    END
  END m_axis_rc_tdata[39]
  PIN m_axis_rc_tdata[40]
    DIRECTION OUTPUT ;
    USE SIGNAL ;
    PORT
      LAYER M4 ;
      RECT 199.928 65.664 200.000 65.688 ;
    END
  END m_axis_rc_tdata[40]
  PIN m_axis_rc_tdata[41]
    DIRECTION OUTPUT ;
    USE SIGNAL ;
    PORT
      LAYER M4 ;
      RECT 199.928 65.808 200.000 65.832 ;
    END
  END m_axis_rc_tdata[41]
  PIN m_axis_rc_tdata[42]
    DIRECTION OUTPUT ;
    USE SIGNAL ;
    PORT
      LAYER M4 ;
      RECT 199.928 65.952 200.000 65.976 ;
    END
  END m_axis_rc_tdata[42]
  PIN m_axis_rc_tdata[43]
    DIRECTION OUTPUT ;
    USE SIGNAL ;
    PORT
      LAYER M4 ;
      RECT 199.928 66.096 200.000 66.120 ;
    END
  END m_axis_rc_tdata[43]
  PIN m_axis_rc_tdata[44]
    DIRECTION OUTPUT ;
    USE SIGNAL ;
    PORT
      LAYER M4 ;
      RECT 199.928 66.240 200.000 66.264 ;
    END
  END m_axis_rc_tdata[44]
  PIN m_axis_rc_tdata[45]
    DIRECTION OUTPUT ;
    USE SIGNAL ;
    PORT
      LAYER M4 ;
      RECT 199.928 66.384 200.000 66.408 ;
    END
  END m_axis_rc_tdata[45]
  PIN m_axis_rc_tdata[46]
    DIRECTION OUTPUT ;
    USE SIGNAL ;
    PORT
      LAYER M4 ;
      RECT 199.928 66.528 200.000 66.552 ;
    END
  END m_axis_rc_tdata[46]
  PIN m_axis_rc_tdata[47]
    DIRECTION OUTPUT ;
    USE SIGNAL ;
    PORT
      LAYER M4 ;
      RECT 199.928 66.672 200.000 66.696 ;
    END
  END m_axis_rc_tdata[47]
  PIN m_axis_rc_tdata[48]
    DIRECTION OUTPUT ;
    USE SIGNAL ;
    PORT
      LAYER M4 ;
      RECT 199.928 66.816 200.000 66.840 ;
    END
  END m_axis_rc_tdata[48]
  PIN m_axis_rc_tdata[49]
    DIRECTION OUTPUT ;
    USE SIGNAL ;
    PORT
      LAYER M4 ;
      RECT 199.928 66.960 200.000 66.984 ;
    END
  END m_axis_rc_tdata[49]
  PIN m_axis_rc_tdata[50]
    DIRECTION OUTPUT ;
    USE SIGNAL ;
    PORT
      LAYER M4 ;
      RECT 199.928 67.104 200.000 67.128 ;
    END
  END m_axis_rc_tdata[50]
  PIN m_axis_rc_tdata[51]
    DIRECTION OUTPUT ;
    USE SIGNAL ;
    PORT
      LAYER M4 ;
      RECT 199.928 67.248 200.000 67.272 ;
    END
  END m_axis_rc_tdata[51]
  PIN m_axis_rc_tdata[52]
    DIRECTION OUTPUT ;
    USE SIGNAL ;
    PORT
      LAYER M4 ;
      RECT 199.928 67.392 200.000 67.416 ;
    END
  END m_axis_rc_tdata[52]
  PIN m_axis_rc_tdata[53]
    DIRECTION OUTPUT ;
    USE SIGNAL ;
    PORT
      LAYER M4 ;
      RECT 199.928 67.536 200.000 67.560 ;
    END
  END m_axis_rc_tdata[53]
  PIN m_axis_rc_tdata[54]
    DIRECTION OUTPUT ;
    USE SIGNAL ;
    PORT
      LAYER M4 ;
      RECT 199.928 67.680 200.000 67.704 ;
    END
  END m_axis_rc_tdata[54]
  PIN m_axis_rc_tdata[55]
    DIRECTION OUTPUT ;
    USE SIGNAL ;
    PORT
      LAYER M4 ;
      RECT 199.928 67.824 200.000 67.848 ;
    END
  END m_axis_rc_tdata[55]
  PIN m_axis_rc_tdata[56]
    DIRECTION OUTPUT ;
    USE SIGNAL ;
    PORT
      LAYER M4 ;
      RECT 199.928 67.968 200.000 67.992 ;
    END
  END m_axis_rc_tdata[56]
  PIN m_axis_rc_tdata[57]
    DIRECTION OUTPUT ;
    USE SIGNAL ;
    PORT
      LAYER M4 ;
      RECT 199.928 68.112 200.000 68.136 ;
    END
  END m_axis_rc_tdata[57]
  PIN m_axis_rc_tdata[58]
    DIRECTION OUTPUT ;
    USE SIGNAL ;
    PORT
      LAYER M4 ;
      RECT 199.928 68.256 200.000 68.280 ;
    END
  END m_axis_rc_tdata[58]
  PIN m_axis_rc_tdata[59]
    DIRECTION OUTPUT ;
    USE SIGNAL ;
    PORT
      LAYER M4 ;
      RECT 199.928 68.400 200.000 68.424 ;
    END
  END m_axis_rc_tdata[59]
  PIN m_axis_rc_tdata[60]
    DIRECTION OUTPUT ;
    USE SIGNAL ;
    PORT
      LAYER M4 ;
      RECT 199.928 68.544 200.000 68.568 ;
    END
  END m_axis_rc_tdata[60]
  PIN m_axis_rc_tdata[61]
    DIRECTION OUTPUT ;
    USE SIGNAL ;
    PORT
      LAYER M4 ;
      RECT 199.928 68.688 200.000 68.712 ;
    END
  END m_axis_rc_tdata[61]
  PIN m_axis_rc_tdata[62]
    DIRECTION OUTPUT ;
    USE SIGNAL ;
    PORT
      LAYER M4 ;
      RECT 199.928 68.832 200.000 68.856 ;
    END
  END m_axis_rc_tdata[62]
  PIN m_axis_rc_tdata[63]
    DIRECTION OUTPUT ;
    USE SIGNAL ;
    PORT
      LAYER M4 ;
      RECT 199.928 68.976 200.000 69.000 ;
    END
  END m_axis_rc_tdata[63]
  PIN m_axis_rc_tdata[64]
    DIRECTION OUTPUT ;
    USE SIGNAL ;
    PORT
      LAYER M4 ;
      RECT 199.928 69.120 200.000 69.144 ;
    END
  END m_axis_rc_tdata[64]
  PIN m_axis_rc_tdata[65]
    DIRECTION OUTPUT ;
    USE SIGNAL ;
    PORT
      LAYER M4 ;
      RECT 199.928 69.264 200.000 69.288 ;
    END
  END m_axis_rc_tdata[65]
  PIN m_axis_rc_tdata[66]
    DIRECTION OUTPUT ;
    USE SIGNAL ;
    PORT
      LAYER M4 ;
      RECT 199.928 69.408 200.000 69.432 ;
    END
  END m_axis_rc_tdata[66]
  PIN m_axis_rc_tdata[67]
    DIRECTION OUTPUT ;
    USE SIGNAL ;
    PORT
      LAYER M4 ;
      RECT 199.928 69.552 200.000 69.576 ;
    END
  END m_axis_rc_tdata[67]
  PIN m_axis_rc_tdata[68]
    DIRECTION OUTPUT ;
    USE SIGNAL ;
    PORT
      LAYER M4 ;
      RECT 199.928 69.696 200.000 69.720 ;
    END
  END m_axis_rc_tdata[68]
  PIN m_axis_rc_tdata[69]
    DIRECTION OUTPUT ;
    USE SIGNAL ;
    PORT
      LAYER M4 ;
      RECT 199.928 69.840 200.000 69.864 ;
    END
  END m_axis_rc_tdata[69]
  PIN m_axis_rc_tdata[70]
    DIRECTION OUTPUT ;
    USE SIGNAL ;
    PORT
      LAYER M4 ;
      RECT 199.928 69.984 200.000 70.008 ;
    END
  END m_axis_rc_tdata[70]
  PIN m_axis_rc_tdata[71]
    DIRECTION OUTPUT ;
    USE SIGNAL ;
    PORT
      LAYER M4 ;
      RECT 199.928 70.128 200.000 70.152 ;
    END
  END m_axis_rc_tdata[71]
  PIN m_axis_rc_tdata[72]
    DIRECTION OUTPUT ;
    USE SIGNAL ;
    PORT
      LAYER M4 ;
      RECT 199.928 70.272 200.000 70.296 ;
    END
  END m_axis_rc_tdata[72]
  PIN m_axis_rc_tdata[73]
    DIRECTION OUTPUT ;
    USE SIGNAL ;
    PORT
      LAYER M4 ;
      RECT 199.928 70.416 200.000 70.440 ;
    END
  END m_axis_rc_tdata[73]
  PIN m_axis_rc_tdata[74]
    DIRECTION OUTPUT ;
    USE SIGNAL ;
    PORT
      LAYER M4 ;
      RECT 199.928 70.560 200.000 70.584 ;
    END
  END m_axis_rc_tdata[74]
  PIN m_axis_rc_tdata[75]
    DIRECTION OUTPUT ;
    USE SIGNAL ;
    PORT
      LAYER M4 ;
      RECT 199.928 70.704 200.000 70.728 ;
    END
  END m_axis_rc_tdata[75]
  PIN m_axis_rc_tdata[76]
    DIRECTION OUTPUT ;
    USE SIGNAL ;
    PORT
      LAYER M4 ;
      RECT 199.928 70.848 200.000 70.872 ;
    END
  END m_axis_rc_tdata[76]
  PIN m_axis_rc_tdata[77]
    DIRECTION OUTPUT ;
    USE SIGNAL ;
    PORT
      LAYER M4 ;
      RECT 199.928 70.992 200.000 71.016 ;
    END
  END m_axis_rc_tdata[77]
  PIN m_axis_rc_tdata[78]
    DIRECTION OUTPUT ;
    USE SIGNAL ;
    PORT
      LAYER M4 ;
      RECT 199.928 71.136 200.000 71.160 ;
    END
  END m_axis_rc_tdata[78]
  PIN m_axis_rc_tdata[79]
    DIRECTION OUTPUT ;
    USE SIGNAL ;
    PORT
      LAYER M4 ;
      RECT 199.928 71.280 200.000 71.304 ;
    END
  END m_axis_rc_tdata[79]
  PIN m_axis_rc_tdata[80]
    DIRECTION OUTPUT ;
    USE SIGNAL ;
    PORT
      LAYER M4 ;
      RECT 199.928 71.424 200.000 71.448 ;
    END
  END m_axis_rc_tdata[80]
  PIN m_axis_rc_tdata[81]
    DIRECTION OUTPUT ;
    USE SIGNAL ;
    PORT
      LAYER M4 ;
      RECT 199.928 71.568 200.000 71.592 ;
    END
  END m_axis_rc_tdata[81]
  PIN m_axis_rc_tdata[82]
    DIRECTION OUTPUT ;
    USE SIGNAL ;
    PORT
      LAYER M4 ;
      RECT 199.928 71.712 200.000 71.736 ;
    END
  END m_axis_rc_tdata[82]
  PIN m_axis_rc_tdata[83]
    DIRECTION OUTPUT ;
    USE SIGNAL ;
    PORT
      LAYER M4 ;
      RECT 199.928 71.856 200.000 71.880 ;
    END
  END m_axis_rc_tdata[83]
  PIN m_axis_rc_tdata[84]
    DIRECTION OUTPUT ;
    USE SIGNAL ;
    PORT
      LAYER M4 ;
      RECT 199.928 72.000 200.000 72.024 ;
    END
  END m_axis_rc_tdata[84]
  PIN m_axis_rc_tdata[85]
    DIRECTION OUTPUT ;
    USE SIGNAL ;
    PORT
      LAYER M4 ;
      RECT 199.928 72.144 200.000 72.168 ;
    END
  END m_axis_rc_tdata[85]
  PIN m_axis_rc_tdata[86]
    DIRECTION OUTPUT ;
    USE SIGNAL ;
    PORT
      LAYER M4 ;
      RECT 199.928 72.288 200.000 72.312 ;
    END
  END m_axis_rc_tdata[86]
  PIN m_axis_rc_tdata[87]
    DIRECTION OUTPUT ;
    USE SIGNAL ;
    PORT
      LAYER M4 ;
      RECT 199.928 72.432 200.000 72.456 ;
    END
  END m_axis_rc_tdata[87]
  PIN m_axis_rc_tdata[88]
    DIRECTION OUTPUT ;
    USE SIGNAL ;
    PORT
      LAYER M4 ;
      RECT 199.928 72.576 200.000 72.600 ;
    END
  END m_axis_rc_tdata[88]
  PIN m_axis_rc_tdata[89]
    DIRECTION OUTPUT ;
    USE SIGNAL ;
    PORT
      LAYER M4 ;
      RECT 199.928 72.720 200.000 72.744 ;
    END
  END m_axis_rc_tdata[89]
  PIN m_axis_rc_tdata[90]
    DIRECTION OUTPUT ;
    USE SIGNAL ;
    PORT
      LAYER M4 ;
      RECT 199.928 72.864 200.000 72.888 ;
    END
  END m_axis_rc_tdata[90]
  PIN m_axis_rc_tdata[91]
    DIRECTION OUTPUT ;
    USE SIGNAL ;
    PORT
      LAYER M4 ;
      RECT 199.928 73.008 200.000 73.032 ;
    END
  END m_axis_rc_tdata[91]
  PIN m_axis_rc_tdata[92]
    DIRECTION OUTPUT ;
    USE SIGNAL ;
    PORT
      LAYER M4 ;
      RECT 199.928 73.152 200.000 73.176 ;
    END
  END m_axis_rc_tdata[92]
  PIN m_axis_rc_tdata[93]
    DIRECTION OUTPUT ;
    USE SIGNAL ;
    PORT
      LAYER M4 ;
      RECT 199.928 73.296 200.000 73.320 ;
    END
  END m_axis_rc_tdata[93]
  PIN m_axis_rc_tdata[94]
    DIRECTION OUTPUT ;
    USE SIGNAL ;
    PORT
      LAYER M4 ;
      RECT 199.928 73.440 200.000 73.464 ;
    END
  END m_axis_rc_tdata[94]
  PIN m_axis_rc_tdata[95]
    DIRECTION OUTPUT ;
    USE SIGNAL ;
    PORT
      LAYER M4 ;
      RECT 199.928 73.584 200.000 73.608 ;
    END
  END m_axis_rc_tdata[95]
  PIN m_axis_rc_tdata[96]
    DIRECTION OUTPUT ;
    USE SIGNAL ;
    PORT
      LAYER M4 ;
      RECT 199.928 73.728 200.000 73.752 ;
    END
  END m_axis_rc_tdata[96]
  PIN m_axis_rc_tdata[97]
    DIRECTION OUTPUT ;
    USE SIGNAL ;
    PORT
      LAYER M4 ;
      RECT 199.928 73.872 200.000 73.896 ;
    END
  END m_axis_rc_tdata[97]
  PIN m_axis_rc_tdata[98]
    DIRECTION OUTPUT ;
    USE SIGNAL ;
    PORT
      LAYER M4 ;
      RECT 199.928 74.016 200.000 74.040 ;
    END
  END m_axis_rc_tdata[98]
  PIN m_axis_rc_tdata[99]
    DIRECTION OUTPUT ;
    USE SIGNAL ;
    PORT
      LAYER M4 ;
      RECT 199.928 74.160 200.000 74.184 ;
    END
  END m_axis_rc_tdata[99]
  PIN m_axis_rc_tdata[100]
    DIRECTION OUTPUT ;
    USE SIGNAL ;
    PORT
      LAYER M4 ;
      RECT 199.928 74.304 200.000 74.328 ;
    END
  END m_axis_rc_tdata[100]
  PIN m_axis_rc_tdata[101]
    DIRECTION OUTPUT ;
    USE SIGNAL ;
    PORT
      LAYER M4 ;
      RECT 199.928 74.448 200.000 74.472 ;
    END
  END m_axis_rc_tdata[101]
  PIN m_axis_rc_tdata[102]
    DIRECTION OUTPUT ;
    USE SIGNAL ;
    PORT
      LAYER M4 ;
      RECT 199.928 74.592 200.000 74.616 ;
    END
  END m_axis_rc_tdata[102]
  PIN m_axis_rc_tdata[103]
    DIRECTION OUTPUT ;
    USE SIGNAL ;
    PORT
      LAYER M4 ;
      RECT 199.928 74.736 200.000 74.760 ;
    END
  END m_axis_rc_tdata[103]
  PIN m_axis_rc_tdata[104]
    DIRECTION OUTPUT ;
    USE SIGNAL ;
    PORT
      LAYER M4 ;
      RECT 199.928 74.880 200.000 74.904 ;
    END
  END m_axis_rc_tdata[104]
  PIN m_axis_rc_tdata[105]
    DIRECTION OUTPUT ;
    USE SIGNAL ;
    PORT
      LAYER M4 ;
      RECT 199.928 75.024 200.000 75.048 ;
    END
  END m_axis_rc_tdata[105]
  PIN m_axis_rc_tdata[106]
    DIRECTION OUTPUT ;
    USE SIGNAL ;
    PORT
      LAYER M4 ;
      RECT 199.928 75.168 200.000 75.192 ;
    END
  END m_axis_rc_tdata[106]
  PIN m_axis_rc_tdata[107]
    DIRECTION OUTPUT ;
    USE SIGNAL ;
    PORT
      LAYER M4 ;
      RECT 199.928 75.312 200.000 75.336 ;
    END
  END m_axis_rc_tdata[107]
  PIN m_axis_rc_tdata[108]
    DIRECTION OUTPUT ;
    USE SIGNAL ;
    PORT
      LAYER M4 ;
      RECT 199.928 75.456 200.000 75.480 ;
    END
  END m_axis_rc_tdata[108]
  PIN m_axis_rc_tdata[109]
    DIRECTION OUTPUT ;
    USE SIGNAL ;
    PORT
      LAYER M4 ;
      RECT 199.928 75.600 200.000 75.624 ;
    END
  END m_axis_rc_tdata[109]
  PIN m_axis_rc_tdata[110]
    DIRECTION OUTPUT ;
    USE SIGNAL ;
    PORT
      LAYER M4 ;
      RECT 199.928 75.744 200.000 75.768 ;
    END
  END m_axis_rc_tdata[110]
  PIN m_axis_rc_tdata[111]
    DIRECTION OUTPUT ;
    USE SIGNAL ;
    PORT
      LAYER M4 ;
      RECT 199.928 75.888 200.000 75.912 ;
    END
  END m_axis_rc_tdata[111]
  PIN m_axis_rc_tdata[112]
    DIRECTION OUTPUT ;
    USE SIGNAL ;
    PORT
      LAYER M4 ;
      RECT 199.928 76.032 200.000 76.056 ;
    END
  END m_axis_rc_tdata[112]
  PIN m_axis_rc_tdata[113]
    DIRECTION OUTPUT ;
    USE SIGNAL ;
    PORT
      LAYER M4 ;
      RECT 199.928 76.176 200.000 76.200 ;
    END
  END m_axis_rc_tdata[113]
  PIN m_axis_rc_tdata[114]
    DIRECTION OUTPUT ;
    USE SIGNAL ;
    PORT
      LAYER M4 ;
      RECT 199.928 76.320 200.000 76.344 ;
    END
  END m_axis_rc_tdata[114]
  PIN m_axis_rc_tdata[115]
    DIRECTION OUTPUT ;
    USE SIGNAL ;
    PORT
      LAYER M4 ;
      RECT 199.928 76.464 200.000 76.488 ;
    END
  END m_axis_rc_tdata[115]
  PIN m_axis_rc_tdata[116]
    DIRECTION OUTPUT ;
    USE SIGNAL ;
    PORT
      LAYER M4 ;
      RECT 199.928 76.608 200.000 76.632 ;
    END
  END m_axis_rc_tdata[116]
  PIN m_axis_rc_tdata[117]
    DIRECTION OUTPUT ;
    USE SIGNAL ;
    PORT
      LAYER M4 ;
      RECT 199.928 76.752 200.000 76.776 ;
    END
  END m_axis_rc_tdata[117]
  PIN m_axis_rc_tdata[118]
    DIRECTION OUTPUT ;
    USE SIGNAL ;
    PORT
      LAYER M4 ;
      RECT 199.928 76.896 200.000 76.920 ;
    END
  END m_axis_rc_tdata[118]
  PIN m_axis_rc_tdata[119]
    DIRECTION OUTPUT ;
    USE SIGNAL ;
    PORT
      LAYER M4 ;
      RECT 199.928 77.040 200.000 77.064 ;
    END
  END m_axis_rc_tdata[119]
  PIN m_axis_rc_tdata[120]
    DIRECTION OUTPUT ;
    USE SIGNAL ;
    PORT
      LAYER M4 ;
      RECT 199.928 77.184 200.000 77.208 ;
    END
  END m_axis_rc_tdata[120]
  PIN m_axis_rc_tdata[121]
    DIRECTION OUTPUT ;
    USE SIGNAL ;
    PORT
      LAYER M4 ;
      RECT 199.928 77.328 200.000 77.352 ;
    END
  END m_axis_rc_tdata[121]
  PIN m_axis_rc_tdata[122]
    DIRECTION OUTPUT ;
    USE SIGNAL ;
    PORT
      LAYER M4 ;
      RECT 199.928 77.472 200.000 77.496 ;
    END
  END m_axis_rc_tdata[122]
  PIN m_axis_rc_tdata[123]
    DIRECTION OUTPUT ;
    USE SIGNAL ;
    PORT
      LAYER M4 ;
      RECT 199.928 77.616 200.000 77.640 ;
    END
  END m_axis_rc_tdata[123]
  PIN m_axis_rc_tdata[124]
    DIRECTION OUTPUT ;
    USE SIGNAL ;
    PORT
      LAYER M4 ;
      RECT 199.928 77.760 200.000 77.784 ;
    END
  END m_axis_rc_tdata[124]
  PIN m_axis_rc_tdata[125]
    DIRECTION OUTPUT ;
    USE SIGNAL ;
    PORT
      LAYER M4 ;
      RECT 199.928 77.904 200.000 77.928 ;
    END
  END m_axis_rc_tdata[125]
  PIN m_axis_rc_tdata[126]
    DIRECTION OUTPUT ;
    USE SIGNAL ;
    PORT
      LAYER M4 ;
      RECT 199.928 78.048 200.000 78.072 ;
    END
  END m_axis_rc_tdata[126]
  PIN m_axis_rc_tdata[127]
    DIRECTION OUTPUT ;
    USE SIGNAL ;
    PORT
      LAYER M4 ;
      RECT 199.928 78.192 200.000 78.216 ;
    END
  END m_axis_rc_tdata[127]
  PIN m_axis_rc_tkeep[0]
    DIRECTION OUTPUT ;
    USE SIGNAL ;
    PORT
      LAYER M4 ;
      RECT 199.928 78.336 200.000 78.360 ;
    END
  END m_axis_rc_tkeep[0]
  PIN m_axis_rc_tkeep[1]
    DIRECTION OUTPUT ;
    USE SIGNAL ;
    PORT
      LAYER M4 ;
      RECT 199.928 78.480 200.000 78.504 ;
    END
  END m_axis_rc_tkeep[1]
  PIN m_axis_rc_tkeep[2]
    DIRECTION OUTPUT ;
    USE SIGNAL ;
    PORT
      LAYER M4 ;
      RECT 199.928 78.624 200.000 78.648 ;
    END
  END m_axis_rc_tkeep[2]
  PIN m_axis_rc_tkeep[3]
    DIRECTION OUTPUT ;
    USE SIGNAL ;
    PORT
      LAYER M4 ;
      RECT 199.928 78.768 200.000 78.792 ;
    END
  END m_axis_rc_tkeep[3]
  PIN m_axis_rc_tlast
    DIRECTION OUTPUT ;
    USE SIGNAL ;
    PORT
      LAYER M4 ;
      RECT 199.928 78.912 200.000 78.936 ;
    END
  END m_axis_rc_tlast
  PIN m_axis_rc_tuser[0]
    DIRECTION OUTPUT ;
    USE SIGNAL ;
    PORT
      LAYER M4 ;
      RECT 199.928 79.056 200.000 79.080 ;
    END
  END m_axis_rc_tuser[0]
  PIN m_axis_rc_tuser[1]
    DIRECTION OUTPUT ;
    USE SIGNAL ;
    PORT
      LAYER M4 ;
      RECT 199.928 79.200 200.000 79.224 ;
    END
  END m_axis_rc_tuser[1]
  PIN m_axis_rc_tuser[2]
    DIRECTION OUTPUT ;
    USE SIGNAL ;
    PORT
      LAYER M4 ;
      RECT 199.928 79.344 200.000 79.368 ;
    END
  END m_axis_rc_tuser[2]
  PIN m_axis_rc_tuser[3]
    DIRECTION OUTPUT ;
    USE SIGNAL ;
    PORT
      LAYER M4 ;
      RECT 199.928 79.488 200.000 79.512 ;
    END
  END m_axis_rc_tuser[3]
  PIN m_axis_rc_tuser[4]
    DIRECTION OUTPUT ;
    USE SIGNAL ;
    PORT
      LAYER M4 ;
      RECT 199.928 79.632 200.000 79.656 ;
    END
  END m_axis_rc_tuser[4]
  PIN m_axis_rc_tuser[5]
    DIRECTION OUTPUT ;
    USE SIGNAL ;
    PORT
      LAYER M4 ;
      RECT 199.928 79.776 200.000 79.800 ;
    END
  END m_axis_rc_tuser[5]
  PIN m_axis_rc_tuser[6]
    DIRECTION OUTPUT ;
    USE SIGNAL ;
    PORT
      LAYER M4 ;
      RECT 199.928 79.920 200.000 79.944 ;
    END
  END m_axis_rc_tuser[6]
  PIN m_axis_rc_tuser[7]
    DIRECTION OUTPUT ;
    USE SIGNAL ;
    PORT
      LAYER M4 ;
      RECT 199.928 80.064 200.000 80.088 ;
    END
  END m_axis_rc_tuser[7]
  PIN m_axis_rc_tuser[8]
    DIRECTION OUTPUT ;
    USE SIGNAL ;
    PORT
      LAYER M4 ;
      RECT 199.928 80.208 200.000 80.232 ;
    END
  END m_axis_rc_tuser[8]
  PIN m_axis_rc_tuser[9]
    DIRECTION OUTPUT ;
    USE SIGNAL ;
    PORT
      LAYER M4 ;
      RECT 199.928 80.352 200.000 80.376 ;
    END
  END m_axis_rc_tuser[9]
  PIN m_axis_rc_tuser[10]
    DIRECTION OUTPUT ;
    USE SIGNAL ;
    PORT
      LAYER M4 ;
      RECT 199.928 80.496 200.000 80.520 ;
    END
  END m_axis_rc_tuser[10]
  PIN m_axis_rc_tuser[11]
    DIRECTION OUTPUT ;
    USE SIGNAL ;
    PORT
      LAYER M4 ;
      RECT 199.928 80.640 200.000 80.664 ;
    END
  END m_axis_rc_tuser[11]
  PIN m_axis_rc_tuser[12]
    DIRECTION OUTPUT ;
    USE SIGNAL ;
    PORT
      LAYER M4 ;
      RECT 199.928 80.784 200.000 80.808 ;
    END
  END m_axis_rc_tuser[12]
  PIN m_axis_rc_tuser[13]
    DIRECTION OUTPUT ;
    USE SIGNAL ;
    PORT
      LAYER M4 ;
      RECT 199.928 80.928 200.000 80.952 ;
    END
  END m_axis_rc_tuser[13]
  PIN m_axis_rc_tuser[14]
    DIRECTION OUTPUT ;
    USE SIGNAL ;
    PORT
      LAYER M4 ;
      RECT 199.928 81.072 200.000 81.096 ;
    END
  END m_axis_rc_tuser[14]
  PIN m_axis_rc_tuser[15]
    DIRECTION OUTPUT ;
    USE SIGNAL ;
    PORT
      LAYER M4 ;
      RECT 199.928 81.216 200.000 81.240 ;
    END
  END m_axis_rc_tuser[15]
  PIN m_axis_rc_tuser[16]
    DIRECTION OUTPUT ;
    USE SIGNAL ;
    PORT
      LAYER M4 ;
      RECT 199.928 81.360 200.000 81.384 ;
    END
  END m_axis_rc_tuser[16]
  PIN m_axis_rc_tuser[17]
    DIRECTION OUTPUT ;
    USE SIGNAL ;
    PORT
      LAYER M4 ;
      RECT 199.928 81.504 200.000 81.528 ;
    END
  END m_axis_rc_tuser[17]
  PIN m_axis_rc_tuser[18]
    DIRECTION OUTPUT ;
    USE SIGNAL ;
    PORT
      LAYER M4 ;
      RECT 199.928 81.648 200.000 81.672 ;
    END
  END m_axis_rc_tuser[18]
  PIN m_axis_rc_tuser[19]
    DIRECTION OUTPUT ;
    USE SIGNAL ;
    PORT
      LAYER M4 ;
      RECT 199.928 81.792 200.000 81.816 ;
    END
  END m_axis_rc_tuser[19]
  PIN m_axis_rc_tuser[20]
    DIRECTION OUTPUT ;
    USE SIGNAL ;
    PORT
      LAYER M4 ;
      RECT 199.928 81.936 200.000 81.960 ;
    END
  END m_axis_rc_tuser[20]
  PIN m_axis_rc_tuser[21]
    DIRECTION OUTPUT ;
    USE SIGNAL ;
    PORT
      LAYER M4 ;
      RECT 199.928 82.080 200.000 82.104 ;
    END
  END m_axis_rc_tuser[21]
  PIN m_axis_rc_tuser[22]
    DIRECTION OUTPUT ;
    USE SIGNAL ;
    PORT
      LAYER M4 ;
      RECT 199.928 82.224 200.000 82.248 ;
    END
  END m_axis_rc_tuser[22]
  PIN m_axis_rc_tuser[23]
    DIRECTION OUTPUT ;
    USE SIGNAL ;
    PORT
      LAYER M4 ;
      RECT 199.928 82.368 200.000 82.392 ;
    END
  END m_axis_rc_tuser[23]
  PIN m_axis_rc_tuser[24]
    DIRECTION OUTPUT ;
    USE SIGNAL ;
    PORT
      LAYER M4 ;
      RECT 199.928 82.512 200.000 82.536 ;
    END
  END m_axis_rc_tuser[24]
  PIN m_axis_rc_tuser[25]
    DIRECTION OUTPUT ;
    USE SIGNAL ;
    PORT
      LAYER M4 ;
      RECT 199.928 82.656 200.000 82.680 ;
    END
  END m_axis_rc_tuser[25]
  PIN m_axis_rc_tuser[26]
    DIRECTION OUTPUT ;
    USE SIGNAL ;
    PORT
      LAYER M4 ;
      RECT 199.928 82.800 200.000 82.824 ;
    END
  END m_axis_rc_tuser[26]
  PIN m_axis_rc_tuser[27]
    DIRECTION OUTPUT ;
    USE SIGNAL ;
    PORT
      LAYER M4 ;
      RECT 199.928 82.944 200.000 82.968 ;
    END
  END m_axis_rc_tuser[27]
  PIN m_axis_rc_tuser[28]
    DIRECTION OUTPUT ;
    USE SIGNAL ;
    PORT
      LAYER M4 ;
      RECT 199.928 83.088 200.000 83.112 ;
    END
  END m_axis_rc_tuser[28]
  PIN m_axis_rc_tuser[29]
    DIRECTION OUTPUT ;
    USE SIGNAL ;
    PORT
      LAYER M4 ;
      RECT 199.928 83.232 200.000 83.256 ;
    END
  END m_axis_rc_tuser[29]
  PIN m_axis_rc_tuser[30]
    DIRECTION OUTPUT ;
    USE SIGNAL ;
    PORT
      LAYER M4 ;
      RECT 199.928 83.376 200.000 83.400 ;
    END
  END m_axis_rc_tuser[30]
  PIN m_axis_rc_tuser[31]
    DIRECTION OUTPUT ;
    USE SIGNAL ;
    PORT
      LAYER M4 ;
      RECT 199.928 83.520 200.000 83.544 ;
    END
  END m_axis_rc_tuser[31]
  PIN m_axis_rc_tuser[32]
    DIRECTION OUTPUT ;
    USE SIGNAL ;
    PORT
      LAYER M4 ;
      RECT 199.928 83.664 200.000 83.688 ;
    END
  END m_axis_rc_tuser[32]
  PIN m_axis_rc_tuser[33]
    DIRECTION OUTPUT ;
    USE SIGNAL ;
    PORT
      LAYER M4 ;
      RECT 199.928 83.808 200.000 83.832 ;
    END
  END m_axis_rc_tuser[33]
  PIN m_axis_rc_tuser[34]
    DIRECTION OUTPUT ;
    USE SIGNAL ;
    PORT
      LAYER M4 ;
      RECT 199.928 83.952 200.000 83.976 ;
    END
  END m_axis_rc_tuser[34]
  PIN m_axis_rc_tuser[35]
    DIRECTION OUTPUT ;
    USE SIGNAL ;
    PORT
      LAYER M4 ;
      RECT 199.928 84.096 200.000 84.120 ;
    END
  END m_axis_rc_tuser[35]
  PIN m_axis_rc_tuser[36]
    DIRECTION OUTPUT ;
    USE SIGNAL ;
    PORT
      LAYER M4 ;
      RECT 199.928 84.240 200.000 84.264 ;
    END
  END m_axis_rc_tuser[36]
  PIN m_axis_rc_tuser[37]
    DIRECTION OUTPUT ;
    USE SIGNAL ;
    PORT
      LAYER M4 ;
      RECT 199.928 84.384 200.000 84.408 ;
    END
  END m_axis_rc_tuser[37]
  PIN m_axis_rc_tuser[38]
    DIRECTION OUTPUT ;
    USE SIGNAL ;
    PORT
      LAYER M4 ;
      RECT 199.928 84.528 200.000 84.552 ;
    END
  END m_axis_rc_tuser[38]
  PIN m_axis_rc_tuser[39]
    DIRECTION OUTPUT ;
    USE SIGNAL ;
    PORT
      LAYER M4 ;
      RECT 199.928 84.672 200.000 84.696 ;
    END
  END m_axis_rc_tuser[39]
  PIN m_axis_rc_tuser[40]
    DIRECTION OUTPUT ;
    USE SIGNAL ;
    PORT
      LAYER M4 ;
      RECT 199.928 84.816 200.000 84.840 ;
    END
  END m_axis_rc_tuser[40]
  PIN m_axis_rc_tuser[41]
    DIRECTION OUTPUT ;
    USE SIGNAL ;
    PORT
      LAYER M4 ;
      RECT 199.928 84.960 200.000 84.984 ;
    END
  END m_axis_rc_tuser[41]
  PIN m_axis_rc_tuser[42]
    DIRECTION OUTPUT ;
    USE SIGNAL ;
    PORT
      LAYER M4 ;
      RECT 199.928 85.104 200.000 85.128 ;
    END
  END m_axis_rc_tuser[42]
  PIN m_axis_rc_tuser[43]
    DIRECTION OUTPUT ;
    USE SIGNAL ;
    PORT
      LAYER M4 ;
      RECT 199.928 85.248 200.000 85.272 ;
    END
  END m_axis_rc_tuser[43]
  PIN m_axis_rc_tuser[44]
    DIRECTION OUTPUT ;
    USE SIGNAL ;
    PORT
      LAYER M4 ;
      RECT 199.928 85.392 200.000 85.416 ;
    END
  END m_axis_rc_tuser[44]
  PIN m_axis_rc_tuser[45]
    DIRECTION OUTPUT ;
    USE SIGNAL ;
    PORT
      LAYER M4 ;
      RECT 199.928 85.536 200.000 85.560 ;
    END
  END m_axis_rc_tuser[45]
  PIN m_axis_rc_tuser[46]
    DIRECTION OUTPUT ;
    USE SIGNAL ;
    PORT
      LAYER M4 ;
      RECT 199.928 85.680 200.000 85.704 ;
    END
  END m_axis_rc_tuser[46]
  PIN m_axis_rc_tuser[47]
    DIRECTION OUTPUT ;
    USE SIGNAL ;
    PORT
      LAYER M4 ;
      RECT 199.928 85.824 200.000 85.848 ;
    END
  END m_axis_rc_tuser[47]
  PIN m_axis_rc_tuser[48]
    DIRECTION OUTPUT ;
    USE SIGNAL ;
    PORT
      LAYER M4 ;
      RECT 199.928 85.968 200.000 85.992 ;
    END
  END m_axis_rc_tuser[48]
  PIN m_axis_rc_tuser[49]
    DIRECTION OUTPUT ;
    USE SIGNAL ;
    PORT
      LAYER M4 ;
      RECT 199.928 86.112 200.000 86.136 ;
    END
  END m_axis_rc_tuser[49]
  PIN m_axis_rc_tuser[50]
    DIRECTION OUTPUT ;
    USE SIGNAL ;
    PORT
      LAYER M4 ;
      RECT 199.928 86.256 200.000 86.280 ;
    END
  END m_axis_rc_tuser[50]
  PIN m_axis_rc_tuser[51]
    DIRECTION OUTPUT ;
    USE SIGNAL ;
    PORT
      LAYER M4 ;
      RECT 199.928 86.400 200.000 86.424 ;
    END
  END m_axis_rc_tuser[51]
  PIN m_axis_rc_tuser[52]
    DIRECTION OUTPUT ;
    USE SIGNAL ;
    PORT
      LAYER M4 ;
      RECT 199.928 86.544 200.000 86.568 ;
    END
  END m_axis_rc_tuser[52]
  PIN m_axis_rc_tuser[53]
    DIRECTION OUTPUT ;
    USE SIGNAL ;
    PORT
      LAYER M4 ;
      RECT 199.928 86.688 200.000 86.712 ;
    END
  END m_axis_rc_tuser[53]
  PIN m_axis_rc_tuser[54]
    DIRECTION OUTPUT ;
    USE SIGNAL ;
    PORT
      LAYER M4 ;
      RECT 199.928 86.832 200.000 86.856 ;
    END
  END m_axis_rc_tuser[54]
  PIN m_axis_rc_tuser[55]
    DIRECTION OUTPUT ;
    USE SIGNAL ;
    PORT
      LAYER M4 ;
      RECT 199.928 86.976 200.000 87.000 ;
    END
  END m_axis_rc_tuser[55]
  PIN m_axis_rc_tuser[56]
    DIRECTION OUTPUT ;
    USE SIGNAL ;
    PORT
      LAYER M4 ;
      RECT 199.928 87.120 200.000 87.144 ;
    END
  END m_axis_rc_tuser[56]
  PIN m_axis_rc_tuser[57]
    DIRECTION OUTPUT ;
    USE SIGNAL ;
    PORT
      LAYER M4 ;
      RECT 199.928 87.264 200.000 87.288 ;
    END
  END m_axis_rc_tuser[57]
  PIN m_axis_rc_tuser[58]
    DIRECTION OUTPUT ;
    USE SIGNAL ;
    PORT
      LAYER M4 ;
      RECT 199.928 87.408 200.000 87.432 ;
    END
  END m_axis_rc_tuser[58]
  PIN m_axis_rc_tuser[59]
    DIRECTION OUTPUT ;
    USE SIGNAL ;
    PORT
      LAYER M4 ;
      RECT 199.928 87.552 200.000 87.576 ;
    END
  END m_axis_rc_tuser[59]
  PIN m_axis_rc_tuser[60]
    DIRECTION OUTPUT ;
    USE SIGNAL ;
    PORT
      LAYER M4 ;
      RECT 199.928 87.696 200.000 87.720 ;
    END
  END m_axis_rc_tuser[60]
  PIN m_axis_rc_tuser[61]
    DIRECTION OUTPUT ;
    USE SIGNAL ;
    PORT
      LAYER M4 ;
      RECT 199.928 87.840 200.000 87.864 ;
    END
  END m_axis_rc_tuser[61]
  PIN m_axis_rc_tuser[62]
    DIRECTION OUTPUT ;
    USE SIGNAL ;
    PORT
      LAYER M4 ;
      RECT 199.928 87.984 200.000 88.008 ;
    END
  END m_axis_rc_tuser[62]
  PIN m_axis_rc_tuser[63]
    DIRECTION OUTPUT ;
    USE SIGNAL ;
    PORT
      LAYER M4 ;
      RECT 199.928 88.128 200.000 88.152 ;
    END
  END m_axis_rc_tuser[63]
  PIN m_axis_rc_tuser[64]
    DIRECTION OUTPUT ;
    USE SIGNAL ;
    PORT
      LAYER M4 ;
      RECT 199.928 88.272 200.000 88.296 ;
    END
  END m_axis_rc_tuser[64]
  PIN m_axis_rc_tuser[65]
    DIRECTION OUTPUT ;
    USE SIGNAL ;
    PORT
      LAYER M4 ;
      RECT 199.928 88.416 200.000 88.440 ;
    END
  END m_axis_rc_tuser[65]
  PIN m_axis_rc_tuser[66]
    DIRECTION OUTPUT ;
    USE SIGNAL ;
    PORT
      LAYER M4 ;
      RECT 199.928 88.560 200.000 88.584 ;
    END
  END m_axis_rc_tuser[66]
  PIN m_axis_rc_tuser[67]
    DIRECTION OUTPUT ;
    USE SIGNAL ;
    PORT
      LAYER M4 ;
      RECT 199.928 88.704 200.000 88.728 ;
    END
  END m_axis_rc_tuser[67]
  PIN m_axis_rc_tuser[68]
    DIRECTION OUTPUT ;
    USE SIGNAL ;
    PORT
      LAYER M4 ;
      RECT 199.928 88.848 200.000 88.872 ;
    END
  END m_axis_rc_tuser[68]
  PIN m_axis_rc_tuser[69]
    DIRECTION OUTPUT ;
    USE SIGNAL ;
    PORT
      LAYER M4 ;
      RECT 199.928 88.992 200.000 89.016 ;
    END
  END m_axis_rc_tuser[69]
  PIN m_axis_rc_tuser[70]
    DIRECTION OUTPUT ;
    USE SIGNAL ;
    PORT
      LAYER M4 ;
      RECT 199.928 89.136 200.000 89.160 ;
    END
  END m_axis_rc_tuser[70]
  PIN m_axis_rc_tuser[71]
    DIRECTION OUTPUT ;
    USE SIGNAL ;
    PORT
      LAYER M4 ;
      RECT 199.928 89.280 200.000 89.304 ;
    END
  END m_axis_rc_tuser[71]
  PIN m_axis_rc_tuser[72]
    DIRECTION OUTPUT ;
    USE SIGNAL ;
    PORT
      LAYER M4 ;
      RECT 199.928 89.424 200.000 89.448 ;
    END
  END m_axis_rc_tuser[72]
  PIN m_axis_rc_tuser[73]
    DIRECTION OUTPUT ;
    USE SIGNAL ;
    PORT
      LAYER M4 ;
      RECT 199.928 89.568 200.000 89.592 ;
    END
  END m_axis_rc_tuser[73]
  PIN m_axis_rc_tuser[74]
    DIRECTION OUTPUT ;
    USE SIGNAL ;
    PORT
      LAYER M4 ;
      RECT 199.928 89.712 200.000 89.736 ;
    END
  END m_axis_rc_tuser[74]
  PIN m_axis_rc_tvalid
    DIRECTION OUTPUT ;
    USE SIGNAL ;
    PORT
      LAYER M4 ;
      RECT 199.928 89.856 200.000 89.880 ;
    END
  END m_axis_rc_tvalid
  PIN pci_exp_txn
    DIRECTION OUTPUT ;
    USE SIGNAL ;
    PORT
      LAYER M4 ;
      RECT 199.928 90.000 200.000 90.024 ;
    END
  END pci_exp_txn
  PIN pci_exp_txp
    DIRECTION OUTPUT ;
    USE SIGNAL ;
    PORT
      LAYER M4 ;
      RECT 199.928 90.144 200.000 90.168 ;
    END
  END pci_exp_txp
  PIN pcie_perstn0_out
    DIRECTION OUTPUT ;
    USE SIGNAL ;
    PORT
      LAYER M4 ;
      RECT 199.928 90.288 200.000 90.312 ;
    END
  END pcie_perstn0_out
  PIN pcie_perstn1_out
    DIRECTION OUTPUT ;
    USE SIGNAL ;
    PORT
      LAYER M4 ;
      RECT 199.928 90.432 200.000 90.456 ;
    END
  END pcie_perstn1_out
  PIN pcie_rq_tag_av[0]
    DIRECTION OUTPUT ;
    USE SIGNAL ;
    PORT
      LAYER M4 ;
      RECT 199.928 90.576 200.000 90.600 ;
    END
  END pcie_rq_tag_av[0]
  PIN pcie_rq_tag_av[1]
    DIRECTION OUTPUT ;
    USE SIGNAL ;
    PORT
      LAYER M4 ;
      RECT 199.928 90.720 200.000 90.744 ;
    END
  END pcie_rq_tag_av[1]
  PIN pcie_rq_tag_av[2]
    DIRECTION OUTPUT ;
    USE SIGNAL ;
    PORT
      LAYER M4 ;
      RECT 199.928 90.864 200.000 90.888 ;
    END
  END pcie_rq_tag_av[2]
  PIN pcie_rq_tag_av[3]
    DIRECTION OUTPUT ;
    USE SIGNAL ;
    PORT
      LAYER M4 ;
      RECT 199.928 91.008 200.000 91.032 ;
    END
  END pcie_rq_tag_av[3]
  PIN pcie_tfc_npd_av[0]
    DIRECTION OUTPUT ;
    USE SIGNAL ;
    PORT
      LAYER M4 ;
      RECT 199.928 91.152 200.000 91.176 ;
    END
  END pcie_tfc_npd_av[0]
  PIN pcie_tfc_npd_av[1]
    DIRECTION OUTPUT ;
    USE SIGNAL ;
    PORT
      LAYER M4 ;
      RECT 199.928 91.296 200.000 91.320 ;
    END
  END pcie_tfc_npd_av[1]
  PIN pcie_tfc_npd_av[2]
    DIRECTION OUTPUT ;
    USE SIGNAL ;
    PORT
      LAYER M4 ;
      RECT 199.928 91.440 200.000 91.464 ;
    END
  END pcie_tfc_npd_av[2]
  PIN pcie_tfc_npd_av[3]
    DIRECTION OUTPUT ;
    USE SIGNAL ;
    PORT
      LAYER M4 ;
      RECT 199.928 91.584 200.000 91.608 ;
    END
  END pcie_tfc_npd_av[3]
  PIN pcie_tfc_nph_av[0]
    DIRECTION OUTPUT ;
    USE SIGNAL ;
    PORT
      LAYER M4 ;
      RECT 199.928 91.728 200.000 91.752 ;
    END
  END pcie_tfc_nph_av[0]
  PIN pcie_tfc_nph_av[1]
    DIRECTION OUTPUT ;
    USE SIGNAL ;
    PORT
      LAYER M4 ;
      RECT 199.928 91.872 200.000 91.896 ;
    END
  END pcie_tfc_nph_av[1]
  PIN pcie_tfc_nph_av[2]
    DIRECTION OUTPUT ;
    USE SIGNAL ;
    PORT
      LAYER M4 ;
      RECT 199.928 92.016 200.000 92.040 ;
    END
  END pcie_tfc_nph_av[2]
  PIN pcie_tfc_nph_av[3]
    DIRECTION OUTPUT ;
    USE SIGNAL ;
    PORT
      LAYER M4 ;
      RECT 199.928 92.160 200.000 92.184 ;
    END
  END pcie_tfc_nph_av[3]
  PIN phy_rdy_out
    DIRECTION OUTPUT ;
    USE SIGNAL ;
    PORT
      LAYER M4 ;
      RECT 199.928 92.304 200.000 92.328 ;
    END
  END phy_rdy_out
  PIN s_axis_cc_tready[0]
    DIRECTION OUTPUT ;
    USE SIGNAL ;
    PORT
      LAYER M4 ;
      RECT 199.928 92.448 200.000 92.472 ;
    END
  END s_axis_cc_tready[0]
  PIN s_axis_cc_tready[1]
    DIRECTION OUTPUT ;
    USE SIGNAL ;
    PORT
      LAYER M4 ;
      RECT 199.928 92.592 200.000 92.616 ;
    END
  END s_axis_cc_tready[1]
  PIN s_axis_cc_tready[2]
    DIRECTION OUTPUT ;
    USE SIGNAL ;
    PORT
      LAYER M4 ;
      RECT 199.928 92.736 200.000 92.760 ;
    END
  END s_axis_cc_tready[2]
  PIN s_axis_cc_tready[3]
    DIRECTION OUTPUT ;
    USE SIGNAL ;
    PORT
      LAYER M4 ;
      RECT 199.928 92.880 200.000 92.904 ;
    END
  END s_axis_cc_tready[3]
  PIN s_axis_rq_tready[0]
    DIRECTION OUTPUT ;
    USE SIGNAL ;
    PORT
      LAYER M4 ;
      RECT 199.928 93.024 200.000 93.048 ;
    END
  END s_axis_rq_tready[0]
  PIN s_axis_rq_tready[1]
    DIRECTION OUTPUT ;
    USE SIGNAL ;
    PORT
      LAYER M4 ;
      RECT 199.928 93.168 200.000 93.192 ;
    END
  END s_axis_rq_tready[1]
  PIN s_axis_rq_tready[2]
    DIRECTION OUTPUT ;
    USE SIGNAL ;
    PORT
      LAYER M4 ;
      RECT 199.928 93.312 200.000 93.336 ;
    END
  END s_axis_rq_tready[2]
  PIN s_axis_rq_tready[3]
    DIRECTION OUTPUT ;
    USE SIGNAL ;
    PORT
      LAYER M4 ;
      RECT 199.928 93.456 200.000 93.480 ;
    END
  END s_axis_rq_tready[3]
  PIN user_clk
    DIRECTION OUTPUT ;
    USE SIGNAL ;
    PORT
      LAYER M4 ;
      RECT 199.928 93.600 200.000 93.624 ;
    END
  END user_clk
  PIN user_lnk_up
    DIRECTION OUTPUT ;
    USE SIGNAL ;
    PORT
      LAYER M4 ;
      RECT 199.928 93.744 200.000 93.768 ;
    END
  END user_lnk_up
  PIN user_reset
    DIRECTION OUTPUT ;
    USE SIGNAL ;
    PORT
      LAYER M4 ;
      RECT 199.928 93.888 200.000 93.912 ;
    END
  END user_reset
END pcie_us

END LIBRARY
